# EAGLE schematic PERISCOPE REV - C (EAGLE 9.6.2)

## Sheet 1 of 20: Clock, Horizontal Sync

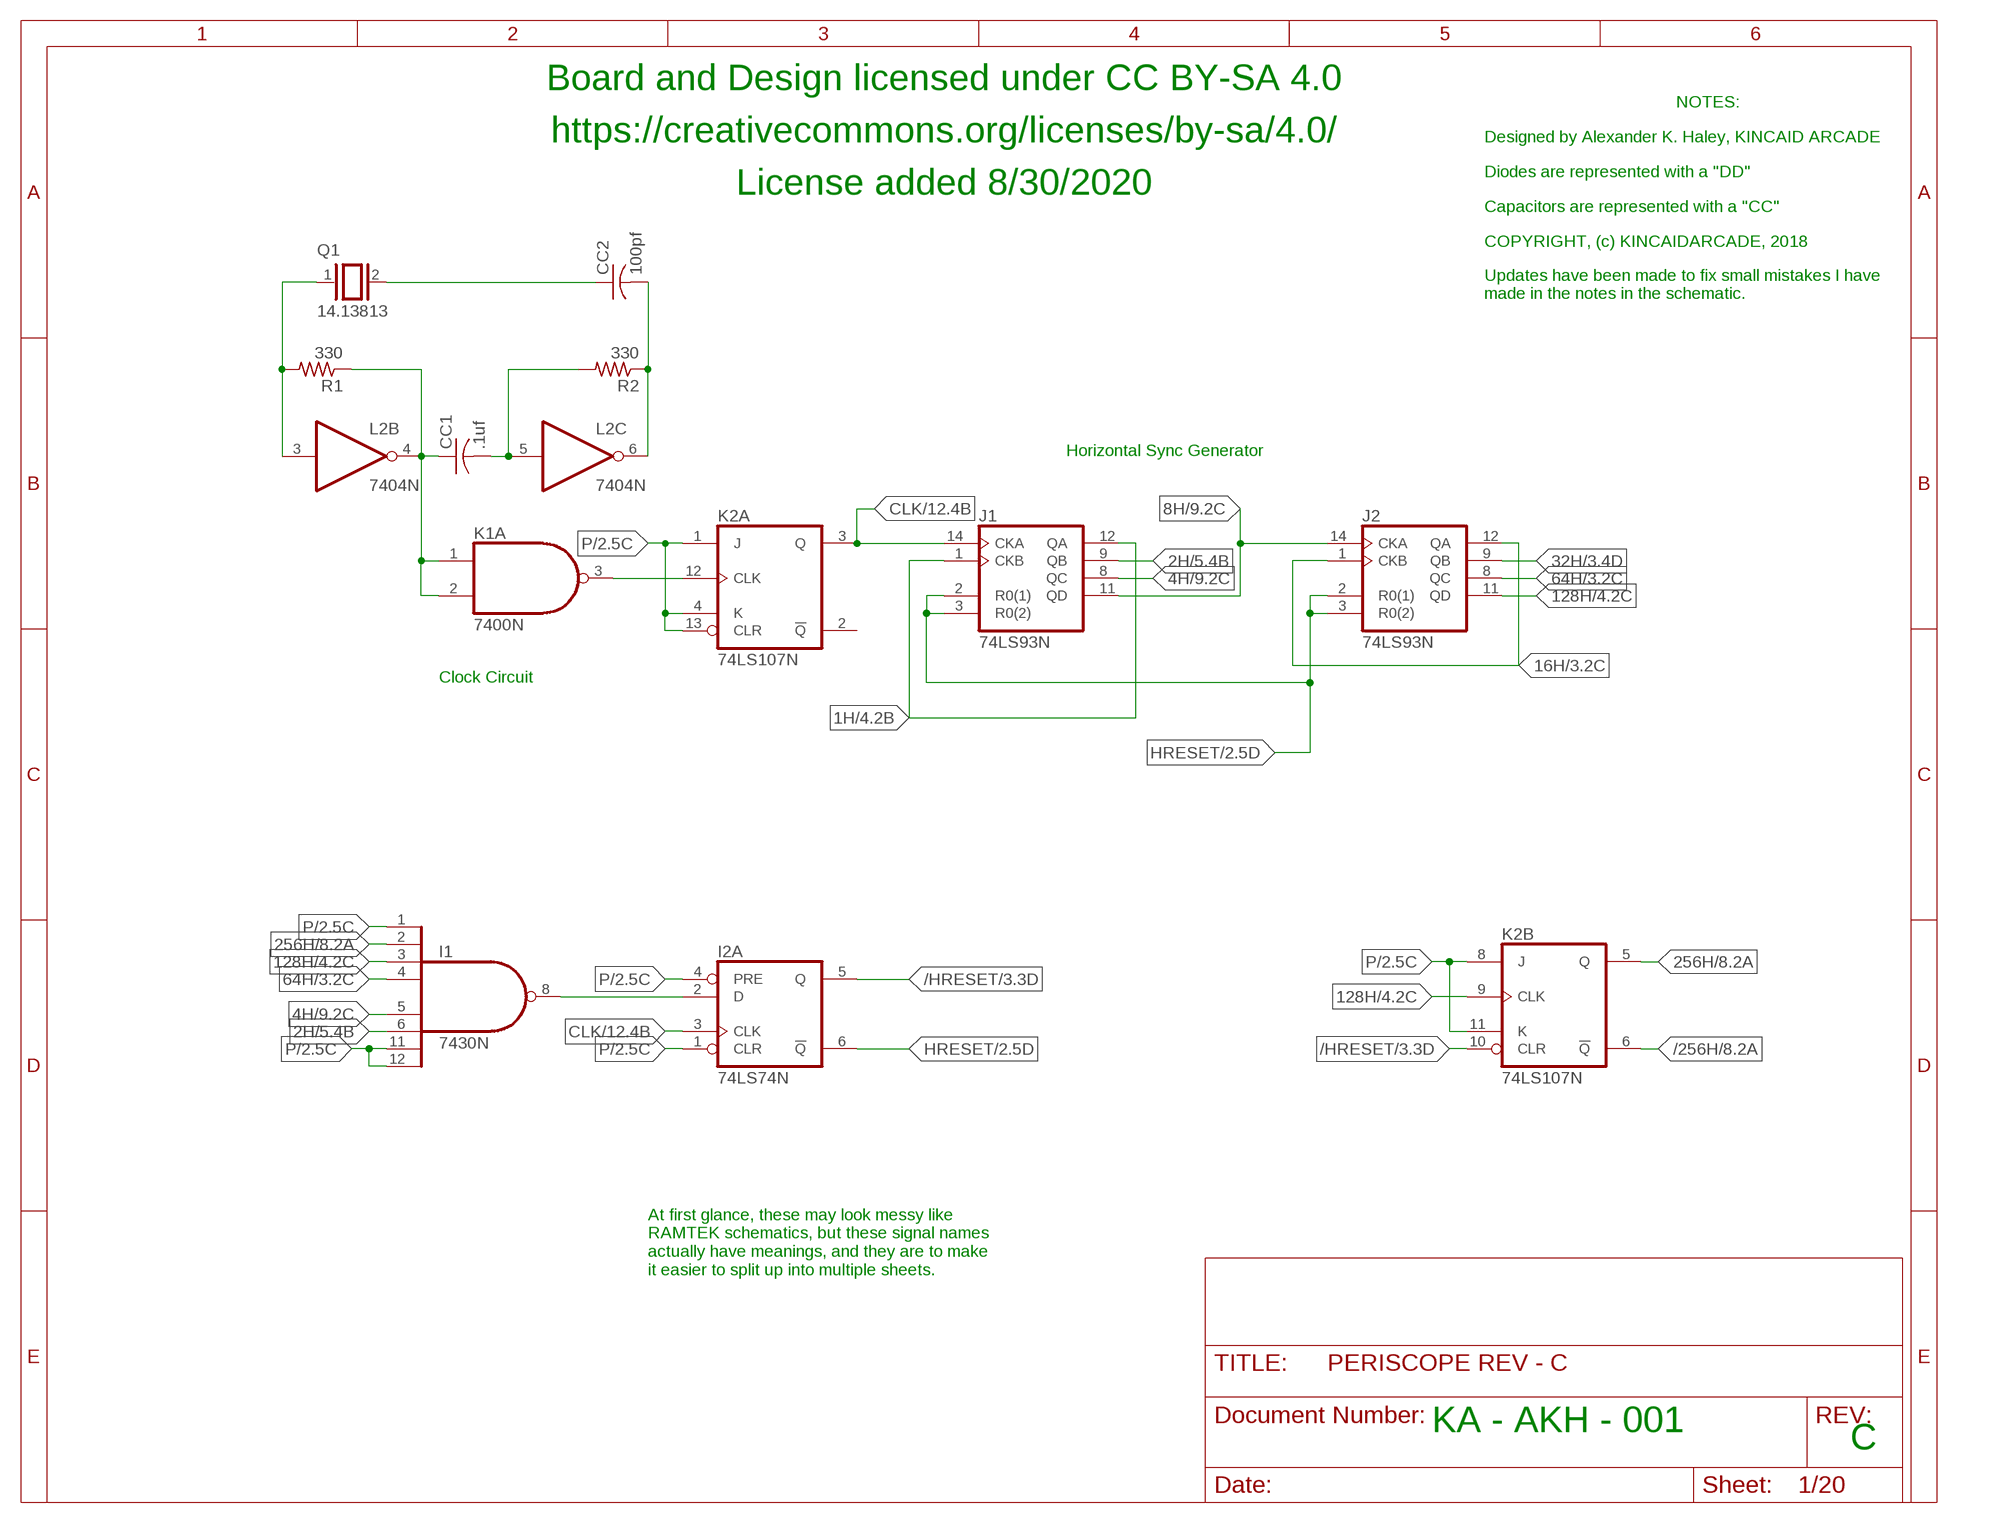
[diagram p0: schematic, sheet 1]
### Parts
CC1  .1uf  C-US050-025X075  [C050-025X075]
CC2  100pf  C-US050-025X075  [C050-025X075]
I1  7430N  [DIL14]
I2  74LS74N  [DIL14]
J1  74LS93N  [DIL14]
J2  74LS93N  [DIL14]
K1  7400N  [DIL14]
K2  74LS107N  [DIL14]
L2  7404N  [DIL14]
Q1  14.13813  XTAL/S  [QS]
R1  330  R-US_0207/10  [0207/10]
R2  330  R-US_0207/10  [0207/10]

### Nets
1H: J1.1(CKB) J1.12(QA) ; also sheet 4,16,17
2H: I1.6(I5) J1.9(QB) ; also sheet 5,16,17
4H: I1.5(I4) J1.8(QC) ; also sheet 9,16,17
8H: J1.11(QD) J2.14(CKA) ; also sheet 9,16,17,19
16H: J2.1(CKB) J2.12(QA) ; also sheet 3,4,8,9,14
32H: J2.9(QB) ; also sheet 3,4,8,14
64H: I1.4(I3) J2.8(QC) ; also sheet 3,4,8,14
128H: I1.3(I2) J2.11(QD) K2.9(B:CLK) ; also sheet 4,8,19
256H: I1.2(I1) K2.5(B:Q) ; also sheet 8,14
/256H: K2.6(B:!Q) ; also sheet 8,19
/HRESET: I2.5(A:Q) K2.10(B:CLR) ; also sheet 3
CLK: I2.3(A:CLK) J1.14(CKA) K2.3(A:Q) ; also sheet 12,18
HRESET: I2.6(A:!Q) J1.2(R0(1)) J1.3(R0(2)) J2.2(R0(1)) J2.3(R0(2)) ; also sheet 2
N$1: CC2.1 Q1.2
N$2: CC2.2 L2.6(C:O) R2.1
N$3: CC1.1 K1.1(A:I0) K1.2(A:I1) L2.4(B:O) R1.1
N$4: CC1.2 L2.5(C:I) R2.2
N$5: L2.3(B:I) Q1.1 R1.2
N$6: K1.3(A:O) K2.12(A:CLK)
N$11: I1.8(O) I2.2(A:D)
P: I1.1(I0) I1.11(I6) I1.12(I7) I2.1(A:CLR) I2.4(A:PRE) K2.1(A:J) K2.4(A:K) K2.8(B:J) K2.11(B:K) K2.13(A:CLR) ; also sheet 2,6,7,8,9,10,11,14,15,18,19,20
Unconnected: K2.2(A:!Q)

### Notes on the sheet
- Board and Design licensed under CC BY-SA 4.0
- NOTES:
- https://creativecommons.org/licenses/by-sa/4.0/ | Designed by Alexander K. Haley, KINCAID ARCADE
- Diodes are represented with a "DD"
- License added 8/30/2020
- Capacitors are represented with a "CC"
- COPYRIGHT, (c) KINCAIDARCADE, 2018
- Updates have been made to fix small mistakes I have 
  made in the notes in the schematic.
- Horizontal Sync Generator
- Clock Circuit
- At first glance, these may look messy like
  RAMTEK schematics, but these signal names
  actually have meanings, and they are to make
  it easier to split up into multiple sheets.
- KA - AKH - 001
- C

## Sheet 2 of 20: Vertical Sync Generator

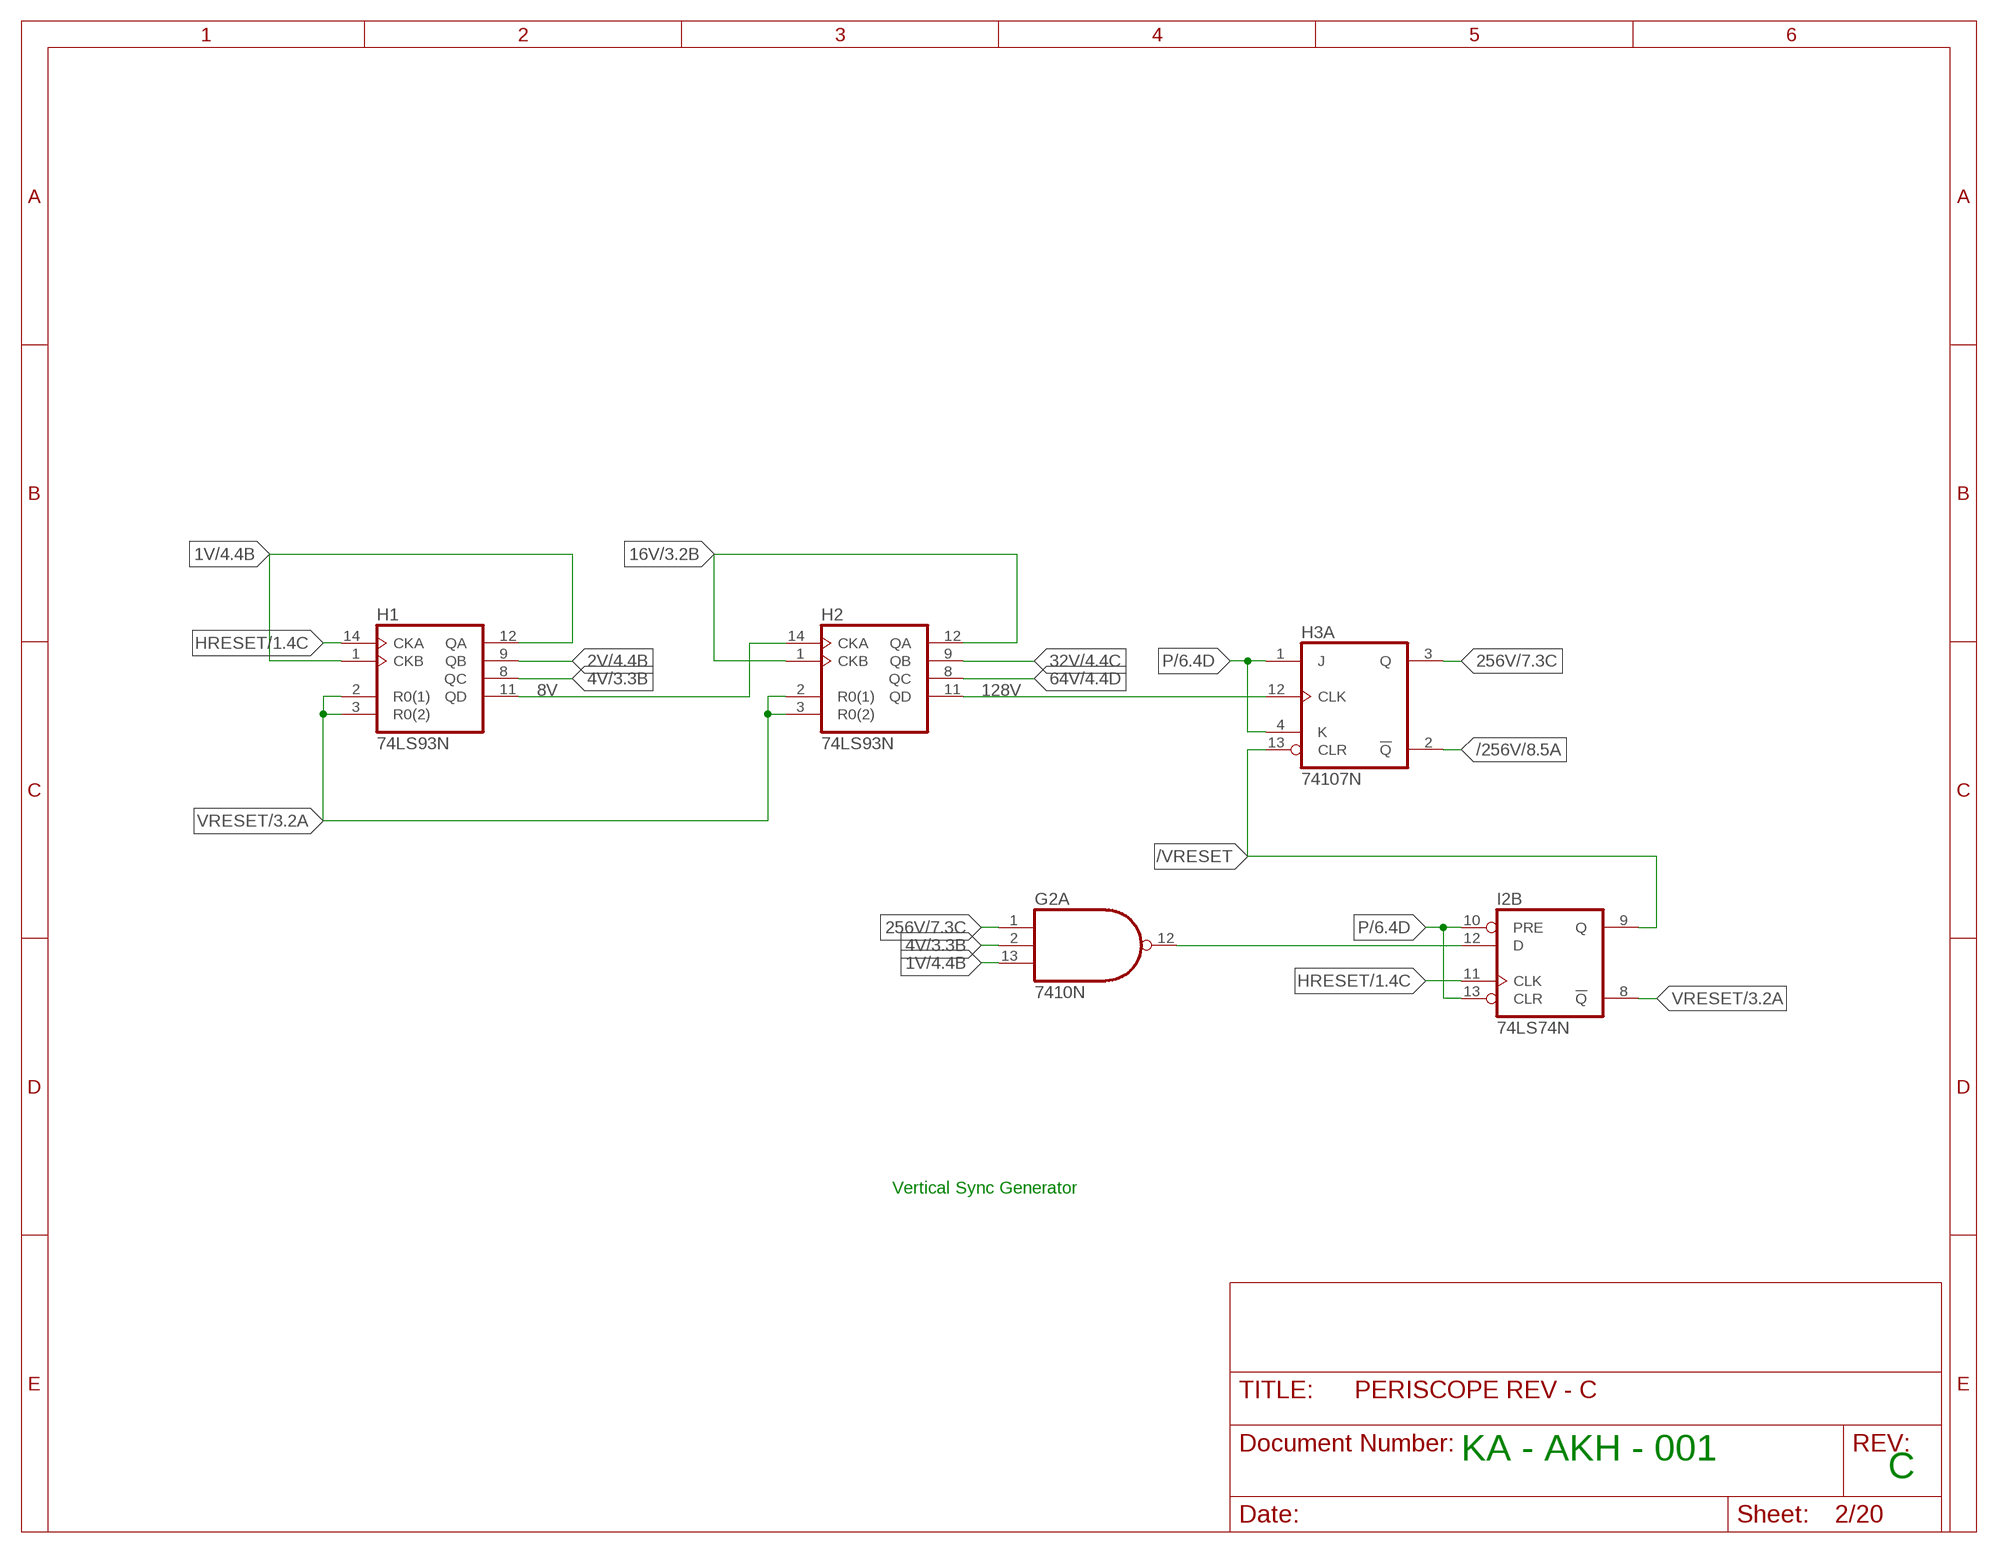
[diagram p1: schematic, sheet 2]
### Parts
G2  7410N  [DIL14]
H1  74LS93N  [DIL14]
H2  74LS93N  [DIL14]
H3  74107N  [DIL14]

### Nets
1V: G2.13(A:I2) H1.1(CKB) H1.12(QA) ; also sheet 4
2V: H1.9(QB) ; also sheet 4
4V: G2.2(A:I1) H1.8(QC) ; also sheet 3,4,9,19
8V: H1.11(QD) H2.14(CKA) ; also sheet 3,4,9,12,13
16V: H2.1(CKB) H2.12(QA) ; also sheet 3,4,9,10,15
32V: H2.9(QB) ; also sheet 4,8,10,15
64V: H2.8(QC) ; also sheet 4,10,15
128V: H2.11(QD) H3.12(A:CLK) ; also sheet 4,5,6,15
256V: G2.1(A:I0) H3.3(A:Q) ; also sheet 7,19
/256V: H3.2(A:!Q) ; also sheet 8
/VRESET: H3.13(A:CLR) I2.9(B:Q)
HRESET: H1.14(CKA) I2.11(B:CLK) ; also sheet 1
N$17: G2.12(A:O) I2.12(B:D)
P: H3.1(A:J) H3.4(A:K) I2.10(B:PRE) I2.13(B:CLR) ; also sheet 1,6,7,8,9,10,11,14,15,18,19,20
VRESET: H1.2(R0(1)) H1.3(R0(2)) H2.2(R0(1)) H2.3(R0(2)) I2.8(B:!Q) ; also sheet 3,11

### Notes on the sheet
- Vertical Sync Generator
- KA - AKH - 001
- C

## Sheet 3 of 20: Sync Generation

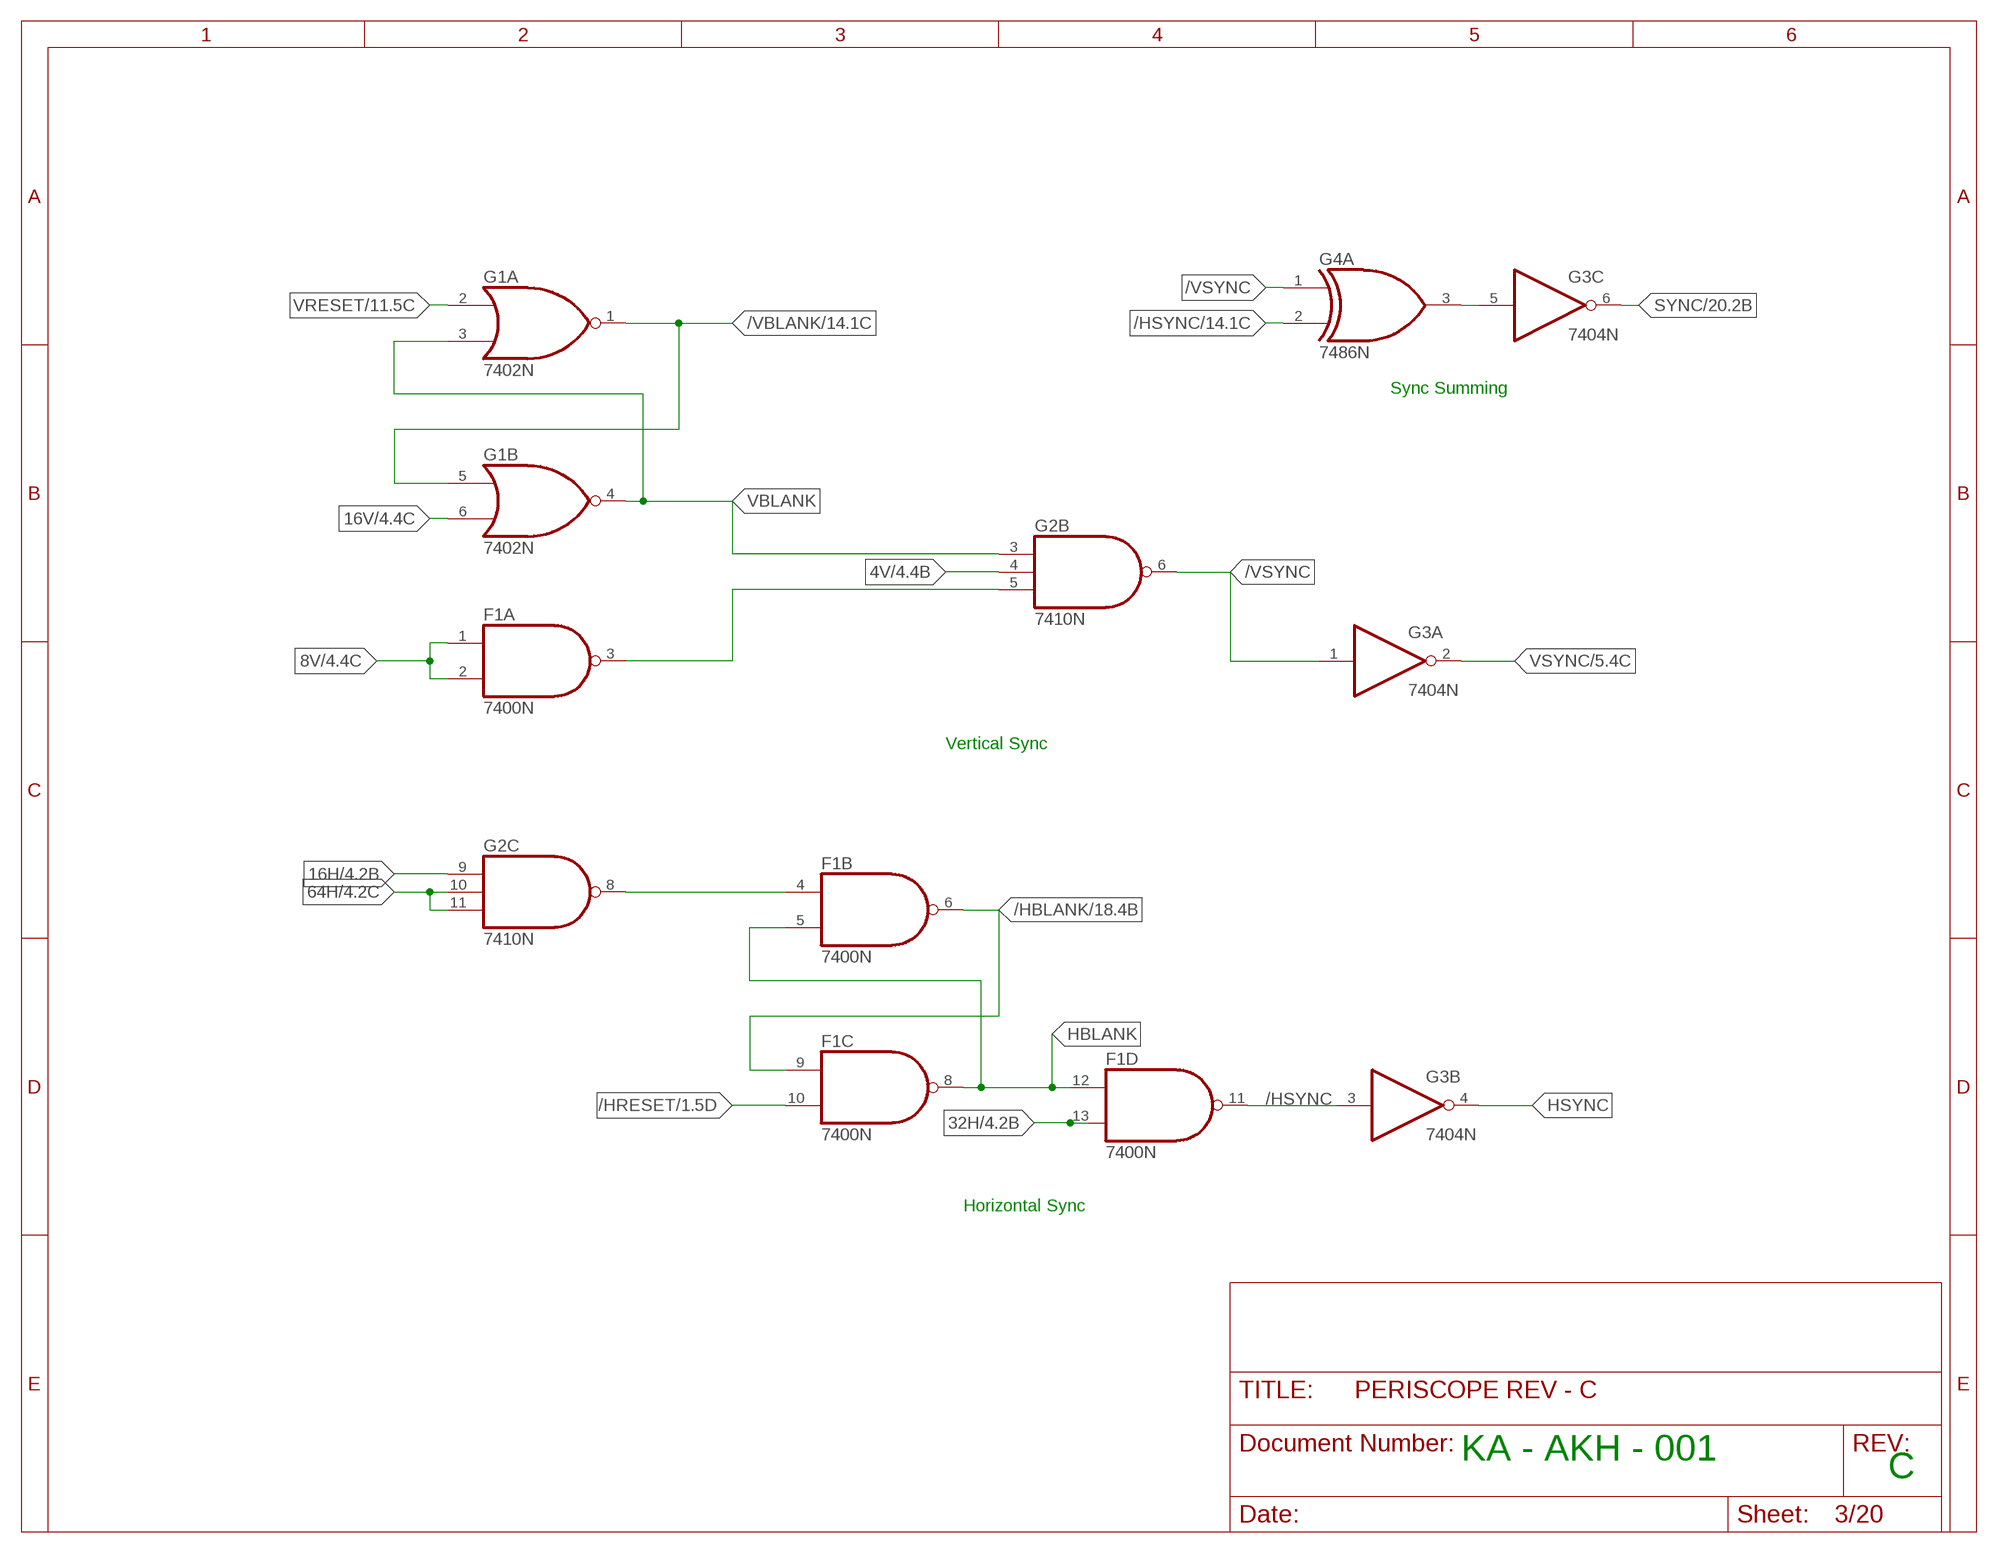
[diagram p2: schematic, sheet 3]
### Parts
F1  7400N  [DIL14]
G1  7402N  [DIL14]
G3  7404N  [DIL14]
G4  7486N  [DIL14]

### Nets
4V: G2.4(B:I1) ; also sheet 2,4,9,19
8V: F1.1(A:I0) F1.2(A:I1) ; also sheet 2,4,9,12,13
16H: G2.9(C:I0) ; also sheet 1,4,8,9,14
16V: G1.6(B:I1) ; also sheet 2,4,9,10,15
32H: F1.13(D:I1) ; also sheet 1,4,8,14
64H: G2.10(C:I1) G2.11(C:I2) ; also sheet 1,4,8,14
/HBLANK: F1.6(B:O) F1.9(C:I0) ; also sheet 18
/HRESET: F1.10(C:I1) ; also sheet 1
/HSYNC: F1.11(D:O) G3.3(B:I) G4.2(A:I1) ; also sheet 14,18
/VBLANK: G1.1(A:O) G1.5(B:I0) ; also sheet 14,18
/VSYNC: G2.6(B:O) G3.1(A:I) G4.1(A:I0)
HBLANK: F1.5(B:I1) F1.8(C:O) F1.12(D:I0)
HSYNC: G3.4(B:O)
N$19: F1.4(B:I0) G2.8(C:O)
N$20: F1.3(A:O) G2.5(B:I2)
N$22: G3.5(C:I) G4.3(A:O)
SYNC: G3.6(C:O) ; also sheet 20
VBLANK: G1.3(A:I1) G1.4(B:O) G2.3(B:I0)
VRESET: G1.2(A:I0) ; also sheet 2,11
VSYNC: G3.2(A:O) ; also sheet 5

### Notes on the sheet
- Sync Summing
- Vertical Sync
- Horizontal Sync
- KA - AKH - 001
- C

## Sheet 4 of 20: SYNC INVERSION

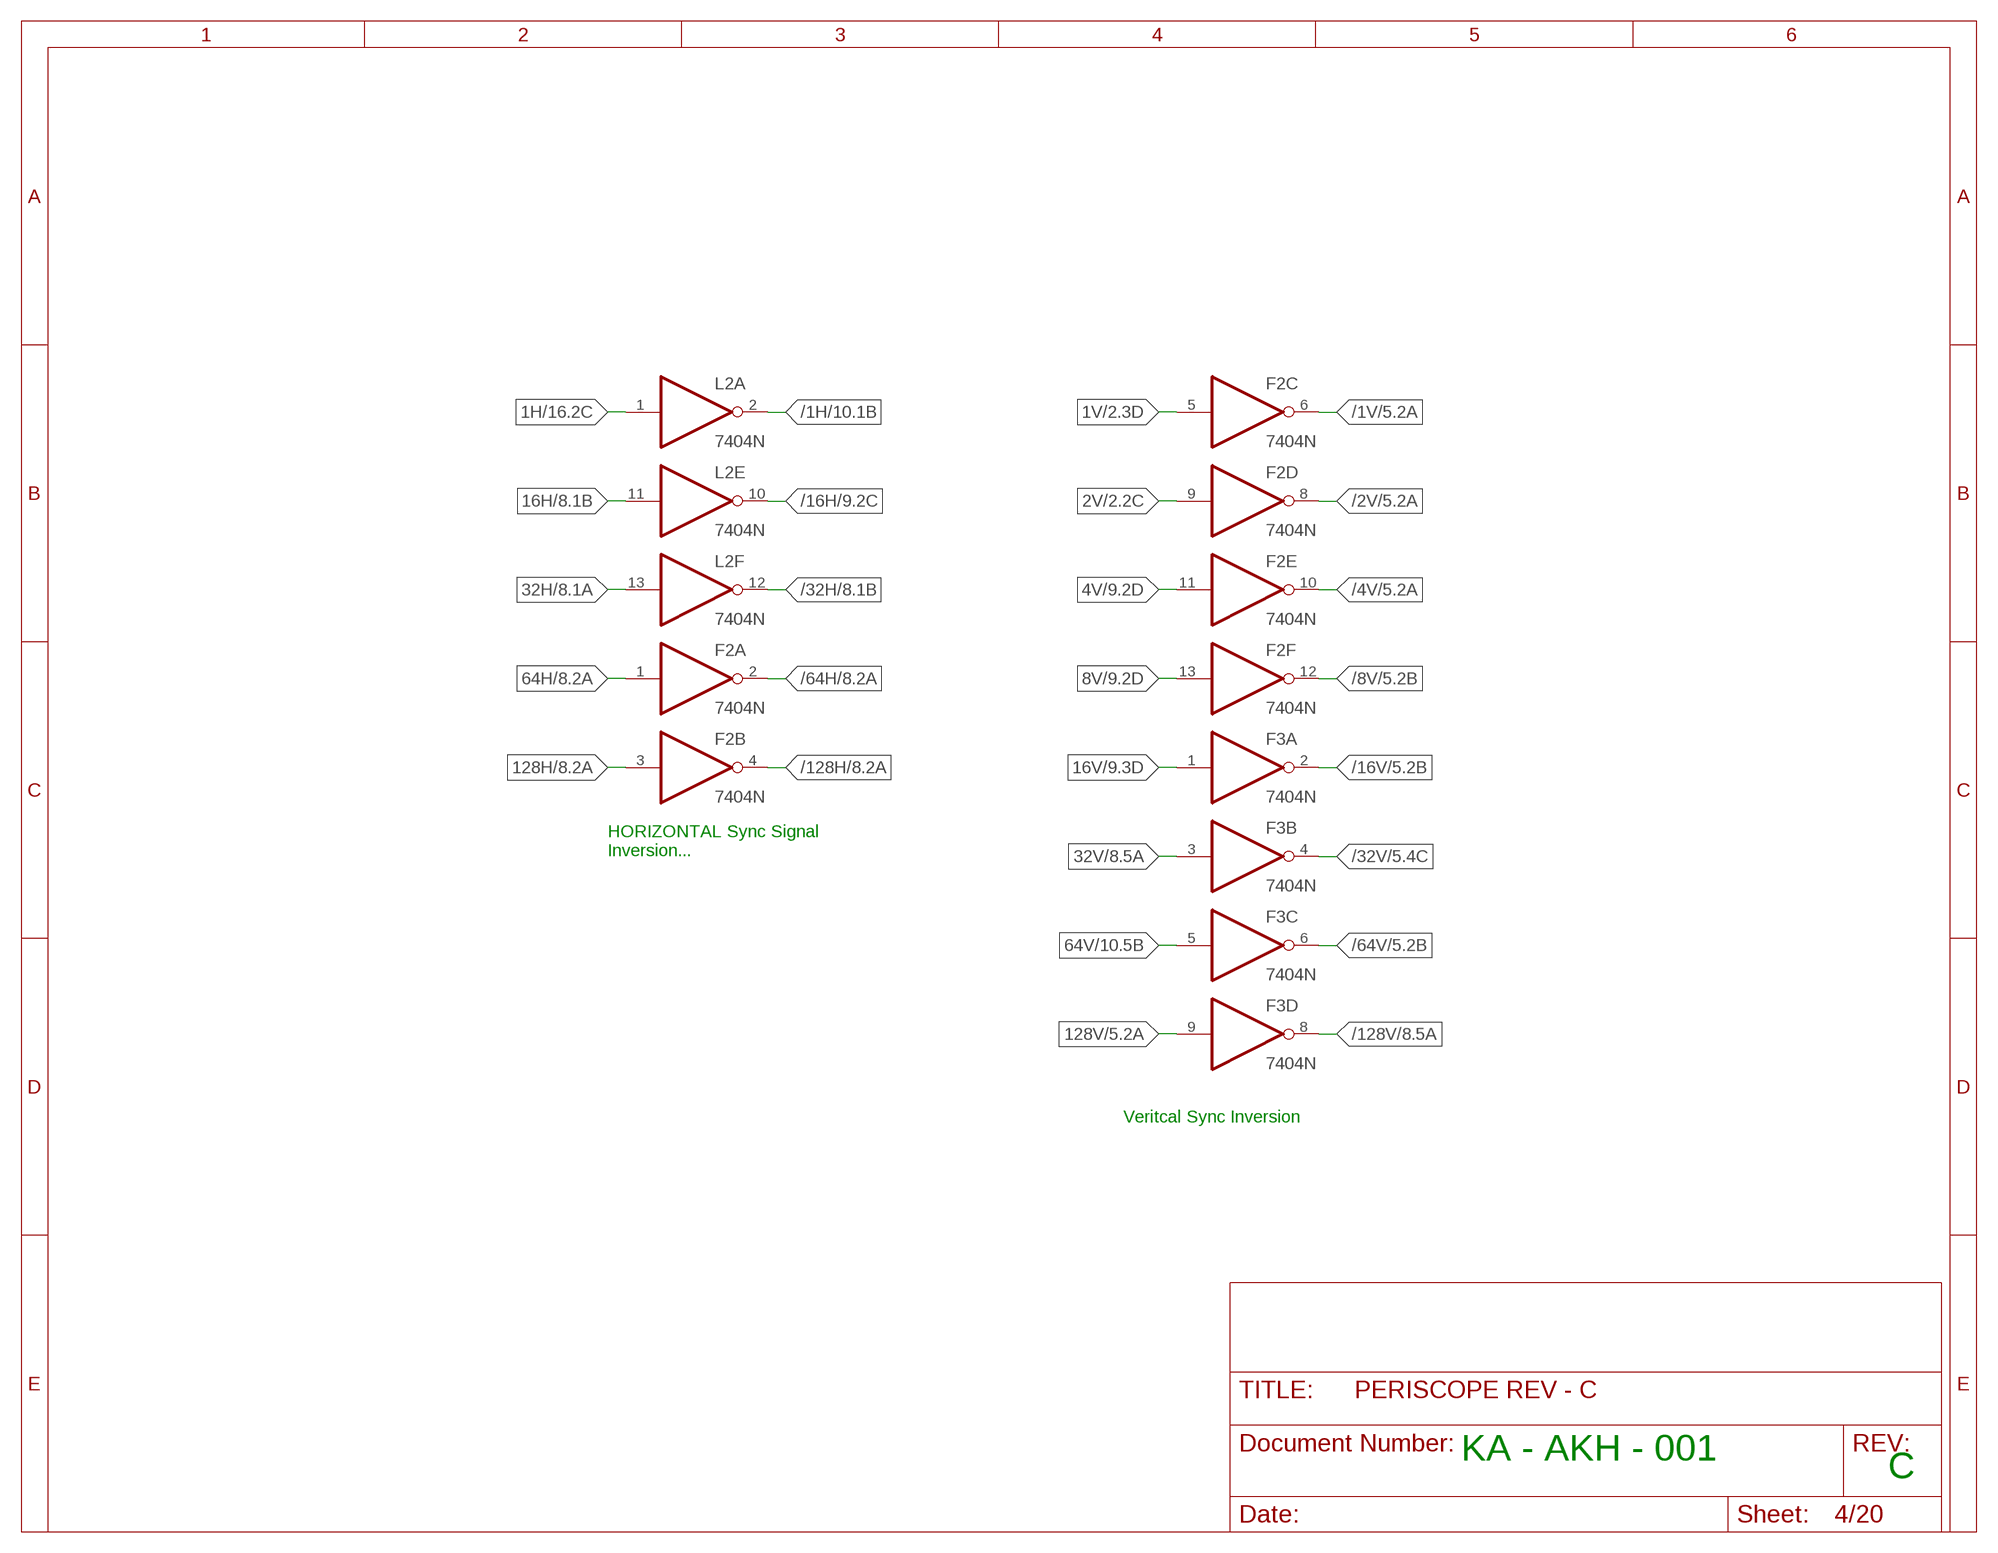
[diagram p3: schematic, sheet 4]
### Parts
F2  7404N  [DIL14]
F3  7404N  [DIL14]

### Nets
1H: L2.1(A:I) ; also sheet 1,16,17
1V: F2.5(C:I) ; also sheet 2
2V: F2.9(D:I) ; also sheet 2
4V: F2.11(E:I) ; also sheet 2,3,9,19
8V: F2.13(F:I) ; also sheet 2,3,9,12,13
16H: L2.11(E:I) ; also sheet 1,3,8,9,14
16V: F3.1(A:I) ; also sheet 2,3,9,10,15
32H: L2.13(F:I) ; also sheet 1,3,8,14
32V: F3.3(B:I) ; also sheet 2,8,10,15
64H: F2.1(A:I) ; also sheet 1,3,8,14
64V: F3.5(C:I) ; also sheet 2,10,15
128H: F2.3(B:I) ; also sheet 1,8,19
128V: F3.9(D:I) ; also sheet 2,5,6,15
/1H: L2.2(A:O) ; also sheet 10
/1V: F2.6(C:O) ; also sheet 5,12,13
/2V: F2.8(D:O) ; also sheet 5,12,13
/4V: F2.10(E:O) ; also sheet 5,12,13
/8V: F2.12(F:O) ; also sheet 5,12,13
/16H: L2.10(E:O) ; also sheet 9
/16V: F3.2(A:O) ; also sheet 5,9
/32H: L2.12(F:O) ; also sheet 8,19
/32V: F3.4(B:O) ; also sheet 5,15
/64H: F2.2(A:O) ; also sheet 8,19
/64V: F3.6(C:O) ; also sheet 5,8,15
/128H: F2.4(B:O) ; also sheet 8,14
/128V: F3.8(D:O) ; also sheet 8,10

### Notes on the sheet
- HORIZONTAL Sync Signal
  Inversion...
- Veritcal Sync Inversion
- KA - AKH - 001
- C

## Sheet 5 of 20: Ocean Generation, Sound, and RGB

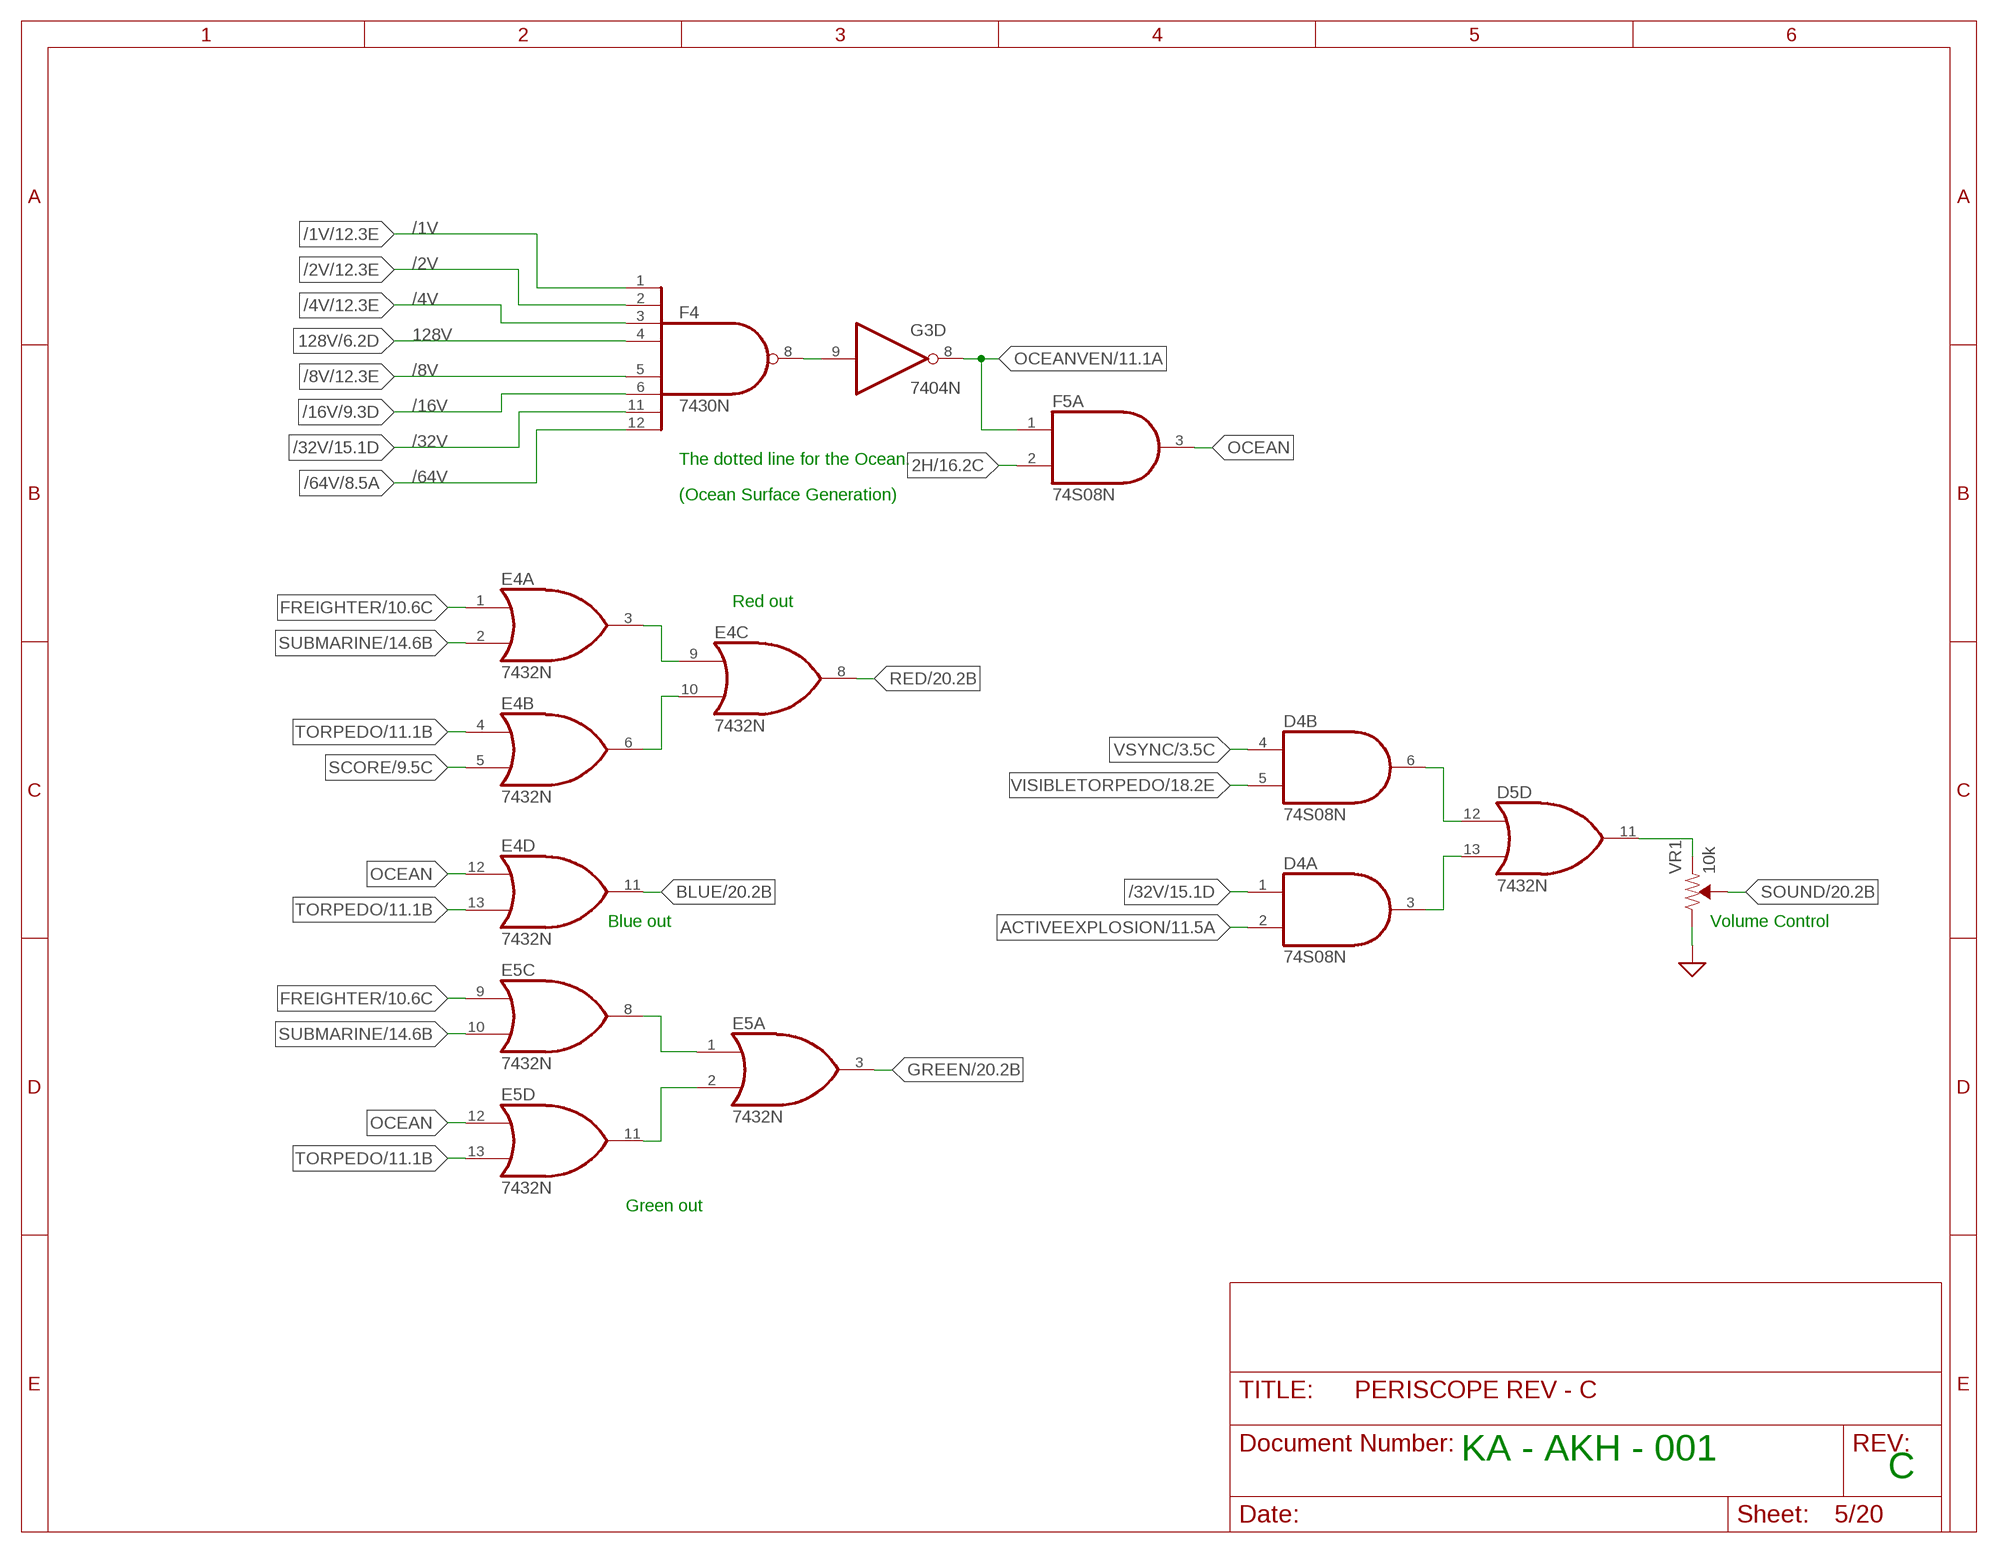
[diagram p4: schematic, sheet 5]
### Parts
D4  74S08N  [DIL14]
D5  7432N  [DIL14]
E4  7432N  [DIL14]
E5  7432N  [DIL14]
F4  7430N  [DIL14]
F5  74S08N  [DIL14]
VR1  10k  TRIMPOT-PTH-10MM-KNOB-1/2W-10%  [TRIMPOT-PTH-3386U]

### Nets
2H: F5.2(A:I1) ; also sheet 1,16,17
128V: F4.4(I3) ; also sheet 2,4,6,15
/1V: F4.1(I0) ; also sheet 4,12,13
/2V: F4.2(I1) ; also sheet 4,12,13
/4V: F4.3(I2) ; also sheet 4,12,13
/8V: F4.5(I4) ; also sheet 4,12,13
/16V: F4.6(I5) ; also sheet 4,9
/32V: D4.1(A:I0) F4.11(I6) ; also sheet 4,15
/64V: F4.12(I7) ; also sheet 4,8,15
ACTIVEEXPLOSION: D4.2(A:I1) ; also sheet 11,13
BLUE: E4.11(D:O) ; also sheet 20
FREIGHTER: E4.1(A:I0) E5.9(C:I0) ; also sheet 10
GND: VR1.3(CW) ; supply symbol labelled SUP ; also sheet 6,7,8,10,12,13,14,16,17,18,20
GREEN: E5.3(A:O) ; also sheet 20
N$7: D5.11(D:O) VR1.1(CCW)
N$28: F4.8(O) G3.9(D:I)
N$115: E4.3(A:O) E4.9(C:I0)
N$117: E4.6(B:O) E4.10(C:I1)
N$119: D4.6(B:O) D5.12(D:I0)
N$121: E5.2(A:I1) E5.11(D:O)
N$122: E5.1(A:I0) E5.8(C:O)
N$135: D4.3(A:O) D5.13(D:I1)
OCEAN: E4.12(D:I0) E5.12(D:I0) F5.3(A:O)
OCEANVEN: F5.1(A:I0) G3.8(D:O) ; also sheet 11,19
RED: E4.8(C:O) ; also sheet 20
SCORE: E4.5(B:I1) ; also sheet 9
SOUND: VR1.2(WIPER) ; also sheet 20
SUBMARINE: E4.2(A:I1) E5.10(C:I1) ; also sheet 14
TORPEDO: E4.4(B:I0) E4.13(D:I1) E5.13(D:I1) ; also sheet 11,18,19
VISIBLETORPEDO: D4.5(B:I1) ; also sheet 18,19
VSYNC: D4.4(B:I0) ; also sheet 3

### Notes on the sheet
- The dotted line for the Ocean.
- (Ocean Surface Generation)
- Red out
- Blue out | Volume Control
- Green out
- KA - AKH - 001
- C

## Sheet 6 of 20: Coin / Fraud Detection

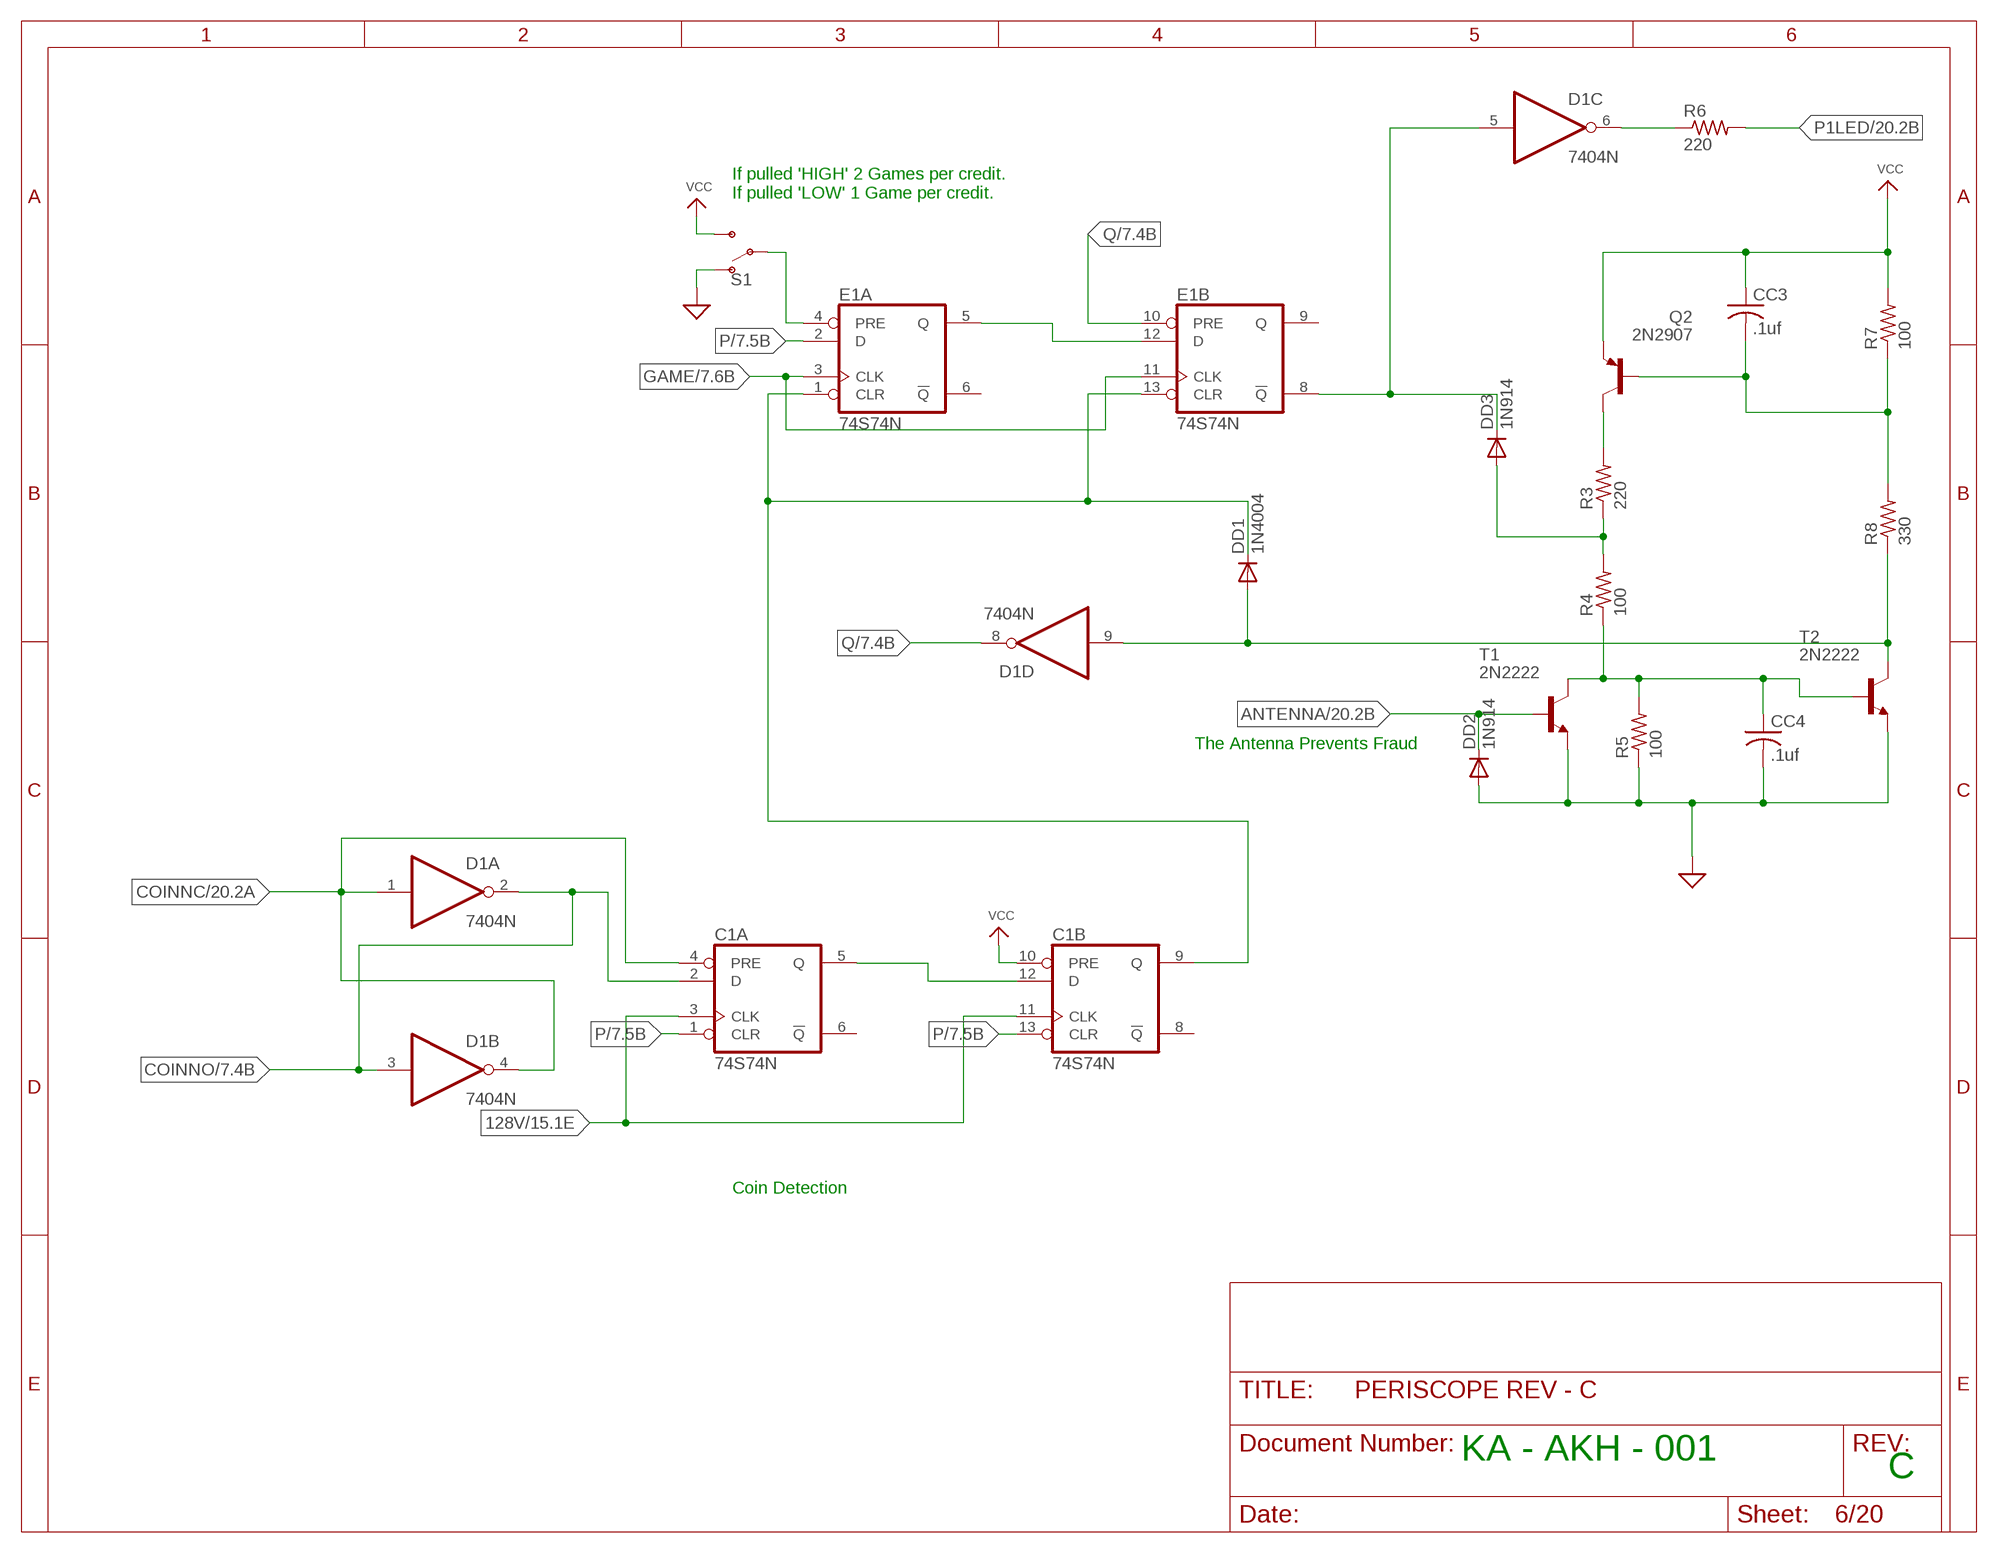
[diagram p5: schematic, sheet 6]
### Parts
C1  74S74N  [DIL14]
CC3  .1uf  C-US025-024X044  [C025-024X044]
CC4  .1uf  C-US025-024X044  [C025-024X044]
D1  7404N  [DIL14]
DD1  1N4004  [DO41-10]
DD2  1N914  1N4004  [DO41-10]
DD3  1N914  1N4004  [DO41-10]
E1  74S74N  [DIL14]
Q2  2N2907  [TO92-EBC-OVAL]
R3  220  R-US_0207/10  [0207/10]
R4  100  R-US_0207/10  [0207/10]
R5  100  R-US_0207/10  [0207/10]
R6  220  R-US_0207/10  [0207/10]
R7  100  R-US_0207/10  [0207/10]
R8  330  R-US_0207/10  [0207/10]
S1  SWITCH-SPDT-PTH-11.6X4.0MM  [SWITCH_SPDT_PTH_11.6X4.0MM]
T1  2N2222  [TO92-EBC-OVAL]
T2  2N2222  [TO92-EBC-OVAL]

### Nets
128V: C1.3(A:CLK) C1.11(B:CLK) ; also sheet 2,4,5,15
ANTENNA: DD2.C T1.B ; also sheet 20
COINNC: C1.4(A:PRE) D1.1(A:I) D1.4(B:O) ; also sheet 20
COINNO: C1.2(A:D) D1.2(A:O) D1.3(B:I) ; also sheet 7,20
GAME: E1.3(A:CLK) E1.11(B:CLK) ; also sheet 7,15
GND: CC4.2 DD2.A R5.1 S1.1(O) T1.E T2.E ; supply symbol labelled SUP ; also sheet 5,7,8,10,12,13,14,16,17,18,20
N$95: Q2.C R3.2
N$96: E1.5(A:Q) E1.12(B:D)
N$97: C1.5(A:Q) C1.12(B:D)
N$99: C1.9(B:Q) DD1.C E1.1(A:CLR) E1.13(B:CLR)
N$100: E1.4(A:PRE) S1.2(P)
N$101: D1.5(C:I) DD3.C E1.8(B:!Q)
N$102: D1.6(C:O) R6.1
N$103: DD3.A R3.1 R4.2
N$105: D1.9(D:I) DD1.A R8.1 T2.C
N$106: CC3.2 Q2.B R7.1 R8.2
N$107: CC4.1 R4.1 R5.2 T1.C T2.B
P: C1.1(A:CLR) C1.13(B:CLR) E1.2(A:D) ; also sheet 1,2,7,8,9,10,11,14,15,18,19,20
P1LED: R6.2 ; also sheet 20
Q: D1.8(D:O) E1.10(B:PRE) ; also sheet 7
VCC: C1.10(B:PRE) CC3.1 Q2.E R7.2 S1.3(S) ; also sheet 7,8,12,13,15,16,17,18,20
Unconnected: C1.6(A:!Q) C1.8(B:!Q) E1.6(A:!Q) E1.9(B:Q)

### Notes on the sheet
- If pulled 'HIGH' 2 Games per credit.
  If pulled 'LOW' 1 Game per credit.
- The Antenna Prevents Fraud
- Coin Detection
- KA - AKH - 001
- C

## Sheet 7 of 20: Game / Start

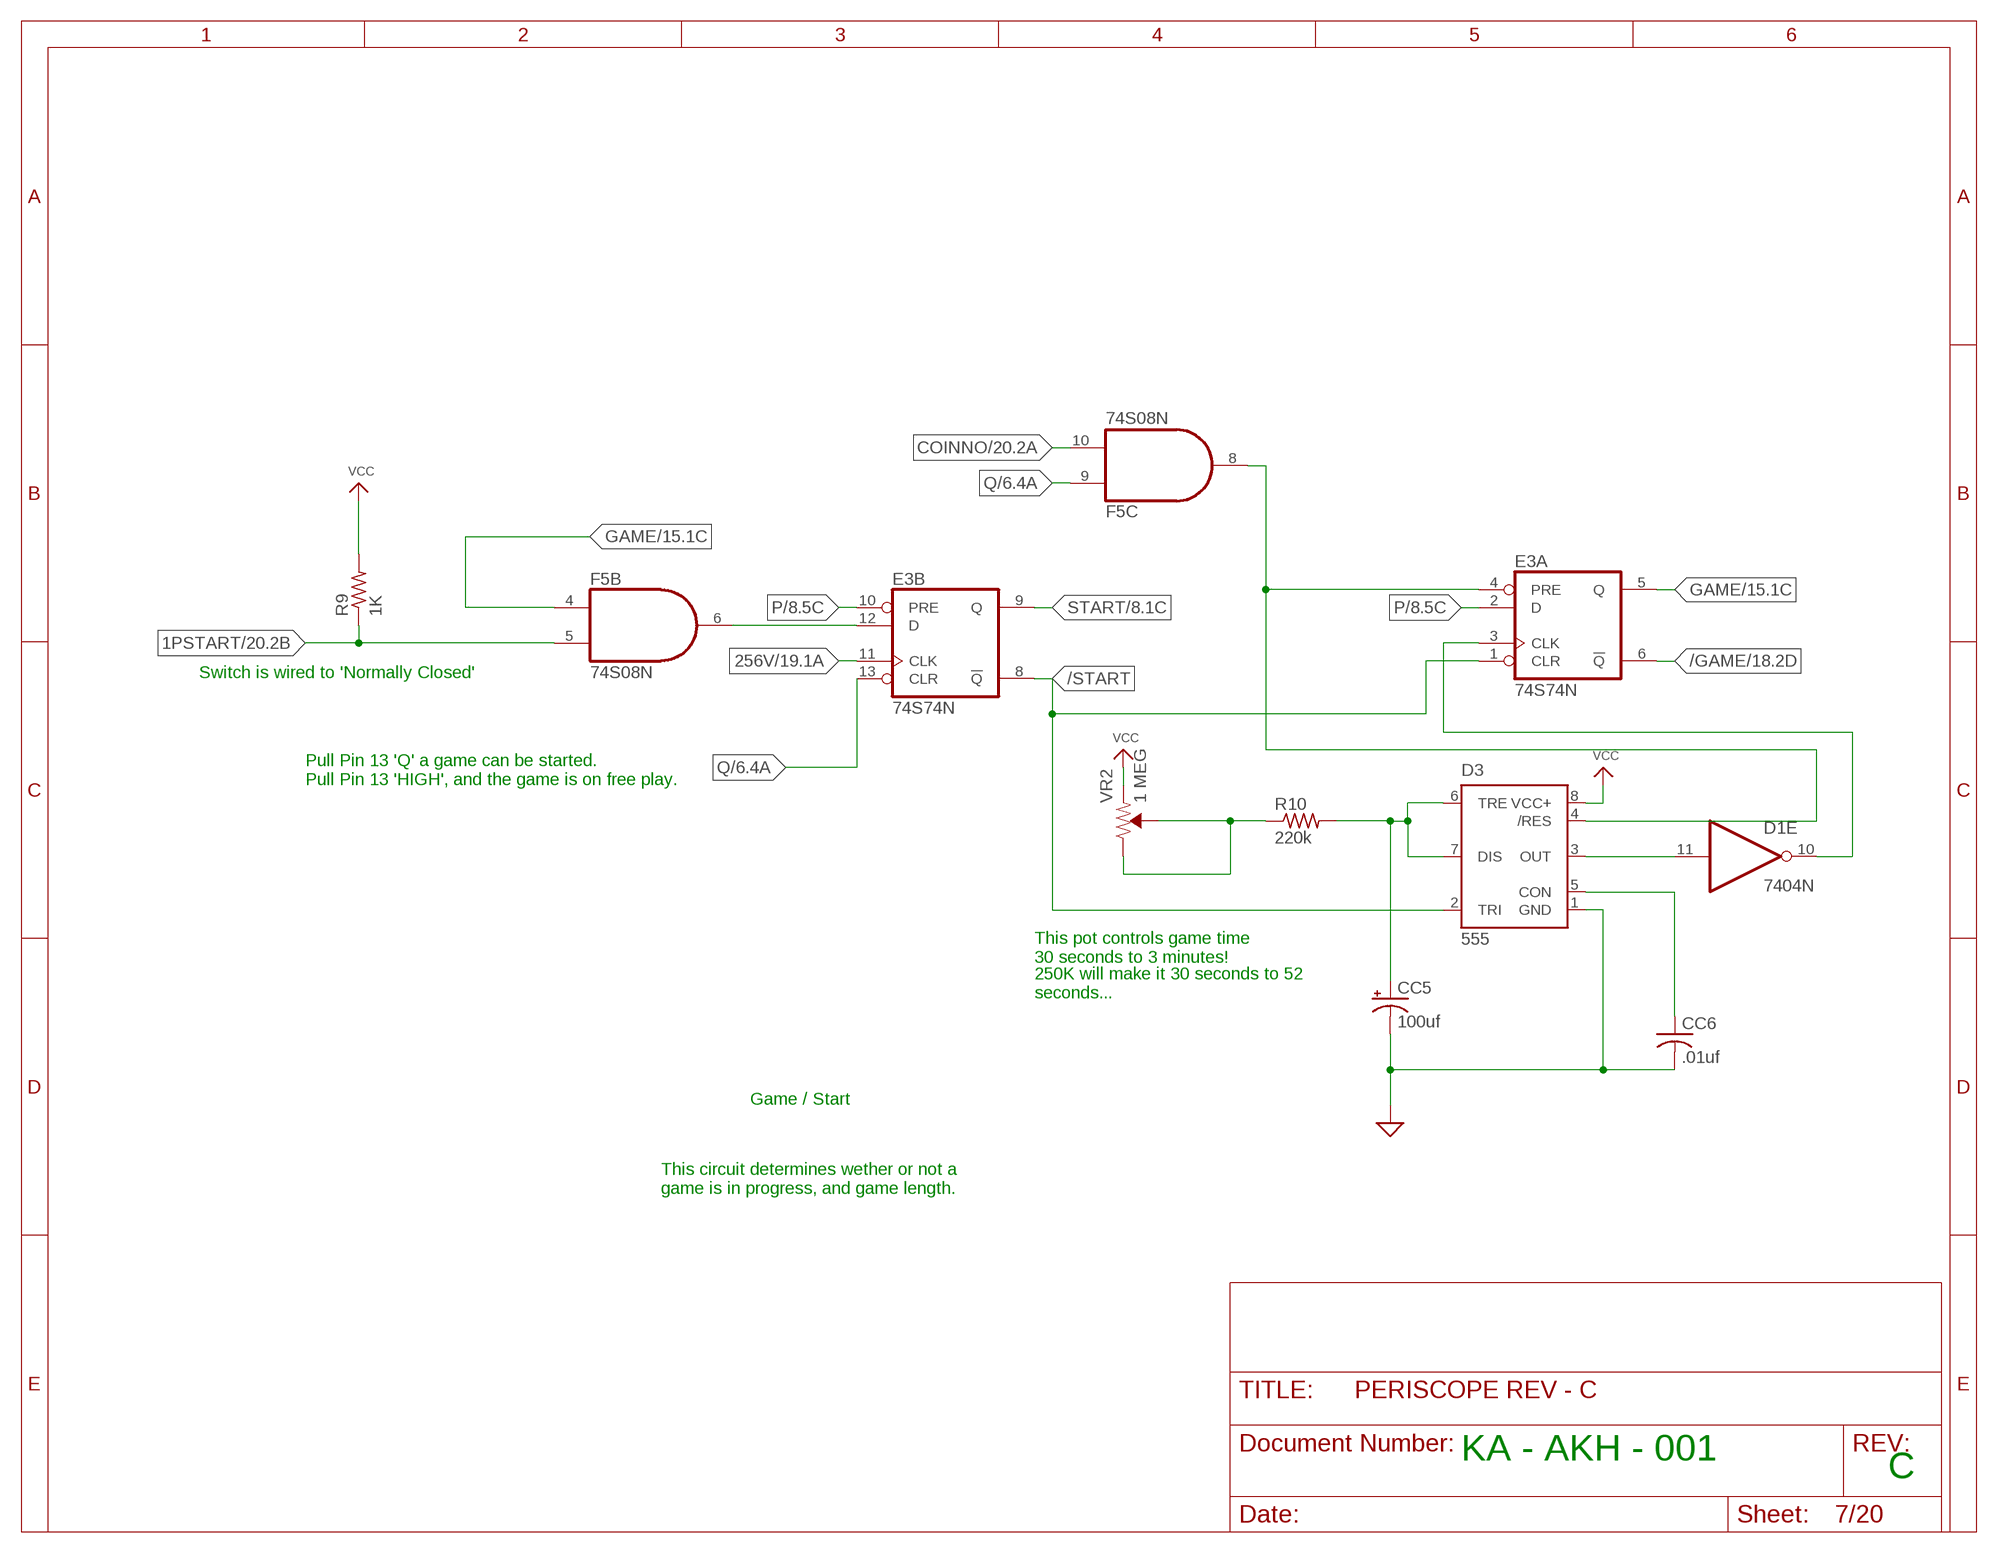
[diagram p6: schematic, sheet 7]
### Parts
CC5  100uf  CPOL-USE2.5-6  [E2,5-6]
CC6  .01uf  C-US025-024X044  [C025-024X044]
D3  555  555P  [DIP08]
E3  74S74N  [DIL14]
R9  1K  R-US_0207/10  [0207/10]
R10  220k  R-US_0207/10  [0207/10]
VR2  1 MEG  TRIMPOT-PTH-10MM-KNOB-1/2W-10%  [TRIMPOT-PTH-3386U]

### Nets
1PSTART: F5.5(B:I1) R9.1 ; also sheet 20
256V: E3.11(B:CLK) ; also sheet 2,19
/GAME: E3.6(A:!Q) ; also sheet 18
/START: D3.2(TRI) E3.1(A:CLR) E3.8(B:!Q)
COINNO: F5.10(C:I1) ; also sheet 6,20
GAME: E3.5(A:Q) F5.4(B:I0) ; also sheet 6,15
GND: CC5.- CC6.2 D3.1(GND) ; supply symbol labelled SUP ; also sheet 5,6,8,10,12,13,14,16,17,18,20
N$104: D3.4(/RES) E3.4(A:PRE) F5.8(C:O)
N$108: E3.12(B:D) F5.6(B:O)
N$109: CC6.1 D3.5(CON)
N$112: D1.10(E:O) E3.3(A:CLK)
N$114: D1.11(E:I) D3.3(OUT)
N$116: CC5.+ D3.6(TRE) D3.7(DIS) R10.2
N$118: R10.1 VR2.2(WIPER) VR2.3(CW)
P: E3.2(A:D) E3.10(B:PRE) ; also sheet 1,2,6,8,9,10,11,14,15,18,19,20
Q: E3.13(B:CLR) F5.9(C:I0) ; also sheet 6
START: E3.9(B:Q) ; also sheet 8
VCC: D3.8(VCC+) R9.2 VR2.1(CCW) ; also sheet 6,8,12,13,15,16,17,18,20

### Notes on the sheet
- Switch is wired to 'Normally Closed'
- Pull Pin 13 'Q' a game can be started.
  Pull Pin 13 'HIGH', and the game is on free play.
- This pot controls game time
  30 seconds to 3 minutes!
- 250K will make it 30 seconds to 52
  seconds...
- Game / Start
- This circuit determines wether or not a
  game is in progress, and game length.
- KA - AKH - 001
- C

## Sheet 8 of 20: Score Counting

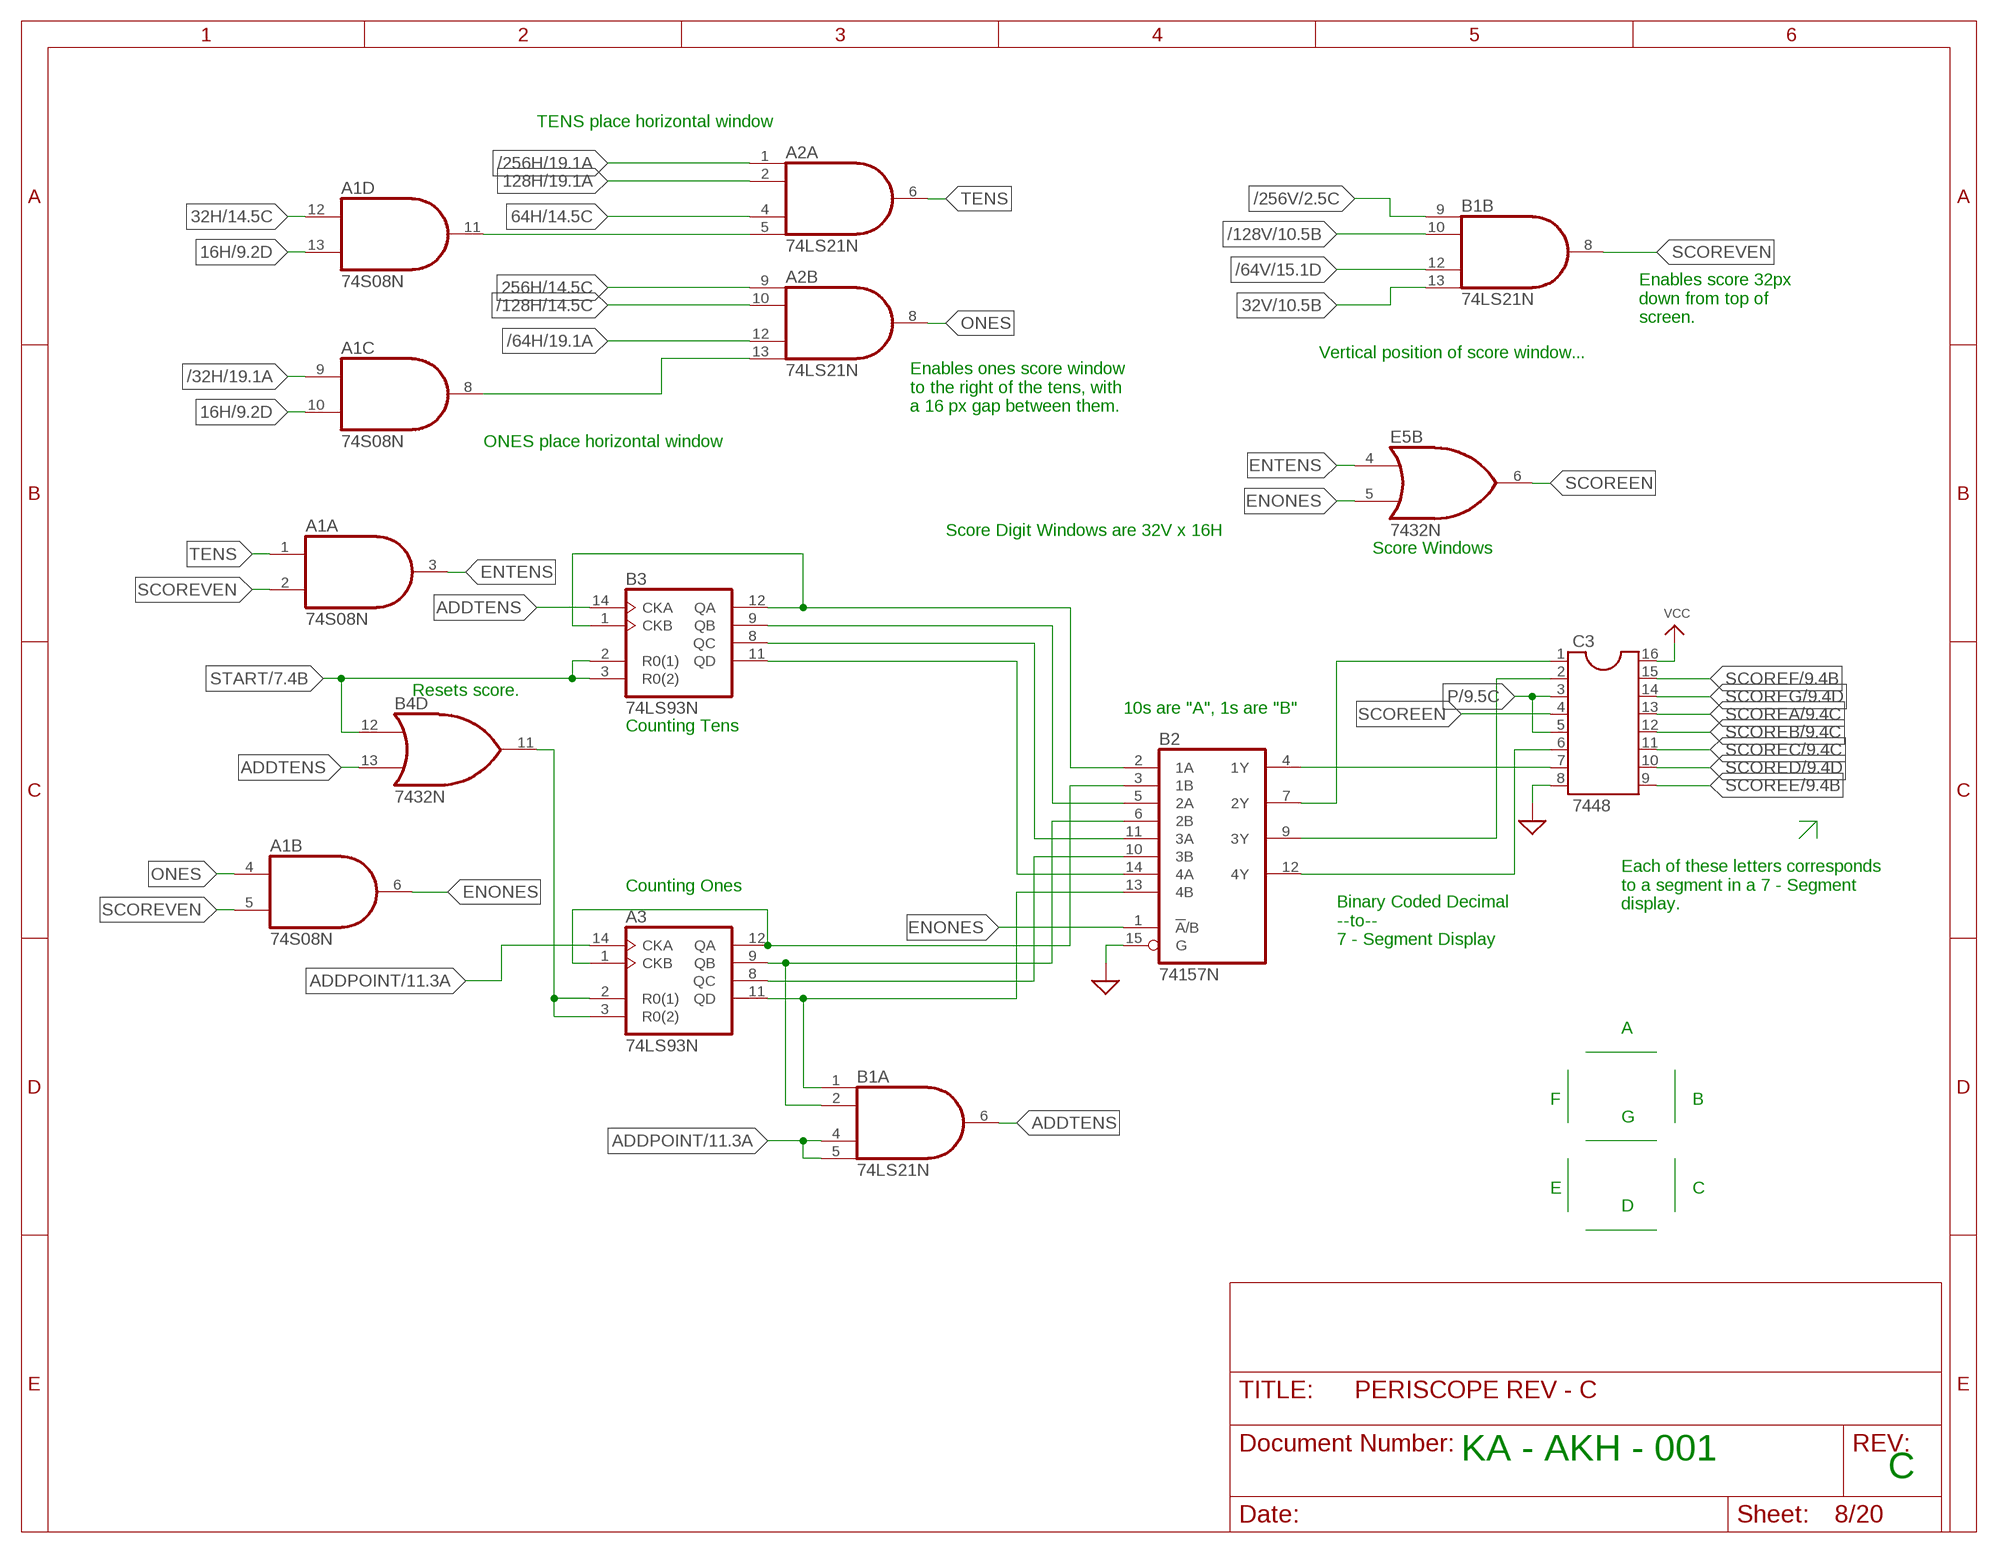
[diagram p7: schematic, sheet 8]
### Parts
A1  74S08N  [DIL14]
A2  74LS21N  [DIL14]
A3  74LS93N  [DIL14]
B1  74LS21N  [DIL14]
B2  74157N  [DIL16]
B3  74LS93N  [DIL14]
B4  7432N  [DIL14]
C3  7448  DIL16S  [SOCKET-16]

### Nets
16H: A1.10(C:I1) A1.13(D:I1) ; also sheet 1,3,4,9,14
32H: A1.12(D:I0) ; also sheet 1,3,4,14
32V: B1.13(B:I3) ; also sheet 2,4,10,15
64H: A2.4(A:I2) ; also sheet 1,3,4,14
128H: A2.2(A:I1) ; also sheet 1,4,19
256H: A2.9(B:I0) ; also sheet 1,14
/32H: A1.9(C:I0) ; also sheet 4,19
/64H: A2.12(B:I2) ; also sheet 4,19
/64V: B1.12(B:I2) ; also sheet 4,5,15
/128H: A2.10(B:I1) ; also sheet 4,14
/128V: B1.10(B:I1) ; also sheet 4,10
/256H: A2.1(A:I0) ; also sheet 1,19
/256V: B1.9(B:I0) ; also sheet 2
ADDPOINT: A3.14(CKA) B1.4(A:I2) B1.5(A:I3) ; also sheet 11
ADDTENS: B1.6(A:O) B3.14(CKA) B4.13(D:I1)
ENONES: A1.6(B:O) B2.1(!A!/B) E5.5(B:I1)
ENTENS: A1.3(A:O) E5.4(B:I0)
GND: B2.15(G) C3.8 ; supply symbol labelled SUP ; also sheet 5,6,7,10,12,13,14,16,17,18,20
N$33: B2.4(1Y) C3.7
N$35: A3.1(CKB) A3.12(QA) B2.3(1B)
N$125: B2.2(1A) B3.1(CKB) B3.12(QA)
N$126: A1.8(C:O) A2.13(B:I3)
N$128: B2.5(2A) B3.9(QB)
N$129: B2.11(3A) B3.8(QC)
N$130: B2.14(4A) B3.11(QD)
N$131: A3.9(QB) B1.2(A:I1) B2.6(2B)
N$133: A3.8(QC) B2.10(3B)
N$134: A3.11(QD) B1.1(A:I0) B2.13(4B)
N$143: A3.2(R0(1)) A3.3(R0(2)) B4.11(D:O)
N$144: B2.7(2Y) C3.1
N$145: B2.9(3Y) C3.2
N$146: B2.12(4Y) C3.6
N$211: A1.11(D:O) A2.5(A:I3)
ONES: A1.4(B:I0) A2.8(B:O)
P: C3.3 C3.5 ; also sheet 1,2,6,7,9,10,11,14,15,18,19,20
SCOREA: C3.13 ; also sheet 9
SCOREB: C3.12 ; also sheet 9
SCOREC: C3.11 ; also sheet 9
SCORED: C3.10 ; also sheet 9
SCOREE: C3.9 ; also sheet 9
SCOREEN: C3.4 E5.6(B:O)
SCOREF: C3.15 ; also sheet 9
SCOREG: C3.14 ; also sheet 9
SCOREVEN: A1.2(A:I1) A1.5(B:I1) B1.8(B:O)
START: B3.2(R0(1)) B3.3(R0(2)) B4.12(D:I0) ; also sheet 7
TENS: A1.1(A:I0) A2.6(A:O)
VCC: C3.16 ; also sheet 6,7,12,13,15,16,17,18,20

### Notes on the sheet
- TENS place horizontal window
- Enables score 32px
  down from top of
  screen.
- Vertical position of score window...
- Enables ones score window
  to the right of the tens, with
  a 16 px gap between them.
- ONES place horizontal window
- Score Digit Windows are 32V x 16H
- Score Windows
- Resets score.
- 10s are "A", 1s are "B"
- Counting Tens
- Counting Ones
- Each of these letters corresponds
  to a segment in a 7 - Segment 
  display.
- Binary Coded Decimal 
  --to--
  7 - Segment Display
- A
- F | B
- G
- E | C
- D
- KA - AKH - 001
- C

## Sheet 9 of 20: Score display

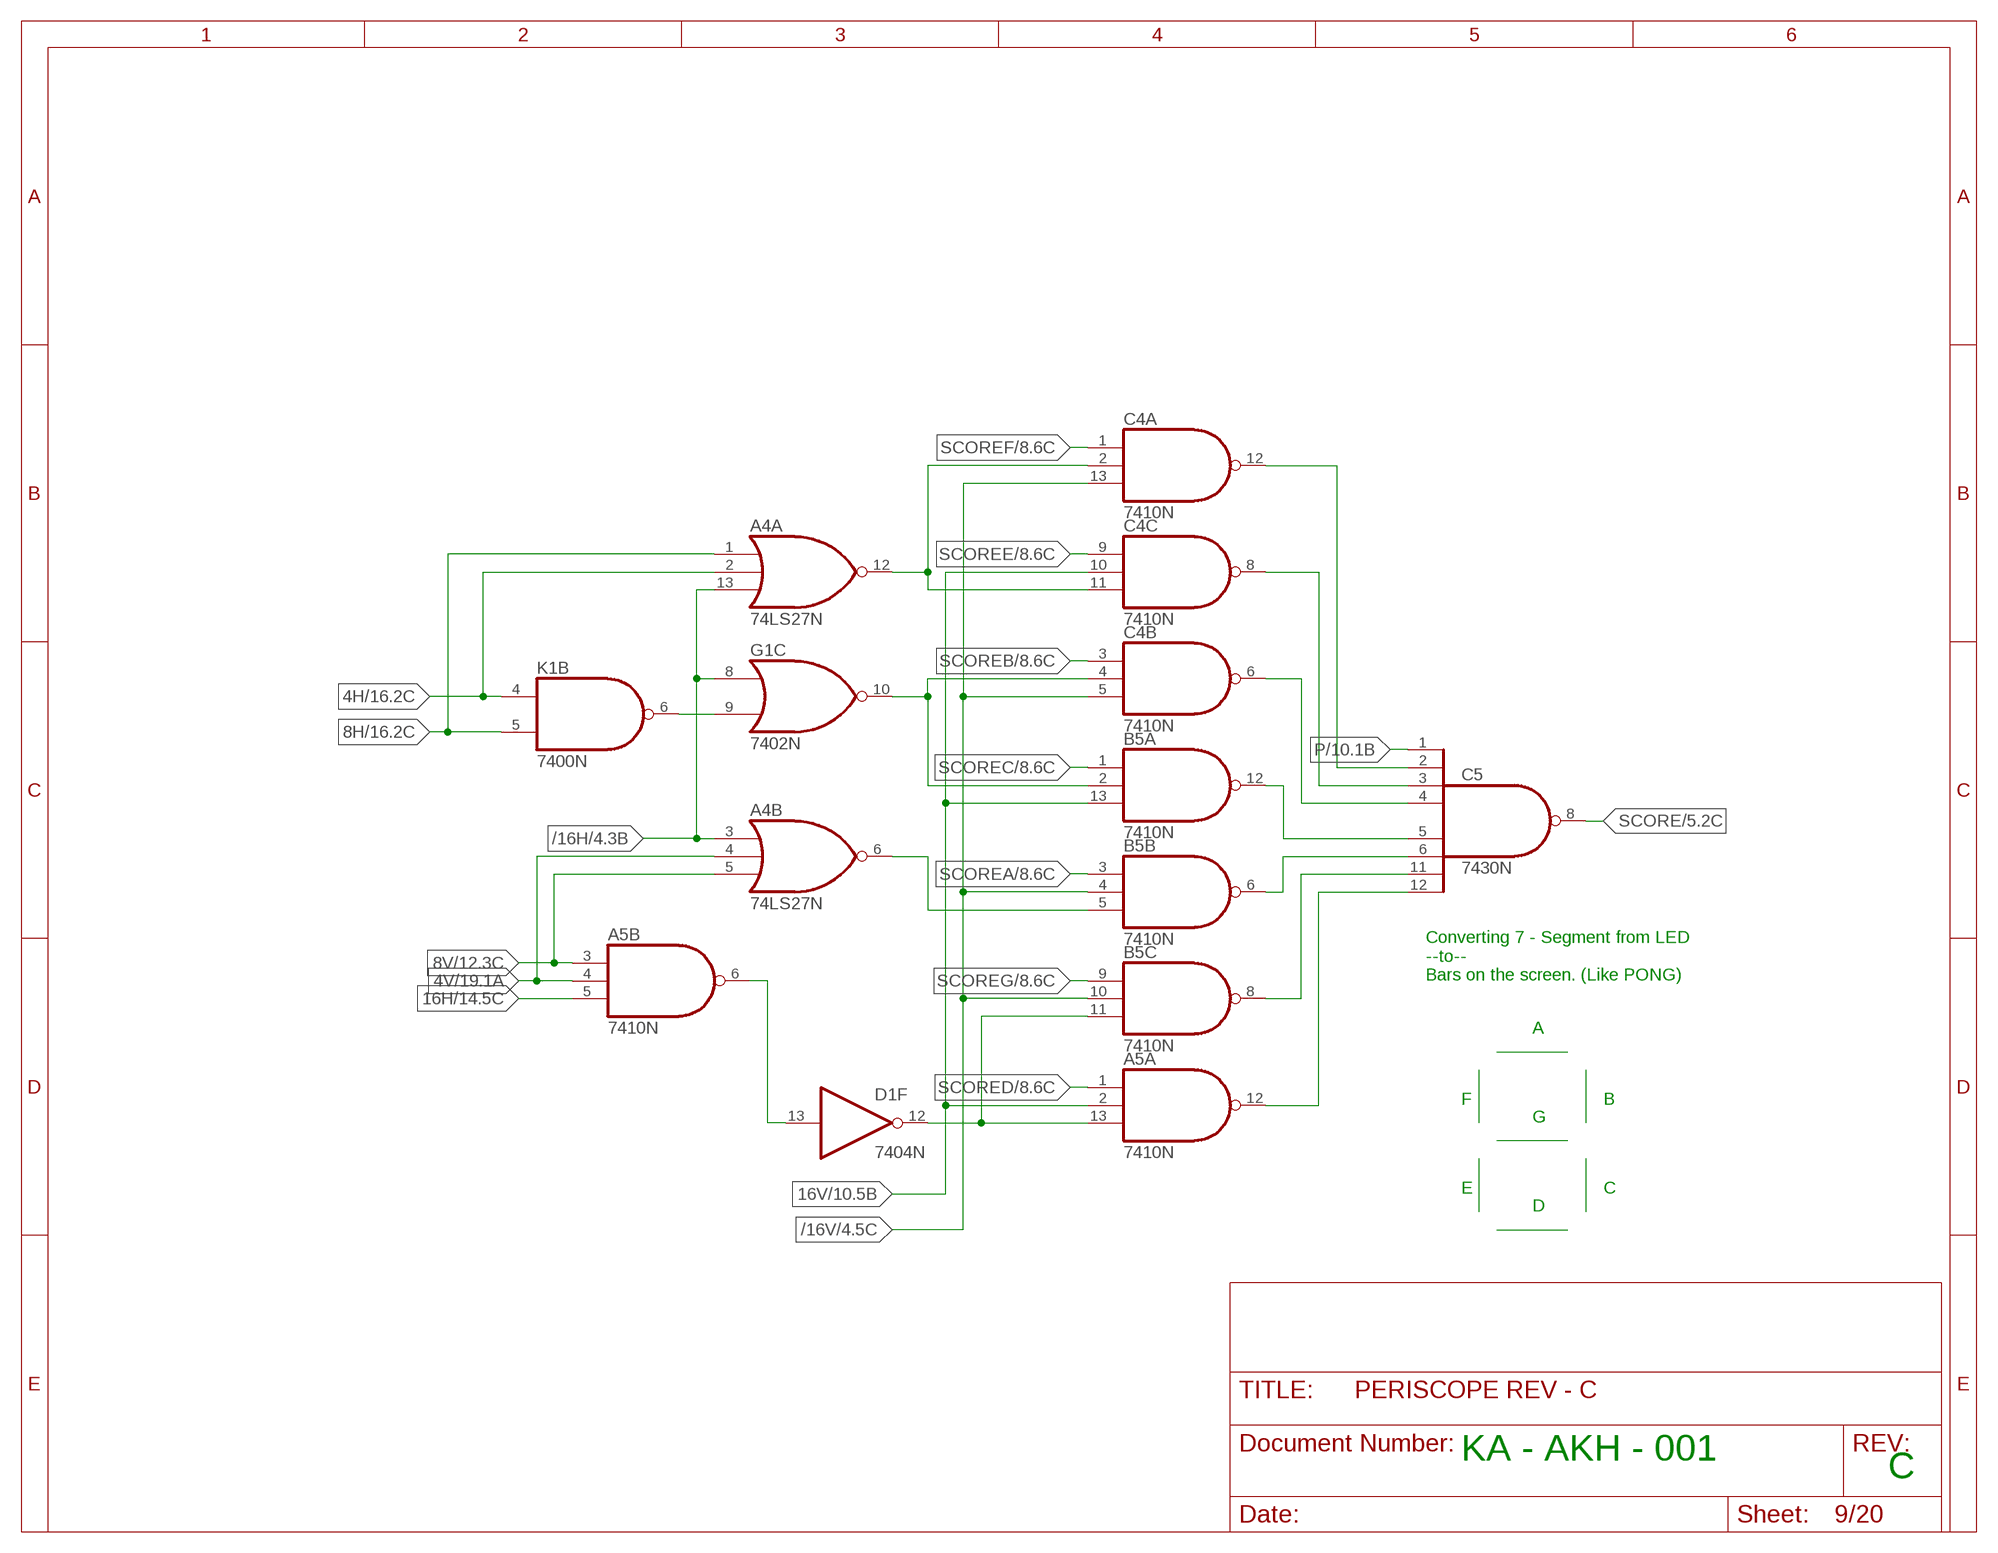
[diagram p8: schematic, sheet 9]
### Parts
A4  74LS27N  [DIL14]
A5  7410N  [DIL14]
B5  7410N  [DIL14]
C4  7410N  [DIL14]
C5  7430N  [DIL14]

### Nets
4H: A4.2(A:I1) K1.4(B:I0) ; also sheet 1,16,17
4V: A4.4(B:I1) A5.4(B:I1) ; also sheet 2,3,4,19
8H: A4.1(A:I0) K1.5(B:I1) ; also sheet 1,16,17,19
8V: A4.5(B:I2) A5.3(B:I0) ; also sheet 2,3,4,12,13
16H: A5.5(B:I2) ; also sheet 1,3,4,8,14
16V: A5.2(A:I1) B5.13(A:I2) C4.10(C:I1) ; also sheet 2,3,4,10,15
/16H: A4.3(B:I0) A4.13(A:I2) G1.8(C:I0) ; also sheet 4
/16V: B5.4(B:I1) B5.10(C:I1) C4.5(B:I2) C4.13(A:I2) ; also sheet 4,5
N$10: A4.12(A:O) C4.2(A:I1) C4.11(C:I2)
N$127: A5.6(B:O) D1.13(F:I)
N$147: C4.12(A:O) C5.2(I1)
N$148: C4.8(C:O) C5.3(I2)
N$149: C4.6(B:O) C5.4(I3)
N$150: B5.12(A:O) C5.5(I4)
N$151: B5.6(B:O) C5.6(I5)
N$152: B5.8(C:O) C5.11(I6)
N$153: A5.12(A:O) C5.12(I7)
N$163: G1.9(C:I1) K1.6(B:O)
N$170: B5.2(A:I1) C4.4(B:I1) G1.10(C:O)
N$174: A4.6(B:O) B5.5(B:I2)
N$177: A5.13(A:I2) B5.11(C:I2) D1.12(F:O)
P: C5.1(I0) ; also sheet 1,2,6,7,8,10,11,14,15,18,19,20
SCORE: C5.8(O) ; also sheet 5
SCOREA: B5.3(B:I0) ; also sheet 8
SCOREB: C4.3(B:I0) ; also sheet 8
SCOREC: B5.1(A:I0) ; also sheet 8
SCORED: A5.1(A:I0) ; also sheet 8
SCOREE: C4.9(C:I0) ; also sheet 8
SCOREF: C4.1(A:I0) ; also sheet 8
SCOREG: B5.9(C:I0) ; also sheet 8

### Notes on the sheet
- Converting 7 - Segment from LED
  --to--
  Bars on the screen. (Like PONG)
- A
- F | B
- G
- E | C
- D
- KA - AKH - 001
- C

## Sheet 10 of 20: FREIGHTER MOTION

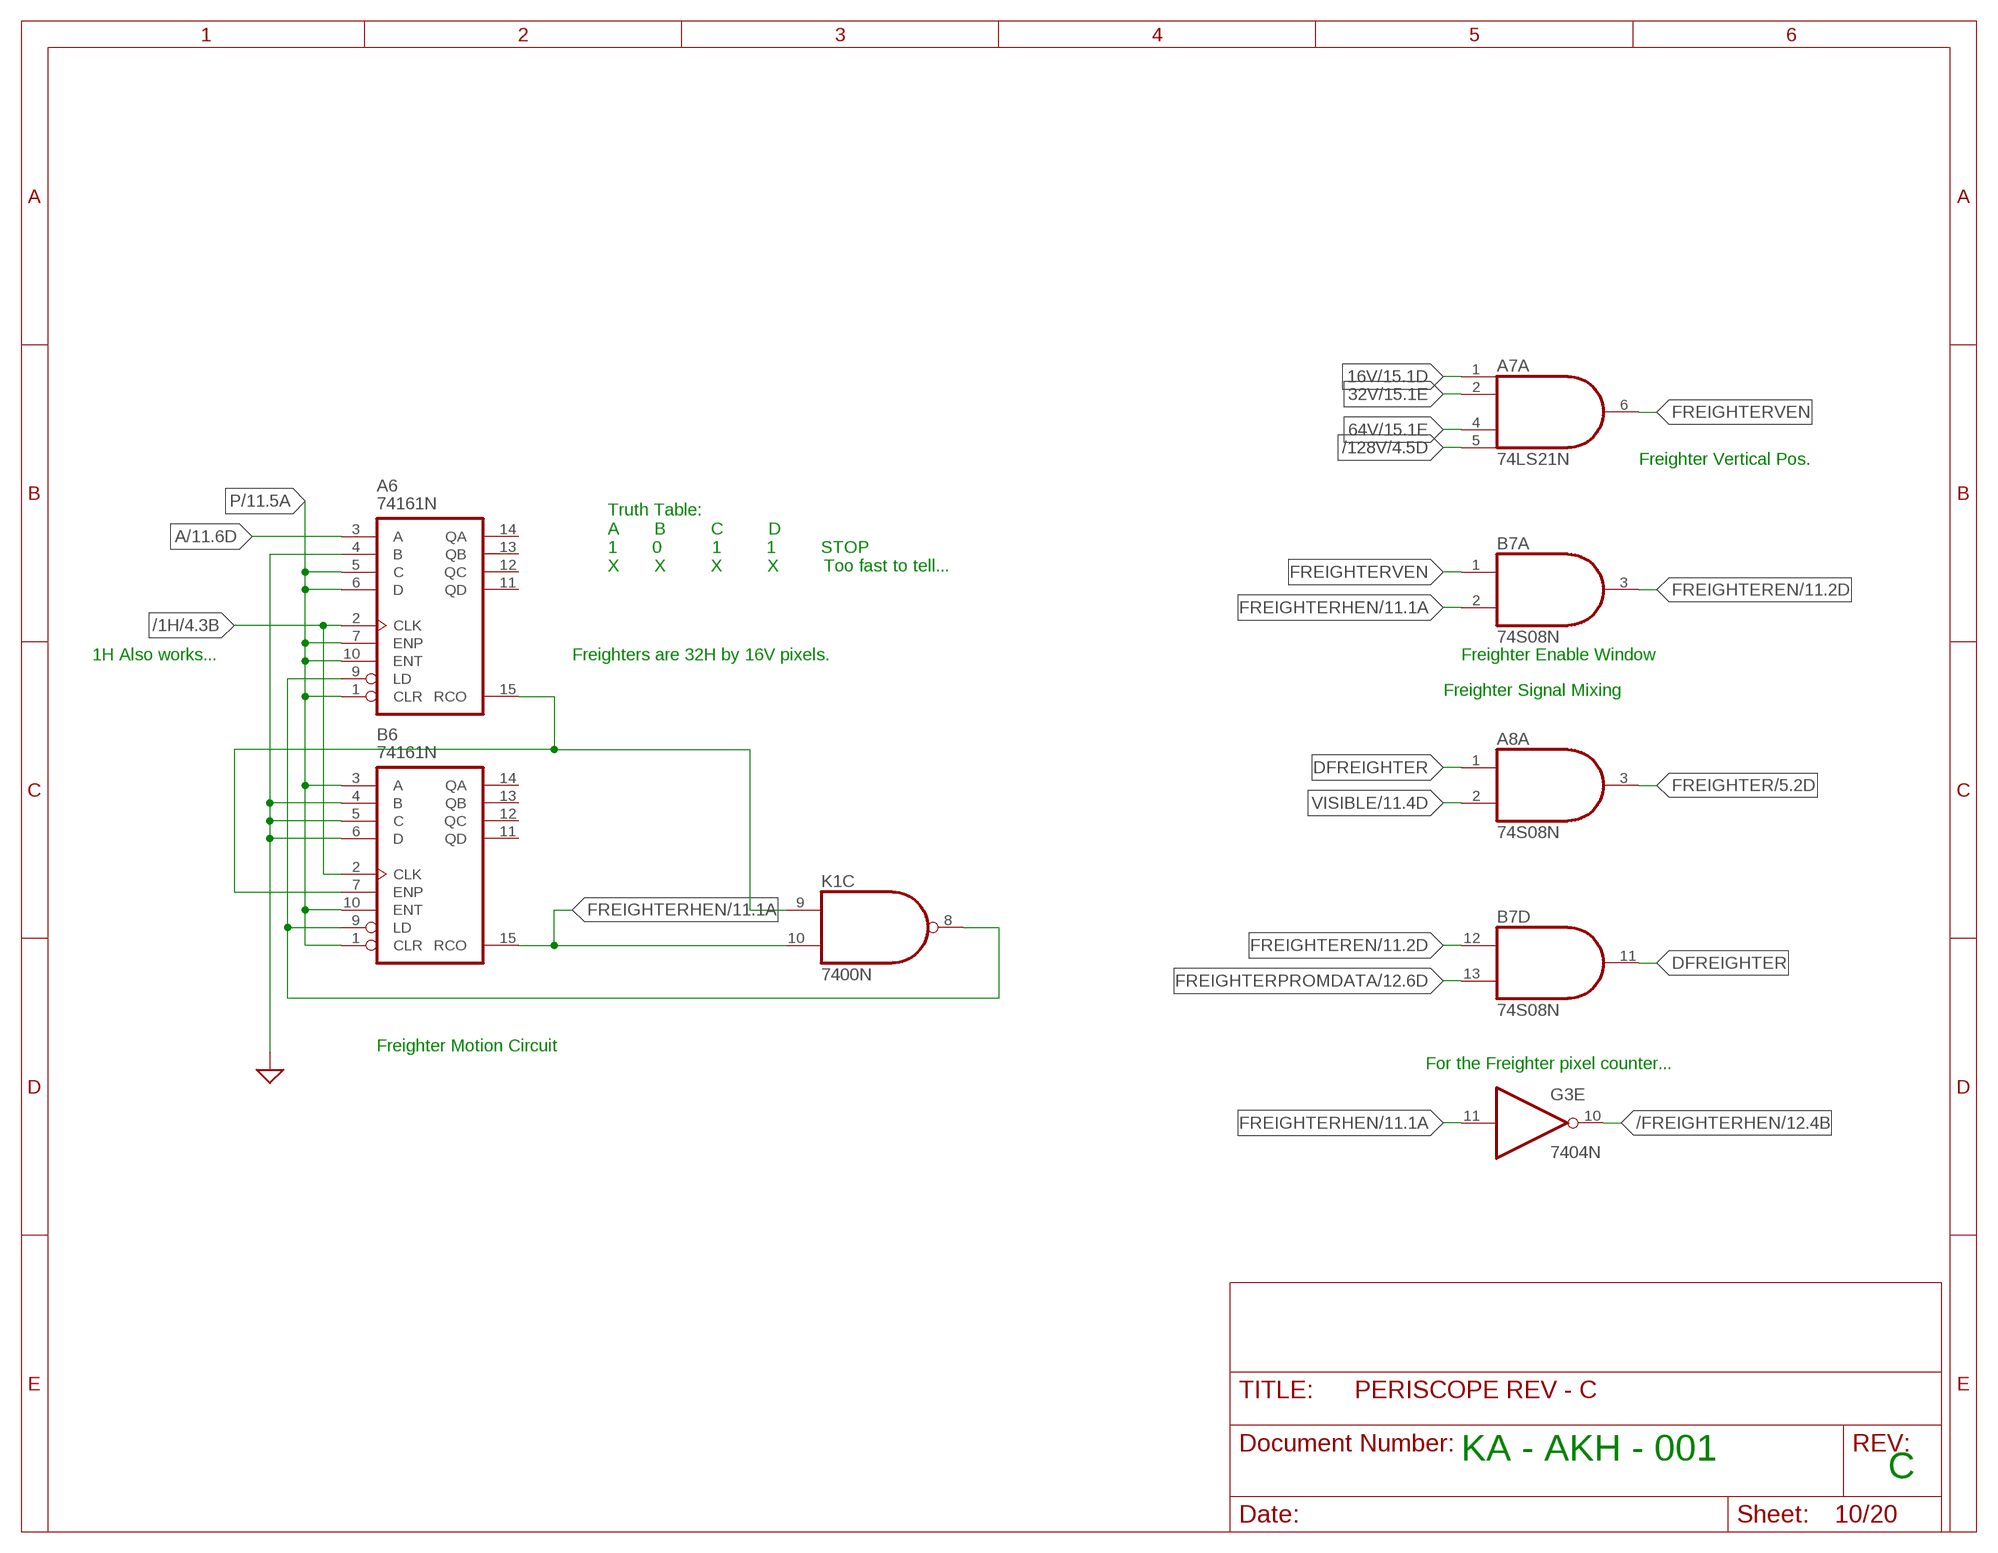
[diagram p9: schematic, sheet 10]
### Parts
A6  74161N  [DIL16]
A7  74LS21N  [DIL14]
A8  74S08N  [DIL14]
B6  74161N  [DIL16]
B7  74S08N  [DIL14]

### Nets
16V: A7.1(A:I0) ; also sheet 2,3,4,9,15
32V: A7.2(A:I1) ; also sheet 2,4,8,15
64V: A7.4(A:I2) ; also sheet 2,4,15
/1H: A6.2(CLK) B6.2(CLK) ; also sheet 4
/128V: A7.5(A:I3) ; also sheet 4,8
/FREIGHTERHEN: G3.10(E:O) ; also sheet 12
A: A6.3(A) ; also sheet 11
DFREIGHTER: A8.1(A:I0) B7.11(D:O)
FREIGHTER: A8.3(A:O) ; also sheet 5
FREIGHTEREN: B7.3(A:O) B7.12(D:I0) ; also sheet 11
FREIGHTERHEN: B6.15(RCO) B7.2(A:I1) G3.11(E:I) K1.10(C:I1) ; also sheet 11
FREIGHTERPROMDATA: B7.13(D:I1) ; also sheet 12
FREIGHTERVEN: A7.6(A:O) B7.1(A:I0)
GND: A6.4(B) B6.4(B) B6.5(C) B6.6(D) ; supply symbol labelled SUP ; also sheet 5,6,7,8,12,13,14,16,17,18,20
N$60: A6.9(LD) B6.9(LD) K1.8(C:O)
N$63: A6.15(RCO) B6.7(ENP) K1.9(C:I0)
P: A6.1(CLR) A6.5(C) A6.6(D) A6.7(ENP) A6.10(ENT) B6.1(CLR) B6.3(A) B6.10(ENT) ; also sheet 1,2,6,7,8,9,11,14,15,18,19,20
VISIBLE: A8.2(A:I1) ; also sheet 11
Unconnected: A6.11(QD) A6.12(QC) A6.13(QB) A6.14(QA) B6.11(QD) B6.12(QC) B6.13(QB) B6.14(QA)

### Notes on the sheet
- Freighter Vertical Pos.
- Truth Table:
  A       B         C         D
  1       0          1         1         STOP
  X       X         X         X         Too fast to tell...
- 1H Also works... | Freighters are 32H by 16V pixels. | Freighter Enable Window
- Freighter Signal Mixing
- Freighter Motion Circuit
- For the Freighter pixel counter...
- KA - AKH - 001
- C

## Sheet 11 of 20: Freighter Control

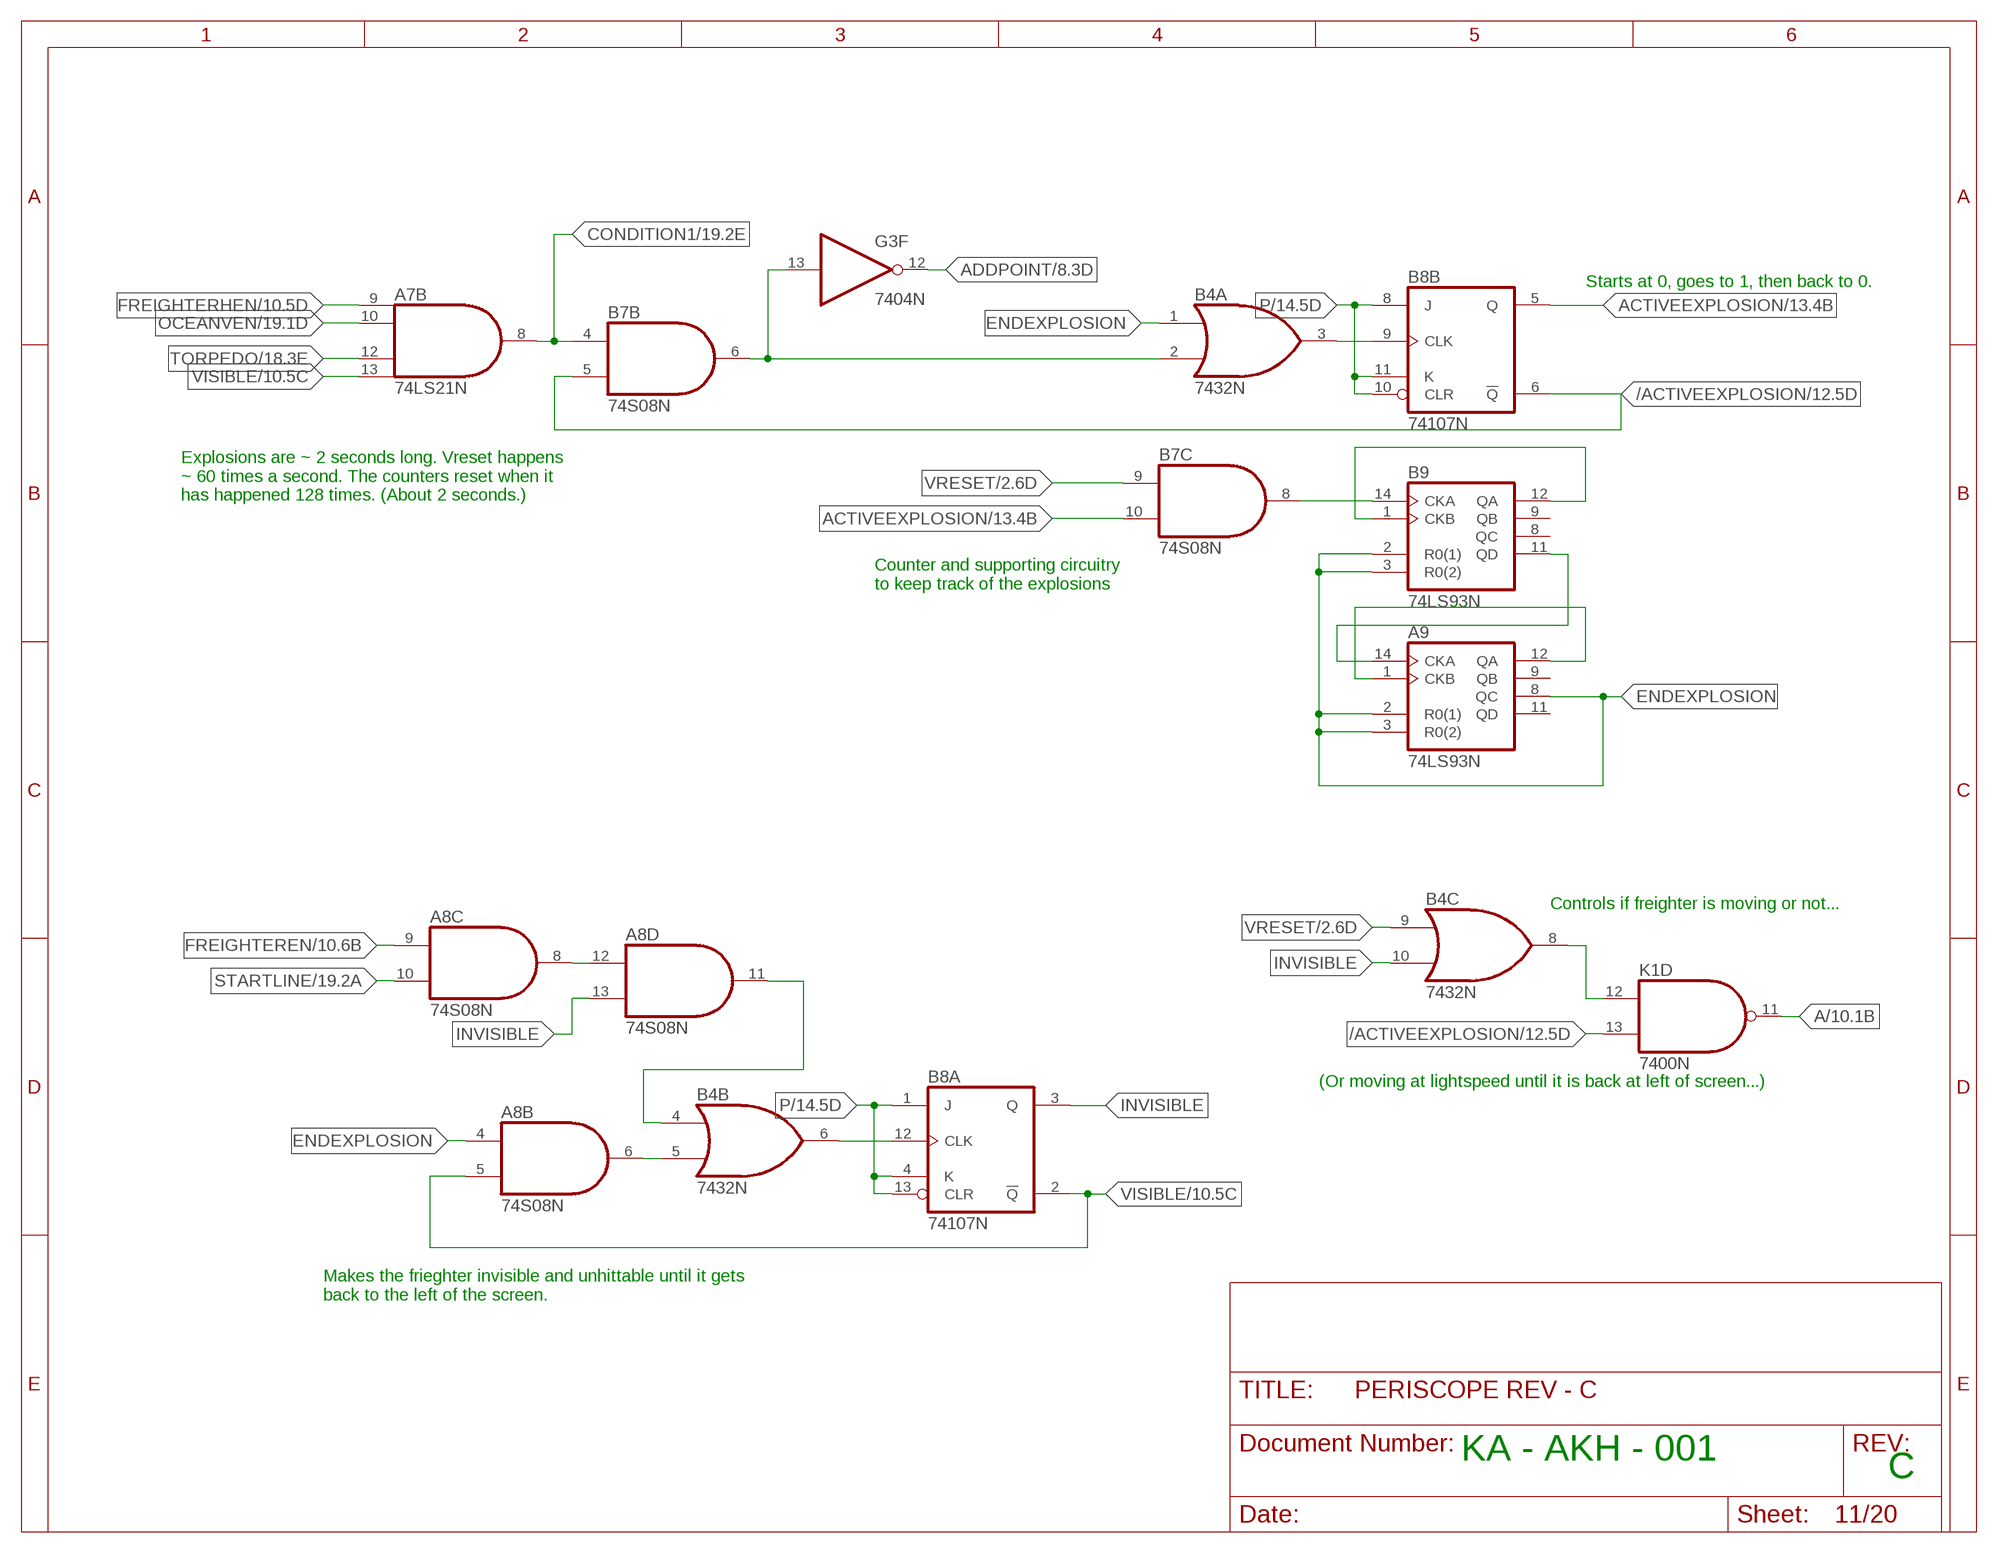
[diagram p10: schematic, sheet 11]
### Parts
A9  74LS93N  [DIL14]
B8  74107N  [DIL14]
B9  74LS93N  [DIL14]

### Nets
/ACTIVEEXPLOSION: B7.5(B:I1) B8.6(B:!Q) K1.13(D:I1) ; also sheet 12
A: K1.11(D:O) ; also sheet 10
ACTIVEEXPLOSION: B7.10(C:I1) B8.5(B:Q) ; also sheet 5,13
ADDPOINT: G3.12(F:O) ; also sheet 8
CONDITION1: A7.8(B:O) B7.4(B:I0) ; also sheet 19
ENDEXPLOSION: A8.4(B:I0) A9.2(R0(1)) A9.3(R0(2)) A9.8(QC) B4.1(A:I0) B9.2(R0(1)) B9.3(R0(2))
FREIGHTEREN: A8.9(C:I0) ; also sheet 10
FREIGHTERHEN: A7.9(B:I0) ; also sheet 10
INVISIBLE: A8.13(D:I1) B4.10(C:I1) B8.3(A:Q)
N$14: B4.6(B:O) B8.12(A:CLK)
N$24: A8.6(B:O) B4.5(B:I1)
N$26: A8.8(C:O) A8.12(D:I0)
N$59: B9.1(CKB) B9.12(QA)
N$62: A9.1(CKB) A9.12(QA)
N$64: B7.8(C:O) B9.14(CKA)
N$67: A9.14(CKA) B9.11(QD)
N$68: B4.3(A:O) B8.9(B:CLK)
N$71: B4.2(A:I1) B7.6(B:O) G3.13(F:I)
N$165: A8.11(D:O) B4.4(B:I0)
N$166: B4.8(C:O) K1.12(D:I0)
OCEANVEN: A7.10(B:I1) ; also sheet 5,19
P: B8.1(A:J) B8.4(A:K) B8.8(B:J) B8.10(B:CLR) B8.11(B:K) B8.13(A:CLR) ; also sheet 1,2,6,7,8,9,10,14,15,18,19,20
STARTLINE: A8.10(C:I1) ; also sheet 19
TORPEDO: A7.12(B:I2) ; also sheet 5,18,19
VISIBLE: A7.13(B:I3) A8.5(B:I1) B8.2(A:!Q) ; also sheet 10
VRESET: B4.9(C:I0) B7.9(C:I0) ; also sheet 2,3
Unconnected: A9.9(QB) A9.11(QD) B9.8(QC) B9.9(QB)

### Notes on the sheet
- Starts at 0, goes to 1, then back to 0.
- Explosions are ~ 2 seconds long. Vreset happens
  ~ 60 times a second. The counters reset when it
  has happened 128 times. (About 2 seconds.)
- Counter and supporting circuitry
  to keep track of the explosions
- Controls if freighter is moving or not...
- (Or moving at lightspeed until it is back at left of screen...)
- Makes the frieghter invisible and unhittable until it gets
  back to the left of the screen.
- KA - AKH - 001
- C

## Sheet 12 of 20: Freighter Regular Graphic

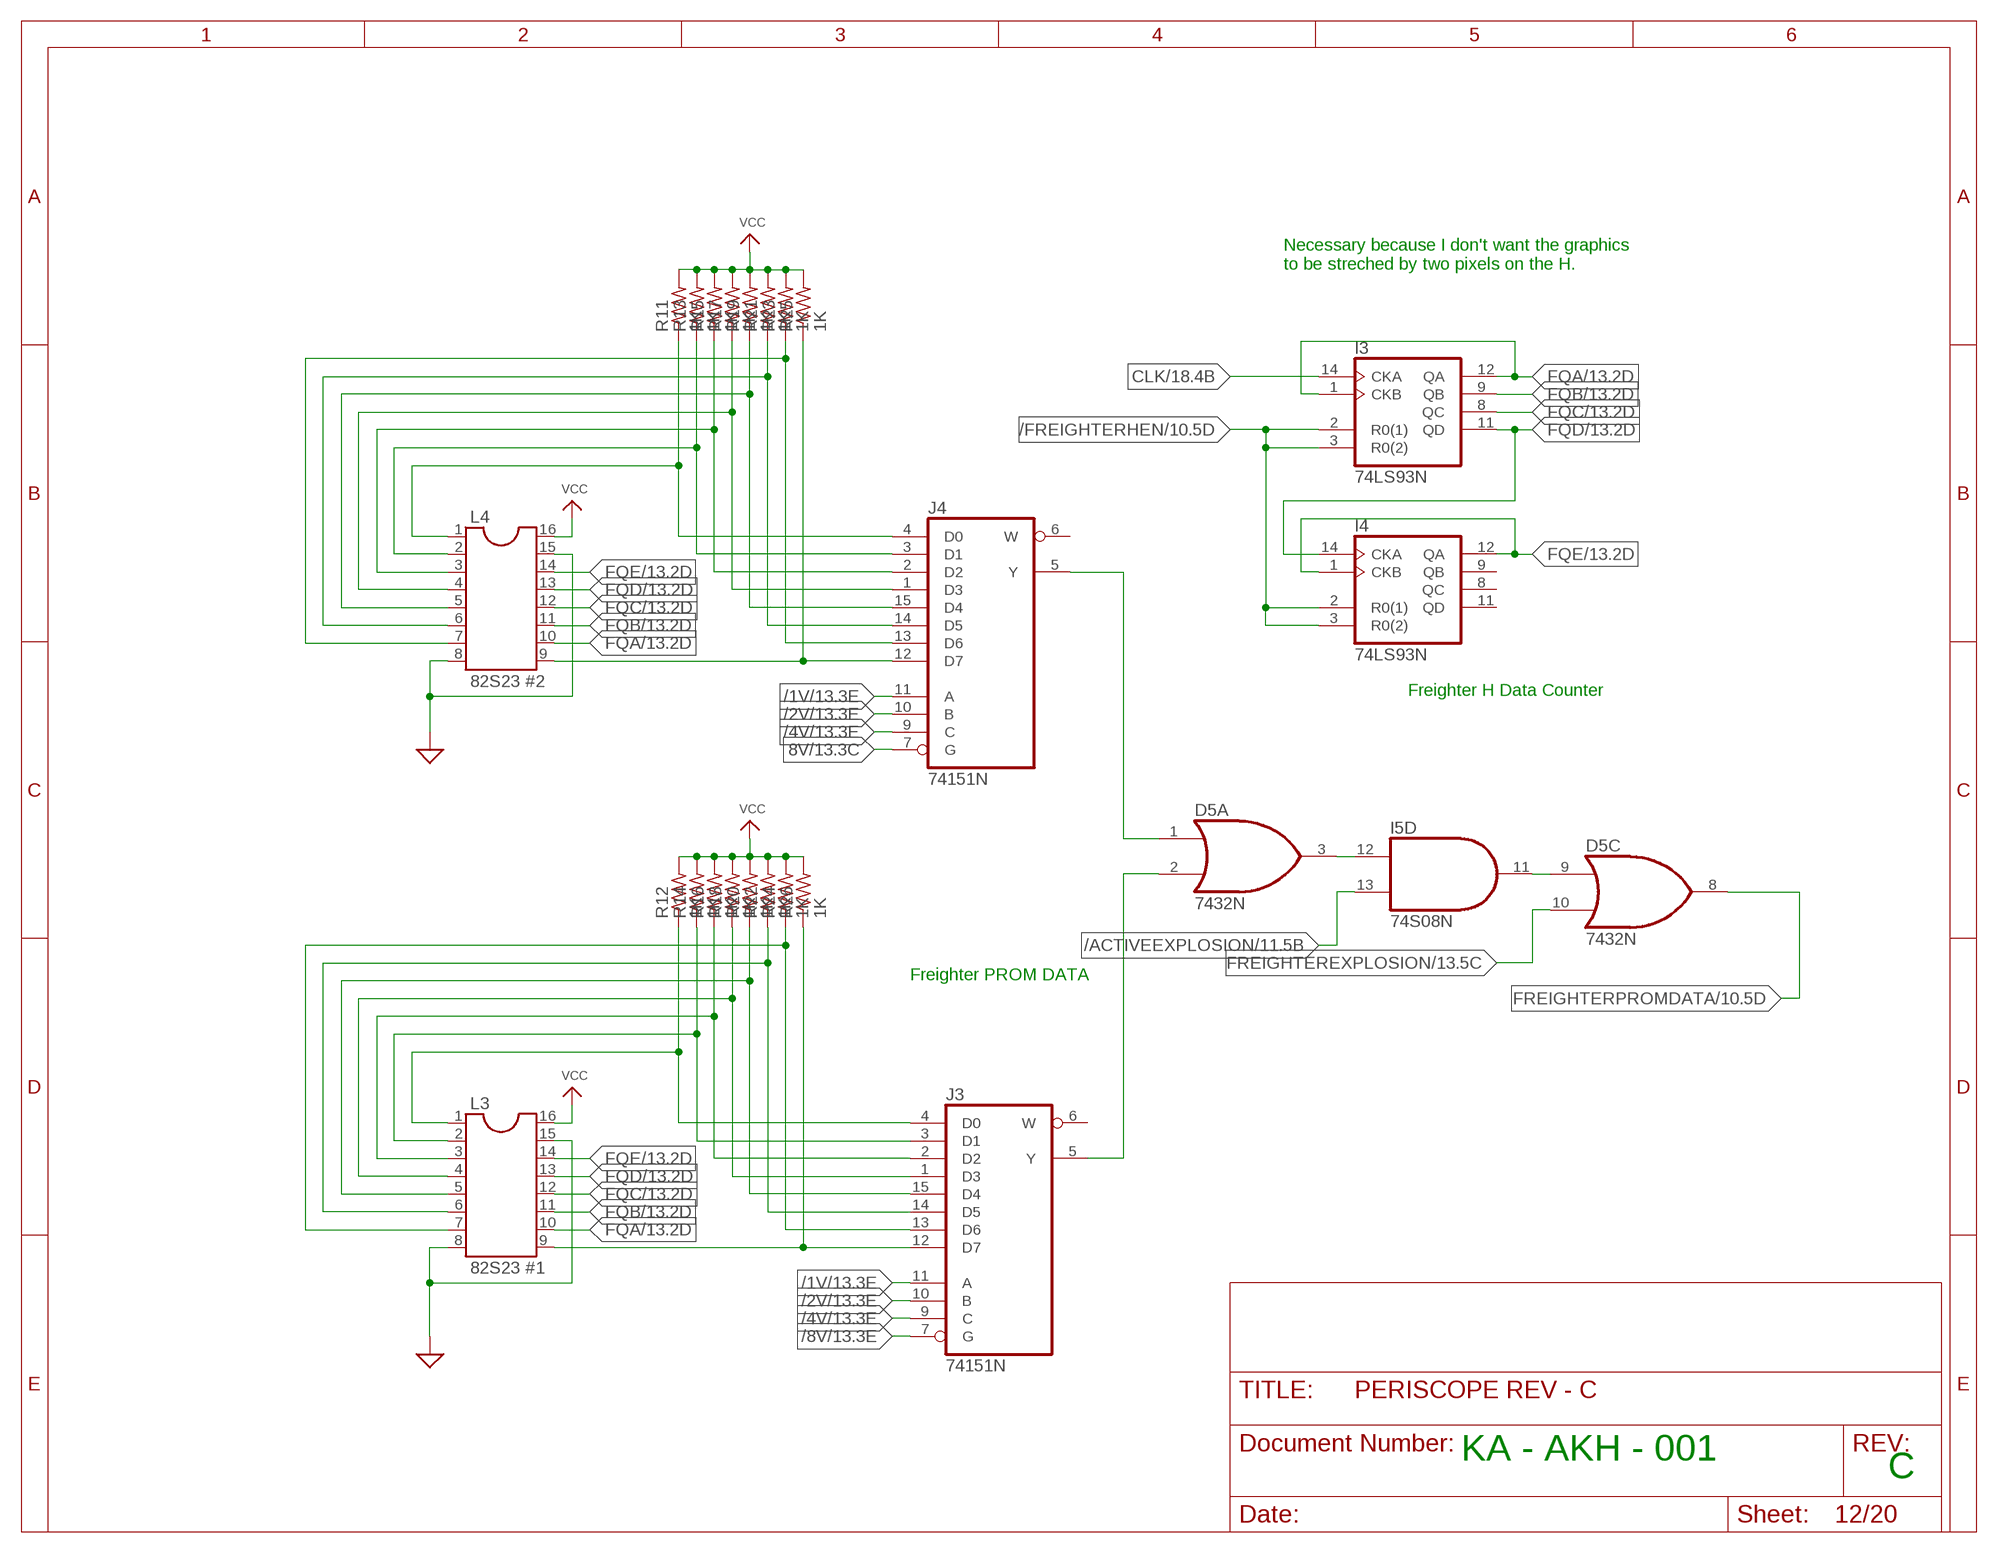
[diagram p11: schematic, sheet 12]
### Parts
I3  74LS93N  [DIL14]
I4  74LS93N  [DIL14]
I5  74S08N  [DIL14]
J3  74151N  [DIL16]
J4  74151N  [DIL16]
L3  82S23 #1  DIL16S  [SOCKET-16]
L4  82S23 #2  DIL16S  [SOCKET-16]
R11  1K  R-US_0207/10  [0207/10]
R12  1K  R-US_0207/10  [0207/10]
R13  1K  R-US_0207/10  [0207/10]
R14  1K  R-US_0207/10  [0207/10]
R15  1K  R-US_0207/10  [0207/10]
R16  1K  R-US_0207/10  [0207/10]
R17  1K  R-US_0207/10  [0207/10]
R18  1K  R-US_0207/10  [0207/10]
R19  1K  R-US_0207/10  [0207/10]
R20  1K  R-US_0207/10  [0207/10]
R21  1K  R-US_0207/10  [0207/10]
R22  1K  R-US_0207/10  [0207/10]
R23  1K  R-US_0207/10  [0207/10]
R24  1K  R-US_0207/10  [0207/10]
R25  1K  R-US_0207/10  [0207/10]
R26  1K  R-US_0207/10  [0207/10]

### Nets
8V: J4.7(G) ; also sheet 2,3,4,9,13
/1V: J3.11(A) J4.11(A) ; also sheet 4,5,13
/2V: J3.10(B) J4.10(B) ; also sheet 4,5,13
/4V: J3.9(C) J4.9(C) ; also sheet 4,5,13
/8V: J3.7(G) ; also sheet 4,5,13
/ACTIVEEXPLOSION: I5.13(D:I1) ; also sheet 11
/FREIGHTERHEN: I3.2(R0(1)) I3.3(R0(2)) I4.2(R0(1)) I4.3(R0(2)) ; also sheet 10
CLK: I3.14(CKA) ; also sheet 1,18
FQA: I3.1(CKB) I3.12(QA) L3.10 L4.10 ; also sheet 13
FQB: I3.9(QB) L3.11 L4.11 ; also sheet 13
FQC: I3.8(QC) L3.12 L4.12 ; also sheet 13
FQD: I3.11(QD) I4.14(CKA) L3.13 L4.13 ; also sheet 13
FQE: I4.1(CKB) I4.12(QA) L3.14 L4.14 ; also sheet 13
FREIGHTEREXPLOSION: D5.10(C:I1) ; also sheet 13
FREIGHTERPROMDATA: D5.8(C:O) ; also sheet 10
GND: L3.8 L3.15 L4.8 L4.15 ; supply symbol labelled SUP ; also sheet 5,6,7,8,10,13,14,16,17,18,20
N$27: J3.4(D0) L3.1 R12.1
N$31: J3.3(D1) L3.2 R14.1
N$36: J3.2(D2) L3.3 R16.1
N$37: J3.1(D3) L3.4 R18.1
N$40: J3.15(D4) L3.5 R20.1
N$41: J3.14(D5) L3.6 R22.1
N$42: J4.12(D7) L4.9 R25.1
N$43: J4.13(D6) L4.7 R23.1
N$44: J4.14(D5) L4.6 R21.1
N$45: J4.15(D4) L4.5 R19.1
N$46: J4.2(D2) L4.3 R15.1
N$47: J4.3(D1) L4.2 R13.1
N$48: J4.4(D0) L4.1 R11.1
N$49: D5.1(A:I0) J4.5(Y)
N$50: D5.2(A:I1) J3.5(Y)
N$54: D5.9(C:I0) I5.11(D:O)
N$58: D5.3(A:O) I5.12(D:I0)
N$110: J3.13(D6) L3.7 R24.1
N$111: J3.12(D7) L3.9 R26.1
N$124: J4.1(D3) L4.4 R17.1
VCC: L3.16 L4.16 R11.2 R12.2 R13.2 R14.2 R15.2 R16.2 R17.2 R18.2 R19.2 R20.2 R21.2 R22.2 R23.2 R24.2 R25.2 R26.2 ; also sheet 6,7,8,13,15,16,17,18,20
Unconnected: I4.8(QC) I4.9(QB) I4.11(QD) J3.6(W) J4.6(W)

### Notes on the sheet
- Necessary because I don't want the graphics
  to be streched by two pixels on the H.
- Freighter H Data Counter
- Freighter PROM DATA
- KA - AKH - 001
- C

## Sheet 13 of 20: Freighter BOOM Graphic

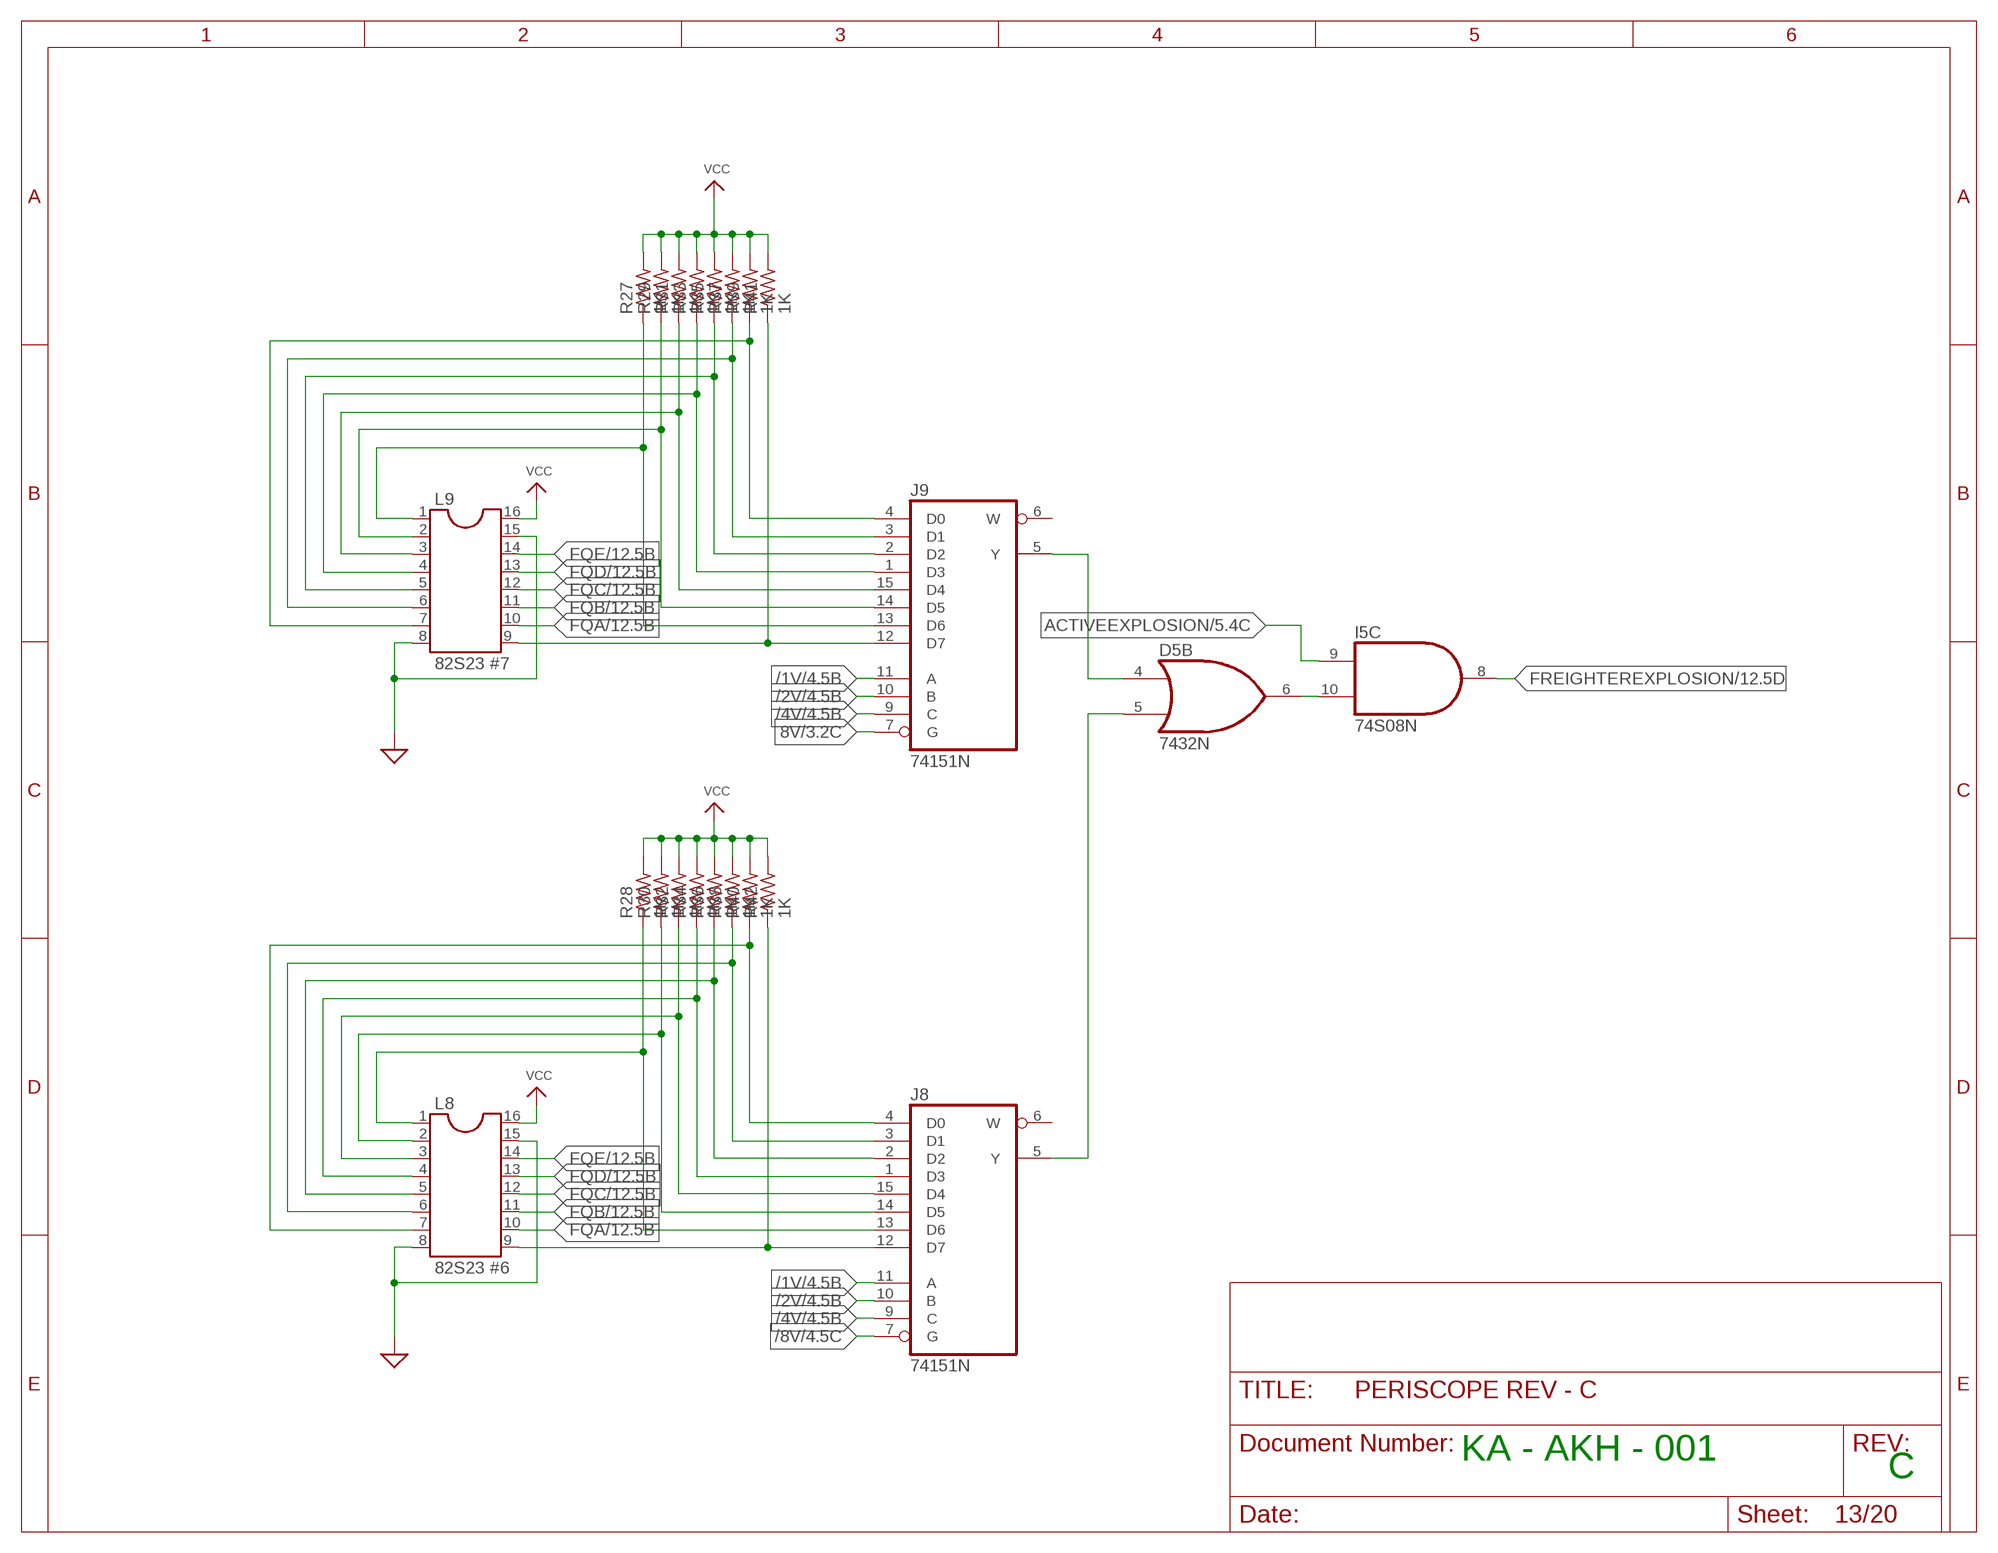
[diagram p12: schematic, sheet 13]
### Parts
J8  74151N  [DIL16]
J9  74151N  [DIL16]
L8  82S23 #6  DIL16S  [SOCKET-16]
L9  82S23 #7  DIL16S  [SOCKET-16]
R27  1K  R-US_0207/10  [0207/10]
R28  1K  R-US_0207/10  [0207/10]
R29  1K  R-US_0207/10  [0207/10]
R30  1K  R-US_0207/10  [0207/10]
R31  1K  R-US_0207/10  [0207/10]
R32  1K  R-US_0207/10  [0207/10]
R33  1K  R-US_0207/10  [0207/10]
R34  1K  R-US_0207/10  [0207/10]
R35  1K  R-US_0207/10  [0207/10]
R36  1K  R-US_0207/10  [0207/10]
R37  1K  R-US_0207/10  [0207/10]
R38  1K  R-US_0207/10  [0207/10]
R39  1K  R-US_0207/10  [0207/10]
R40  1K  R-US_0207/10  [0207/10]
R41  1K  R-US_0207/10  [0207/10]
R42  1K  R-US_0207/10  [0207/10]

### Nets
8V: J9.7(G) ; also sheet 2,3,4,9,12
/1V: J8.11(A) J9.11(A) ; also sheet 4,5,12
/2V: J8.10(B) J9.10(B) ; also sheet 4,5,12
/4V: J8.9(C) J9.9(C) ; also sheet 4,5,12
/8V: J8.7(G) ; also sheet 4,5,12
ACTIVEEXPLOSION: I5.9(C:I0) ; also sheet 5,11
FQA: L8.10 L9.10 ; also sheet 12
FQB: L8.11 L9.11 ; also sheet 12
FQC: L8.12 L9.12 ; also sheet 12
FQD: L8.13 L9.13 ; also sheet 12
FQE: L8.14 L9.14 ; also sheet 12
FREIGHTEREXPLOSION: I5.8(C:O) ; also sheet 12
GND: L8.8 L8.15 L9.8 L9.15 ; supply symbol labelled SUP ; also sheet 5,6,7,8,10,12,14,16,17,18,20
N$52: D5.4(B:I0) J9.5(Y)
N$53: D5.5(B:I1) J8.5(Y)
N$56: D5.6(B:O) I5.10(C:I1)
N$61: J8.12(D7) L8.9 R42.1
N$65: J9.12(D7) L9.9 R41.1
N$66: J9.13(D6) L9.1 R27.1
N$72: J9.14(D5) L9.2 R29.1
N$73: J9.15(D4) L9.3 R31.1
N$74: J9.1(D3) L9.4 R33.1
N$75: J9.2(D2) L9.5 R35.1
N$76: J9.3(D1) L9.6 R37.1
N$77: J8.3(D1) L8.6 R38.1
N$157: J9.4(D0) L9.7 R39.1
N$158: J8.13(D6) L8.1 R28.1
N$159: J8.14(D5) L8.2 R30.1
N$160: J8.15(D4) L8.3 R32.1
N$161: J8.1(D3) L8.4 R34.1
N$162: J8.2(D2) L8.5 R36.1
N$164: J8.4(D0) L8.7 R40.1
VCC: L8.16 L9.16 R27.2 R28.2 R29.2 R30.2 R31.2 R32.2 R33.2 R34.2 R35.2 R36.2 R37.2 R38.2 R39.2 R40.2 R41.2 R42.2 ; also sheet 6,7,8,12,15,16,17,18,20
Unconnected: J8.6(W) J9.6(W)

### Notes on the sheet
- KA - AKH - 001
- C

## Sheet 14 of 20: SUBMARINE MOTION

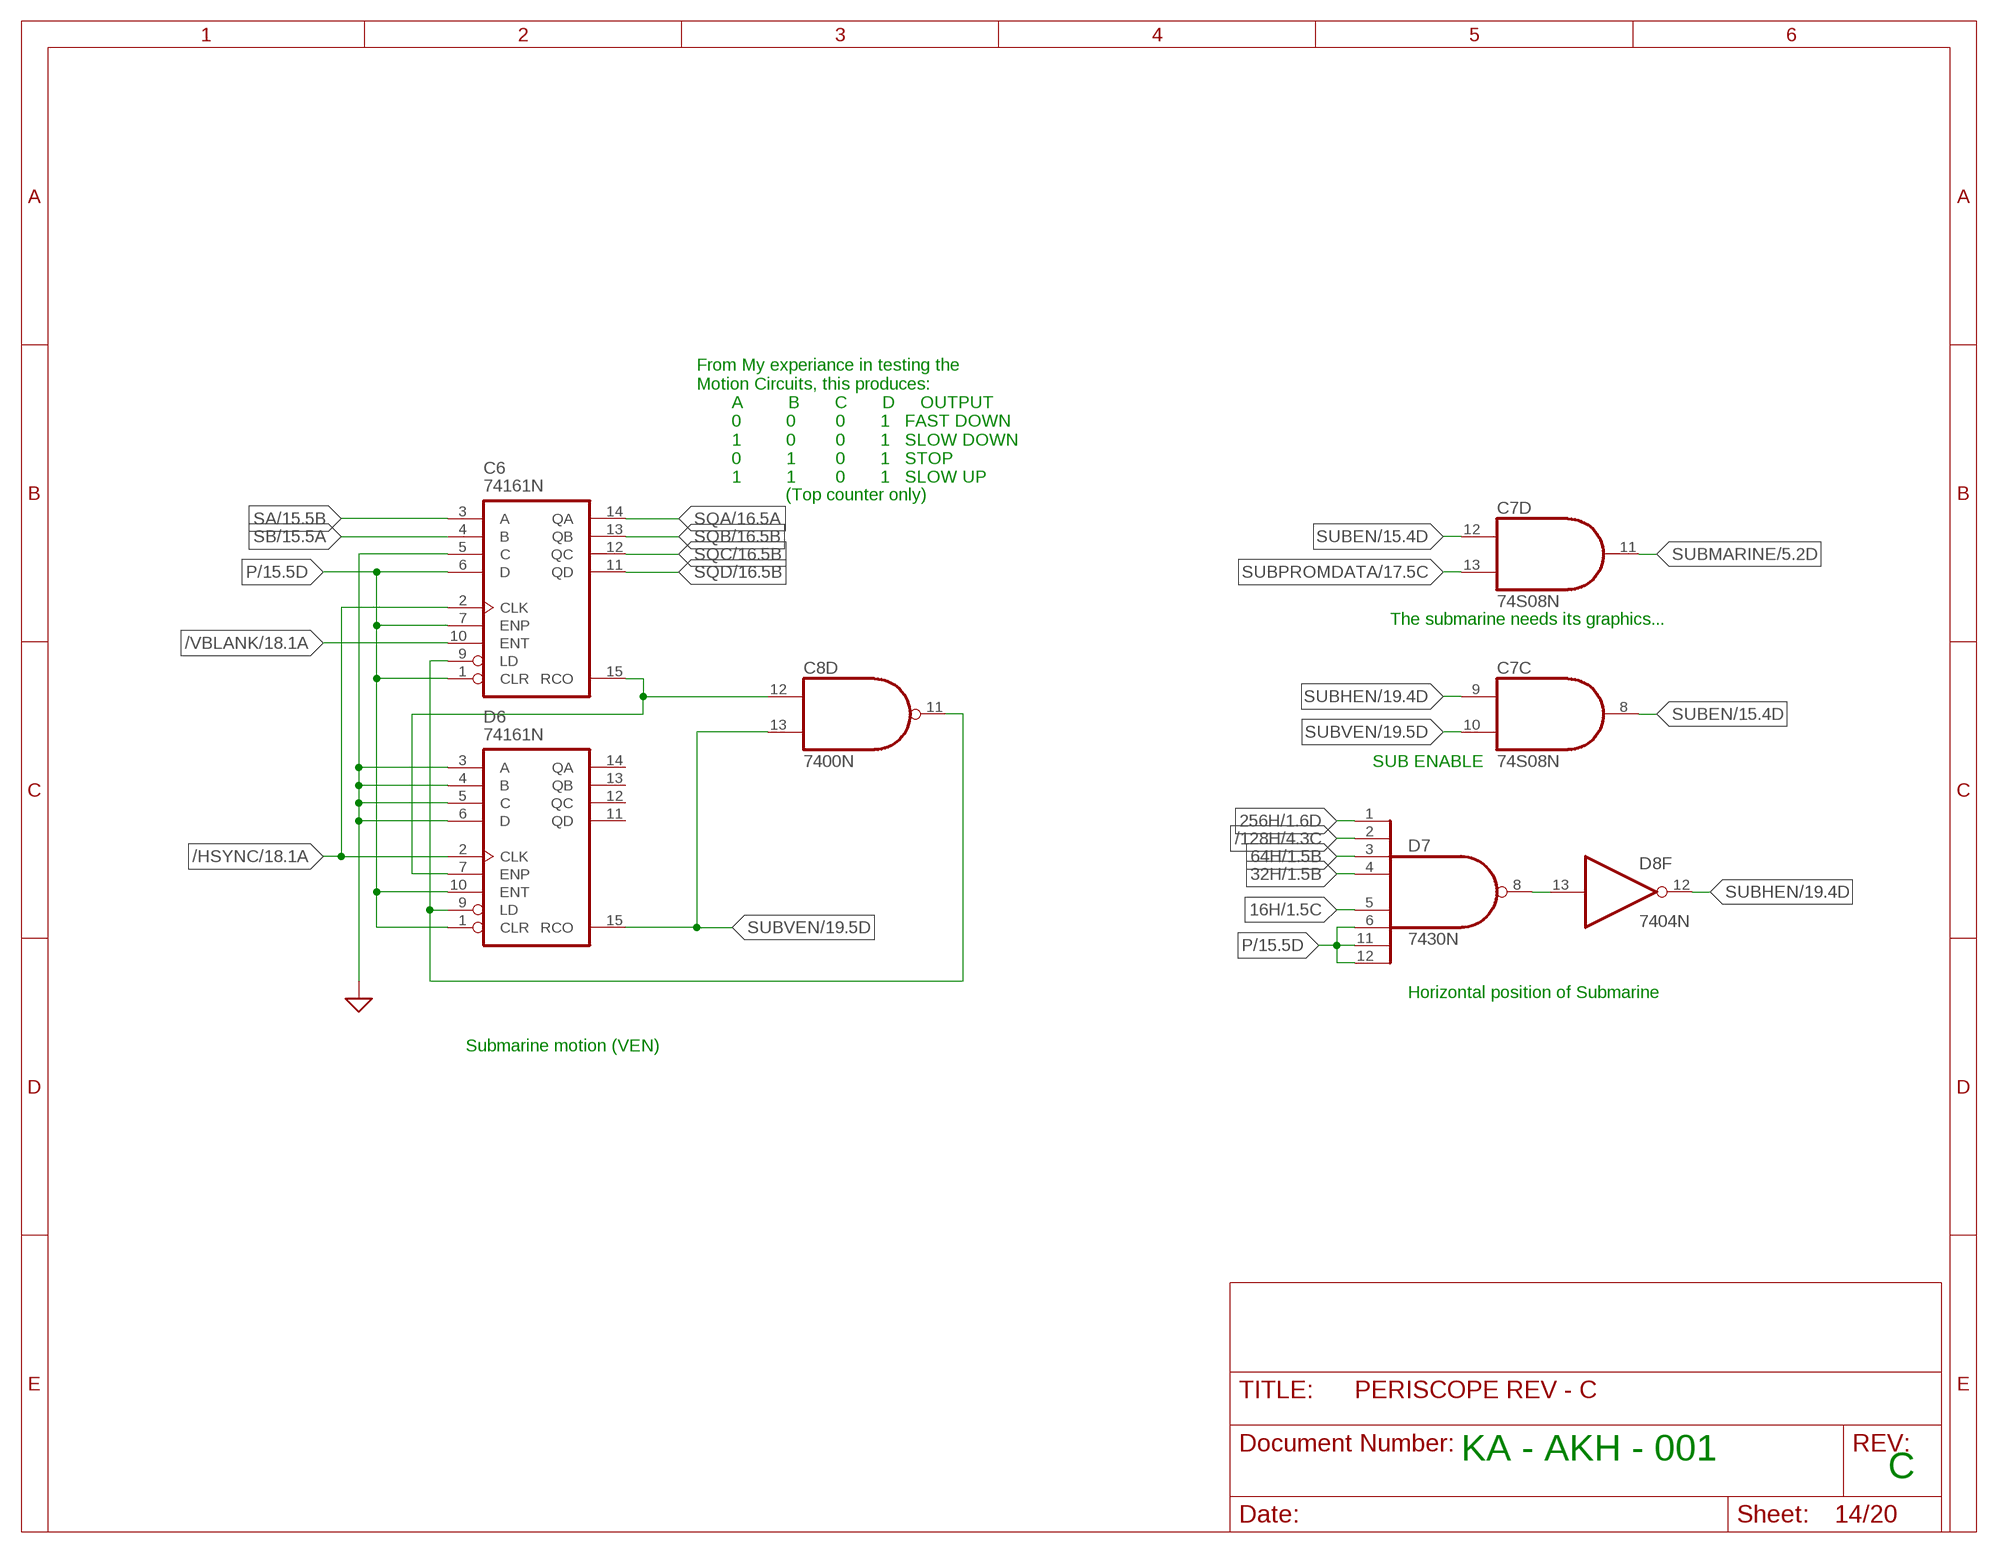
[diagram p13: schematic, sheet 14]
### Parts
C6  74161N  [DIL16]
C7  74S08N  [DIL14]
C8  7400N  [DIL14]
D6  74161N  [DIL16]
D7  7430N  [DIL14]
D8  7404N  [DIL14]

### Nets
16H: D7.5(I4) ; also sheet 1,3,4,8,9
32H: D7.4(I3) ; also sheet 1,3,4,8
64H: D7.3(I2) ; also sheet 1,3,4,8
256H: D7.1(I0) ; also sheet 1,8
/128H: D7.2(I1) ; also sheet 4,8
/HSYNC: C6.2(CLK) D6.2(CLK) ; also sheet 3,18
/VBLANK: C6.10(ENT) ; also sheet 3,18
GND: C6.5(C) D6.3(A) D6.4(B) D6.5(C) D6.6(D) ; supply symbol labelled SUP ; also sheet 5,6,7,8,10,12,13,16,17,18,20
N$80: C6.9(LD) C8.11(D:O) D6.9(LD)
N$81: D7.8(O) D8.13(F:I)
N$173: C6.15(RCO) C8.12(D:I0) D6.7(ENP)
P: C6.1(CLR) C6.6(D) C6.7(ENP) D6.1(CLR) D6.10(ENT) D7.6(I5) D7.11(I6) D7.12(I7) ; also sheet 1,2,6,7,8,9,10,11,15,18,19,20
SA: C6.3(A) ; also sheet 15,16,19
SB: C6.4(B) ; also sheet 15,16,19
SQA: C6.14(QA) ; also sheet 16
SQB: C6.13(QB) ; also sheet 16,19
SQC: C6.12(QC) ; also sheet 16
SQD: C6.11(QD) ; also sheet 16,19
SUBEN: C7.8(C:O) C7.12(D:I0) ; also sheet 15
SUBHEN: C7.9(C:I0) D8.12(F:O) ; also sheet 19
SUBMARINE: C7.11(D:O) ; also sheet 5
SUBPROMDATA: C7.13(D:I1) ; also sheet 17
SUBVEN: C7.10(C:I1) C8.13(D:I1) D6.15(RCO) ; also sheet 19
Unconnected: D6.11(QD) D6.12(QC) D6.13(QB) D6.14(QA)

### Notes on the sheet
- From My experiance in testing the 
  Motion Circuits, this produces:
         A         B       C       D     OUTPUT
         0         0        0       1   FAST DOWN
         1         0        0       1   SLOW DOWN
         0         1        0       1   STOP
         1         1        0       1   SLOW UP
- (Top counter only)
- The submarine needs its graphics...
- SUB ENABLE
- Horizontal position of Submarine
- Submarine motion (VEN)
- KA - AKH - 001
- C

## Sheet 15 of 20: Submarine Control

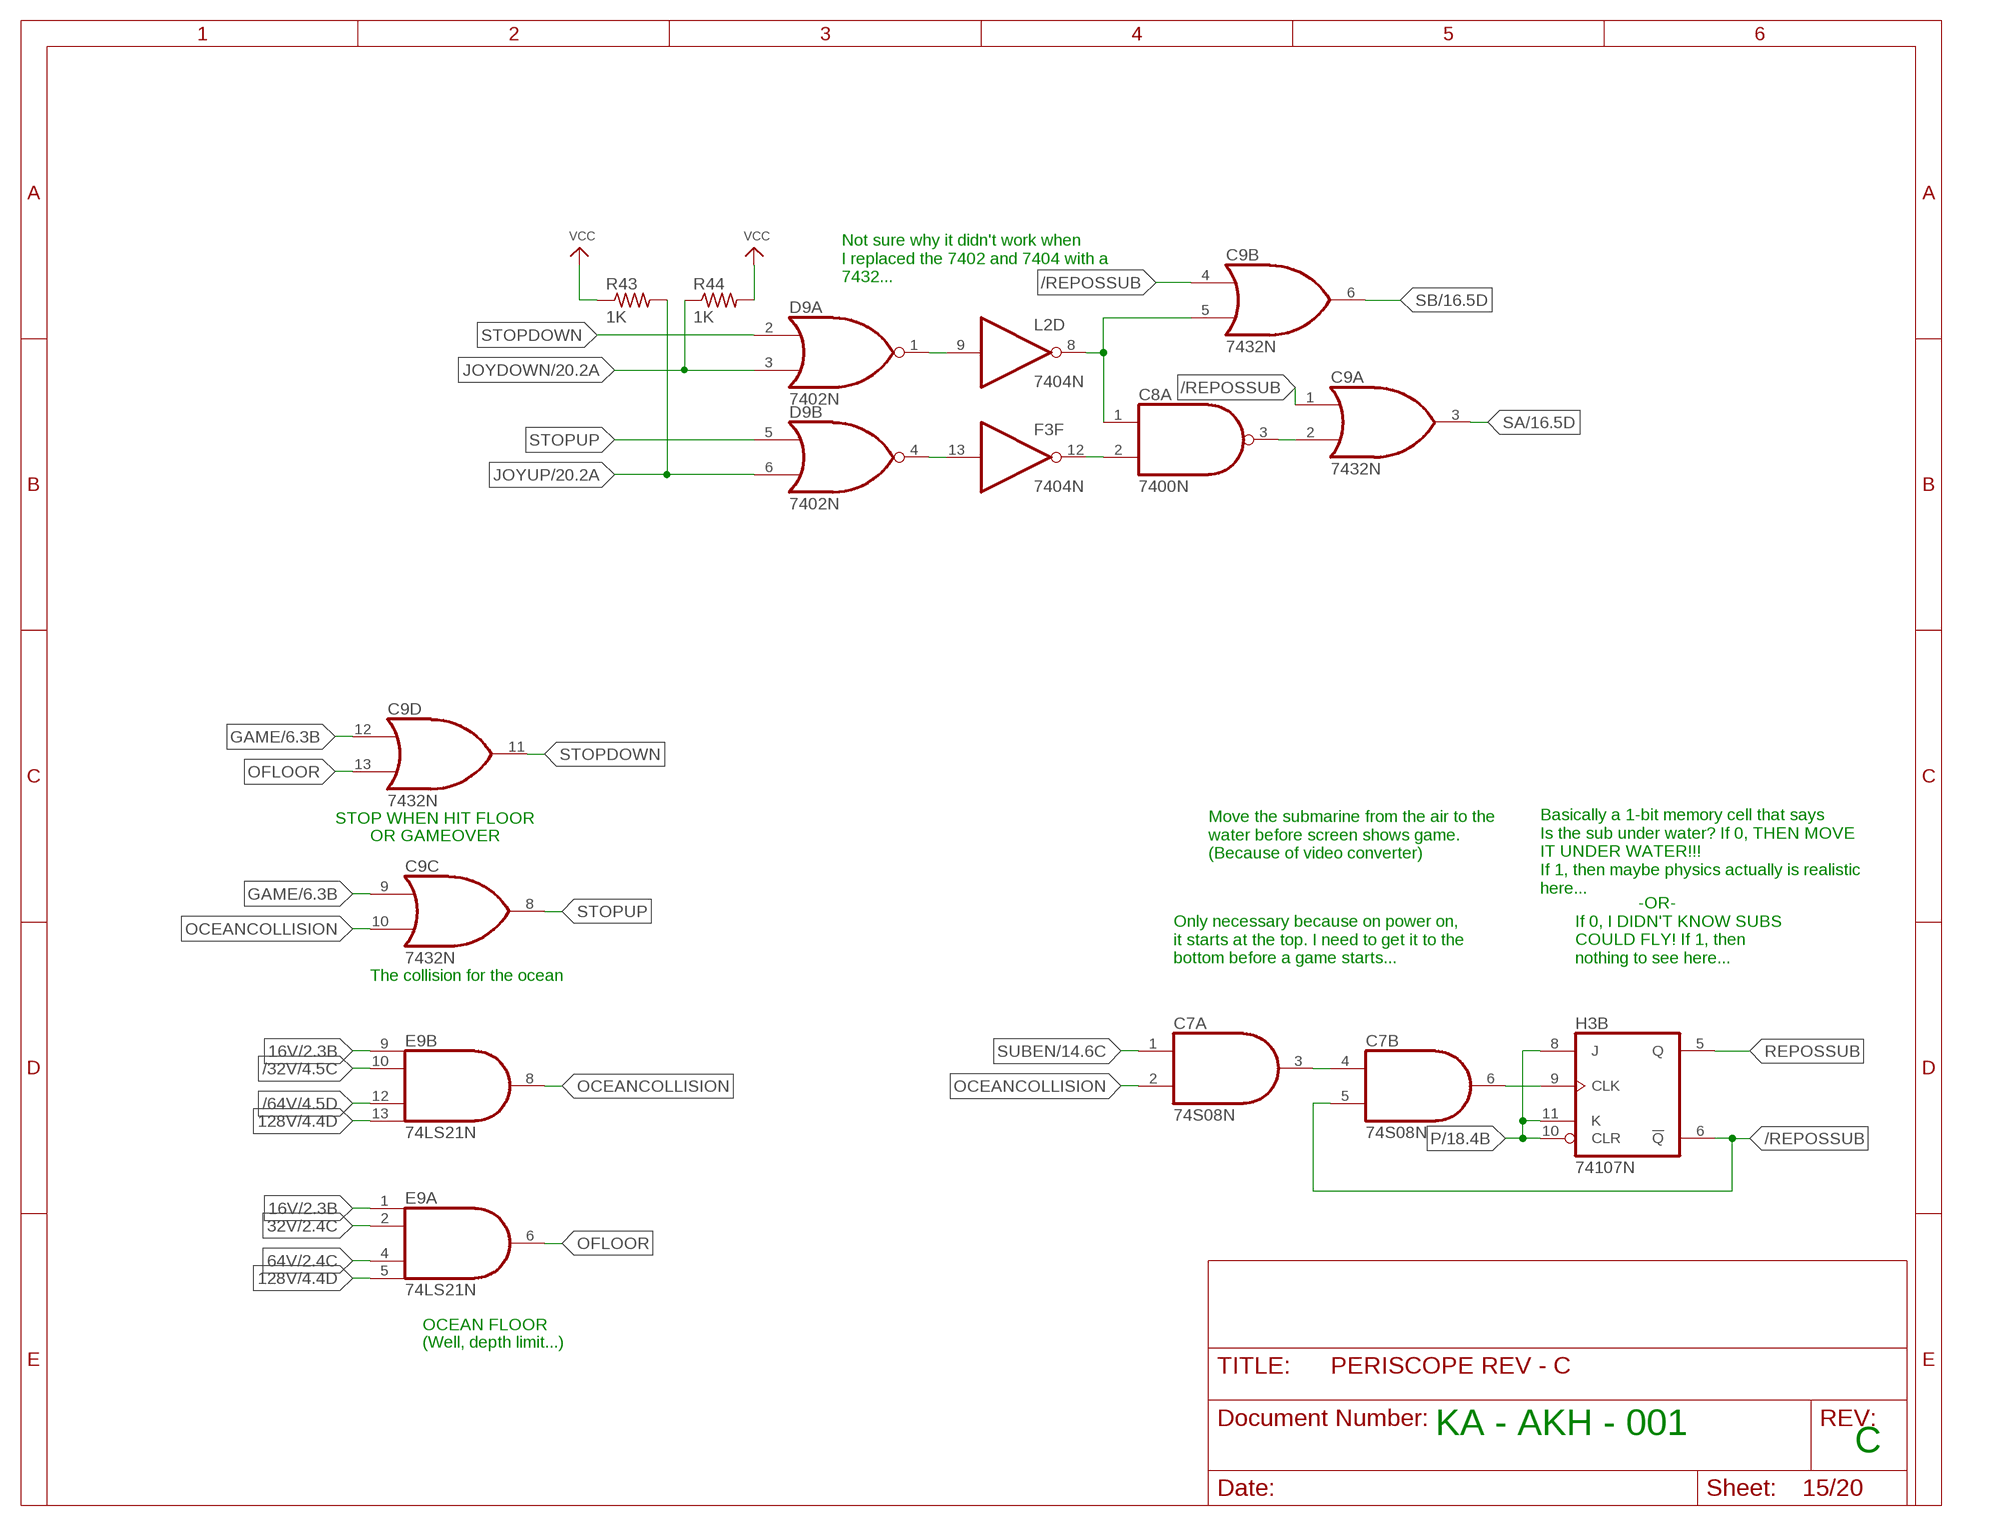
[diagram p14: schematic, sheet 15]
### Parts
C9  7432N  [DIL14]
D9  7402N  [DIL14]
E9  74LS21N  [DIL14]
R43  1K  R-US_0207/10  [0207/10]
R44  1K  R-US_0207/10  [0207/10]

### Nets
16V: E9.1(A:I0) E9.9(B:I0) ; also sheet 2,3,4,9,10
32V: E9.2(A:I1) ; also sheet 2,4,8,10
64V: E9.4(A:I2) ; also sheet 2,4,10
128V: E9.5(A:I3) E9.13(B:I3) ; also sheet 2,4,5,6
/32V: E9.10(B:I1) ; also sheet 4,5
/64V: E9.12(B:I2) ; also sheet 4,5,8
/REPOSSUB: C7.5(B:I1) C9.1(A:I0) C9.4(B:I0) H3.6(B:!Q)
BB: C8.1(A:I0) C9.5(B:I1) L2.8(D:O)
GAME: C9.9(C:I0) C9.12(D:I0) ; also sheet 6,7
JOYDOWN: D9.3(A:I1) R44.1 ; also sheet 20
JOYUP: D9.6(B:I1) R43.2 ; also sheet 20
N$83: C8.2(A:I1) F3.12(F:O)
N$85: C7.3(A:O) C7.4(B:I0)
N$86: C7.6(B:O) H3.9(B:CLK)
N$87: C8.3(A:O) C9.2(A:I1)
N$88: D9.1(A:O) L2.9(D:I)
N$89: D9.4(B:O) F3.13(F:I)
OCEANCOLLISION: C7.2(A:I1) C9.10(C:I1) E9.8(B:O)
OFLOOR: C9.13(D:I1) E9.6(A:O)
P: H3.8(B:J) H3.10(B:CLR) H3.11(B:K) ; also sheet 1,2,6,7,8,9,10,11,14,18,19,20
REPOSSUB: H3.5(B:Q)
SA: C9.3(A:O) ; also sheet 14,16,19
SB: C9.6(B:O) ; also sheet 14,16,19
STOPDOWN: C9.11(D:O) D9.2(A:I0)
STOPUP: C9.8(C:O) D9.5(B:I0)
SUBEN: C7.1(A:I0) ; also sheet 14
VCC: R43.1 R44.2 ; also sheet 6,7,8,12,13,16,17,18,20

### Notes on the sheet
- Not sure why it didn't work when
  I replaced the 7402 and 7404 with a
  7432...
- STOP WHEN HIT FLOOR
- OR GAMEOVER
- Move the submarine from the air to the
  water before screen shows game. 
  (Because of video converter)
- Basically a 1-bit memory cell that says
  Is the sub under water? If 0, THEN MOVE
  IT UNDER WATER!!!
  If 1, then maybe physics actually is realistic
  here...
- Only necessary because on power on,
  it starts at the top. I need to get it to the
  bottom before a game starts...
- -OR-
  If 0, I DIDN'T KNOW SUBS
  COULD FLY! If 1, then 
  nothing to see here...
- The collision for the ocean
- OCEAN FLOOR
- (Well, depth limit...)
- KA - AKH - 001
- C

## Sheet 16 of 20: Submarine Level Graphic

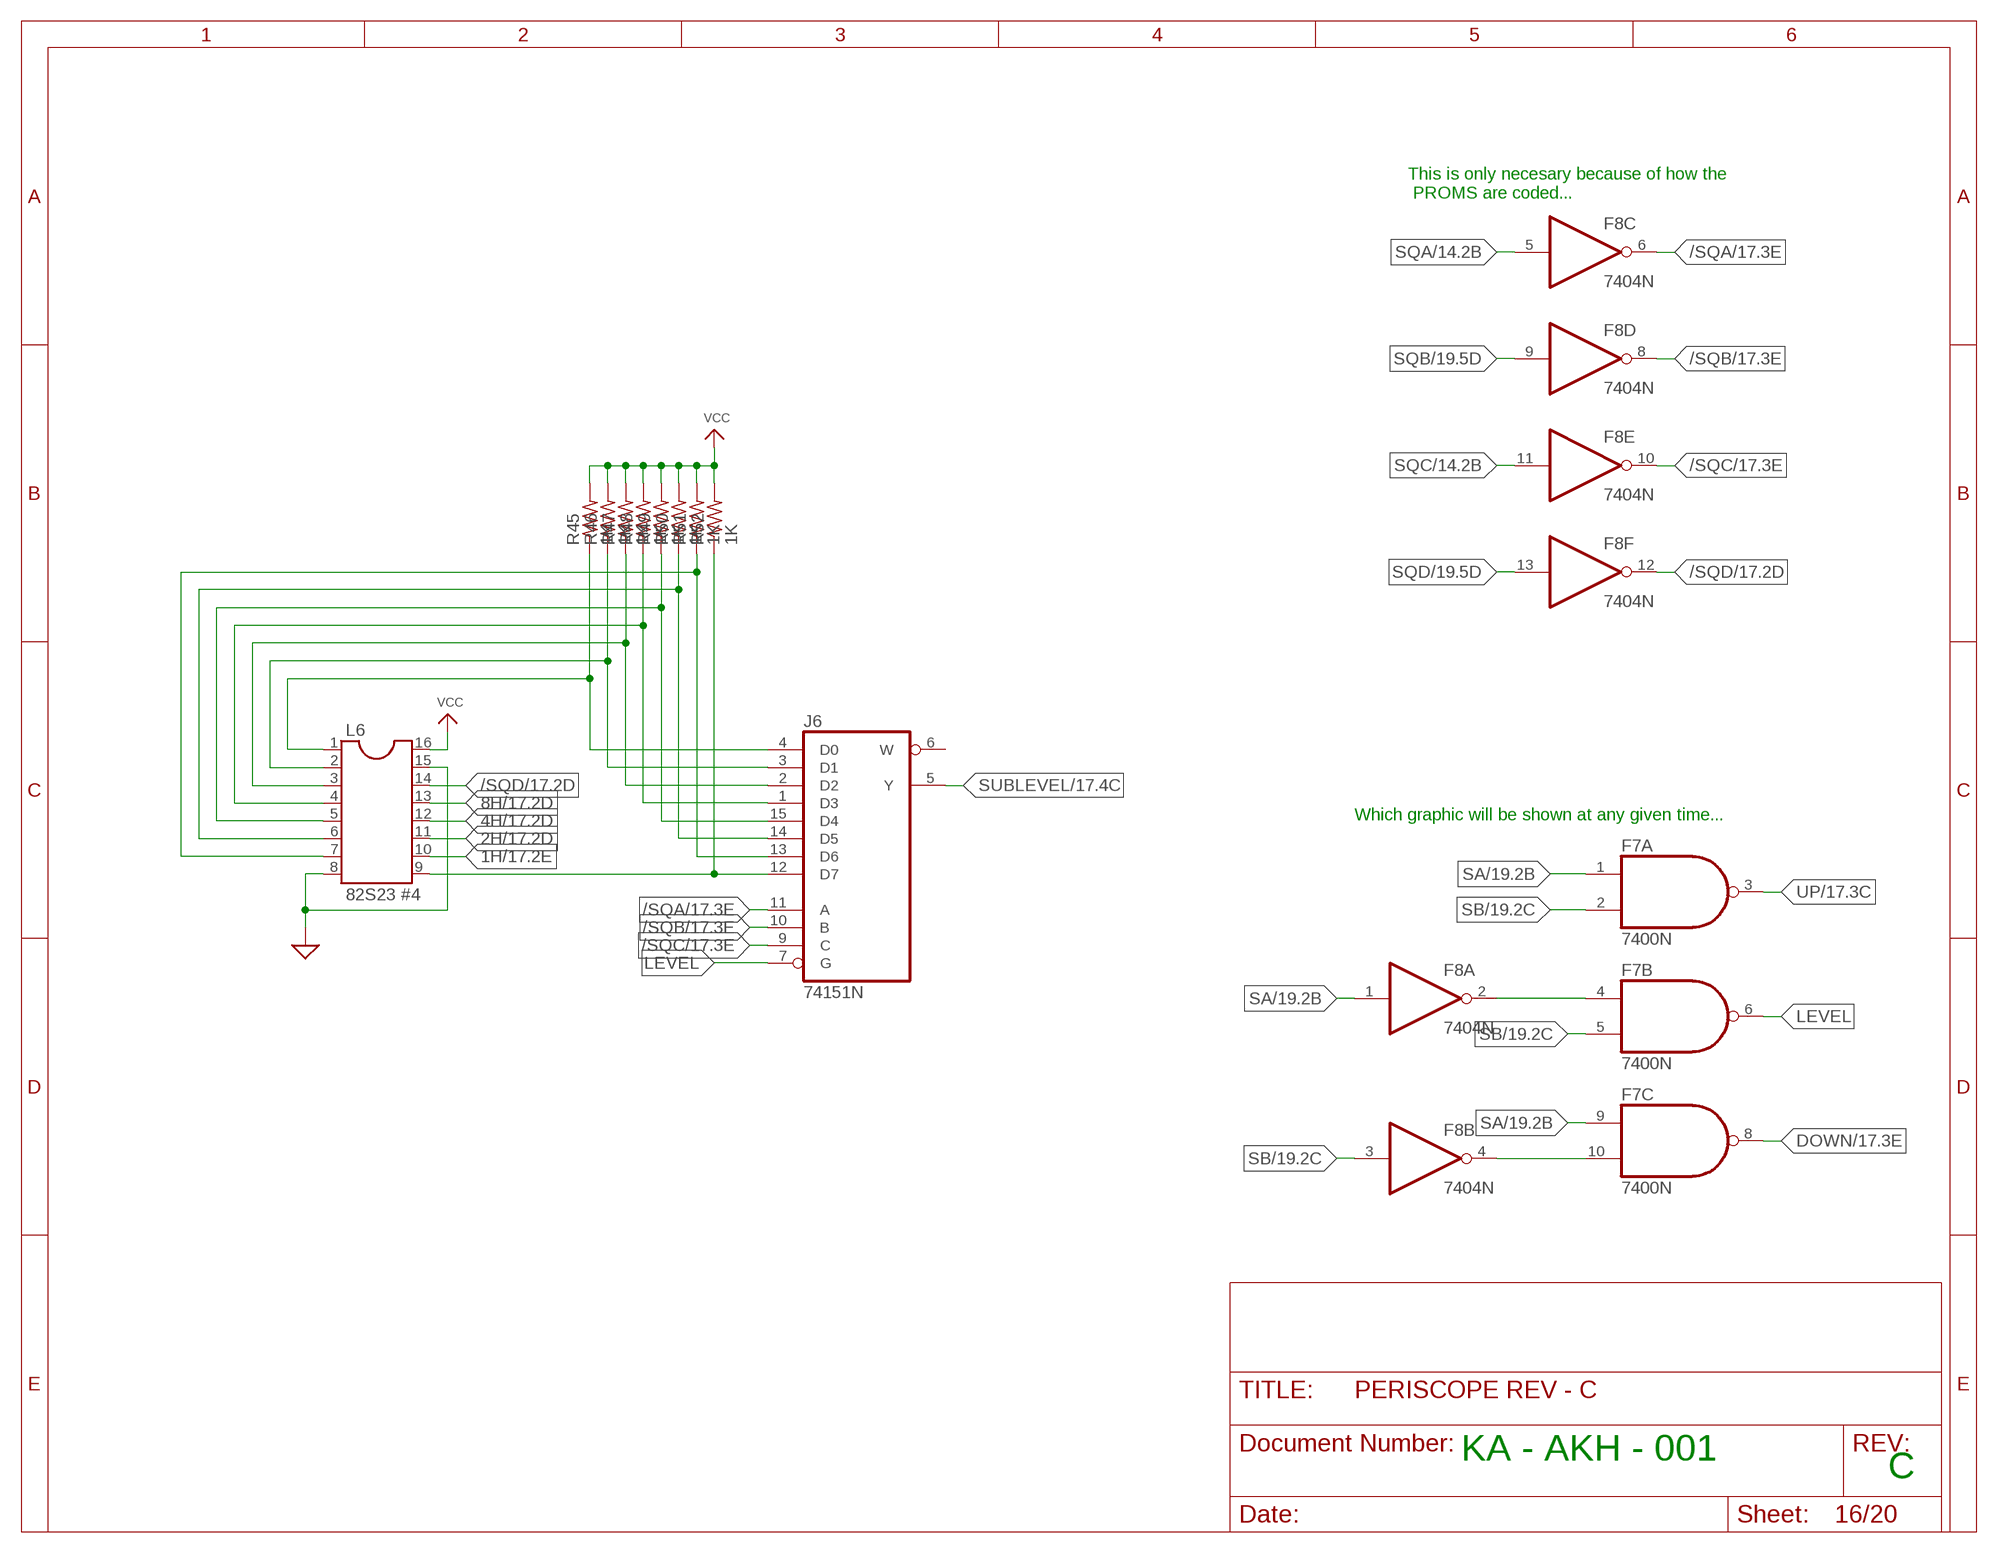
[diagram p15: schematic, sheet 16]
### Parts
F7  7400N  [DIL14]
F8  7404N  [DIL14]
J6  74151N  [DIL16]
L6  82S23 #4  DIL16S  [SOCKET-16]
R45  1K  R-US_0207/10  [0207/10]
R46  1K  R-US_0207/10  [0207/10]
R47  1K  R-US_0207/10  [0207/10]
R48  1K  R-US_0207/10  [0207/10]
R49  1K  R-US_0207/10  [0207/10]
R50  1K  R-US_0207/10  [0207/10]
R51  1K  R-US_0207/10  [0207/10]
R52  1K  R-US_0207/10  [0207/10]

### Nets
1H: L6.10 ; also sheet 1,4,17
2H: L6.11 ; also sheet 1,5,17
4H: L6.12 ; also sheet 1,9,17
8H: L6.13 ; also sheet 1,9,17,19
/SQA: F8.6(C:O) J6.11(A) ; also sheet 17
/SQB: F8.8(D:O) J6.10(B) ; also sheet 17
/SQC: F8.10(E:O) J6.9(C) ; also sheet 17
/SQD: F8.12(F:O) L6.14 ; also sheet 17
DOWN: F7.8(C:O) ; also sheet 17
GND: L6.8 L6.15 ; supply symbol labelled SUP ; also sheet 5,6,7,8,10,12,13,14,17,18,20
LEVEL: F7.6(B:O) J6.7(G)
N$132: J6.12(D7) L6.9 R52.1
N$180: J6.4(D0) L6.1 R45.1
N$181: J6.3(D1) L6.2 R46.1
N$182: J6.2(D2) L6.3 R47.1
N$183: J6.1(D3) L6.4 R48.1
N$184: J6.15(D4) L6.5 R49.1
N$185: J6.14(D5) L6.6 R50.1
N$186: J6.13(D6) L6.7 R51.1
N$194: F7.10(C:I1) F8.4(B:O)
N$195: F7.4(B:I0) F8.2(A:O)
SA: F7.1(A:I0) F7.9(C:I0) F8.1(A:I) ; also sheet 14,15,19
SB: F7.2(A:I1) F7.5(B:I1) F8.3(B:I) ; also sheet 14,15,19
SQA: F8.5(C:I) ; also sheet 14
SQB: F8.9(D:I) ; also sheet 14,19
SQC: F8.11(E:I) ; also sheet 14
SQD: F8.13(F:I) ; also sheet 14,19
SUBLEVEL: J6.5(Y) ; also sheet 17
UP: F7.3(A:O) ; also sheet 17
VCC: L6.16 R45.2 R46.2 R47.2 R48.2 R49.2 R50.2 R51.2 R52.2 ; also sheet 6,7,8,12,13,15,17,18,20
Unconnected: J6.6(W)

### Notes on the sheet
- This is only necesary because of how the
   PROMS are coded...
- Which graphic will be shown at any given time...
- KA - AKH - 001
- C

## Sheet 17 of 20: Submarine Up / Down Graphics

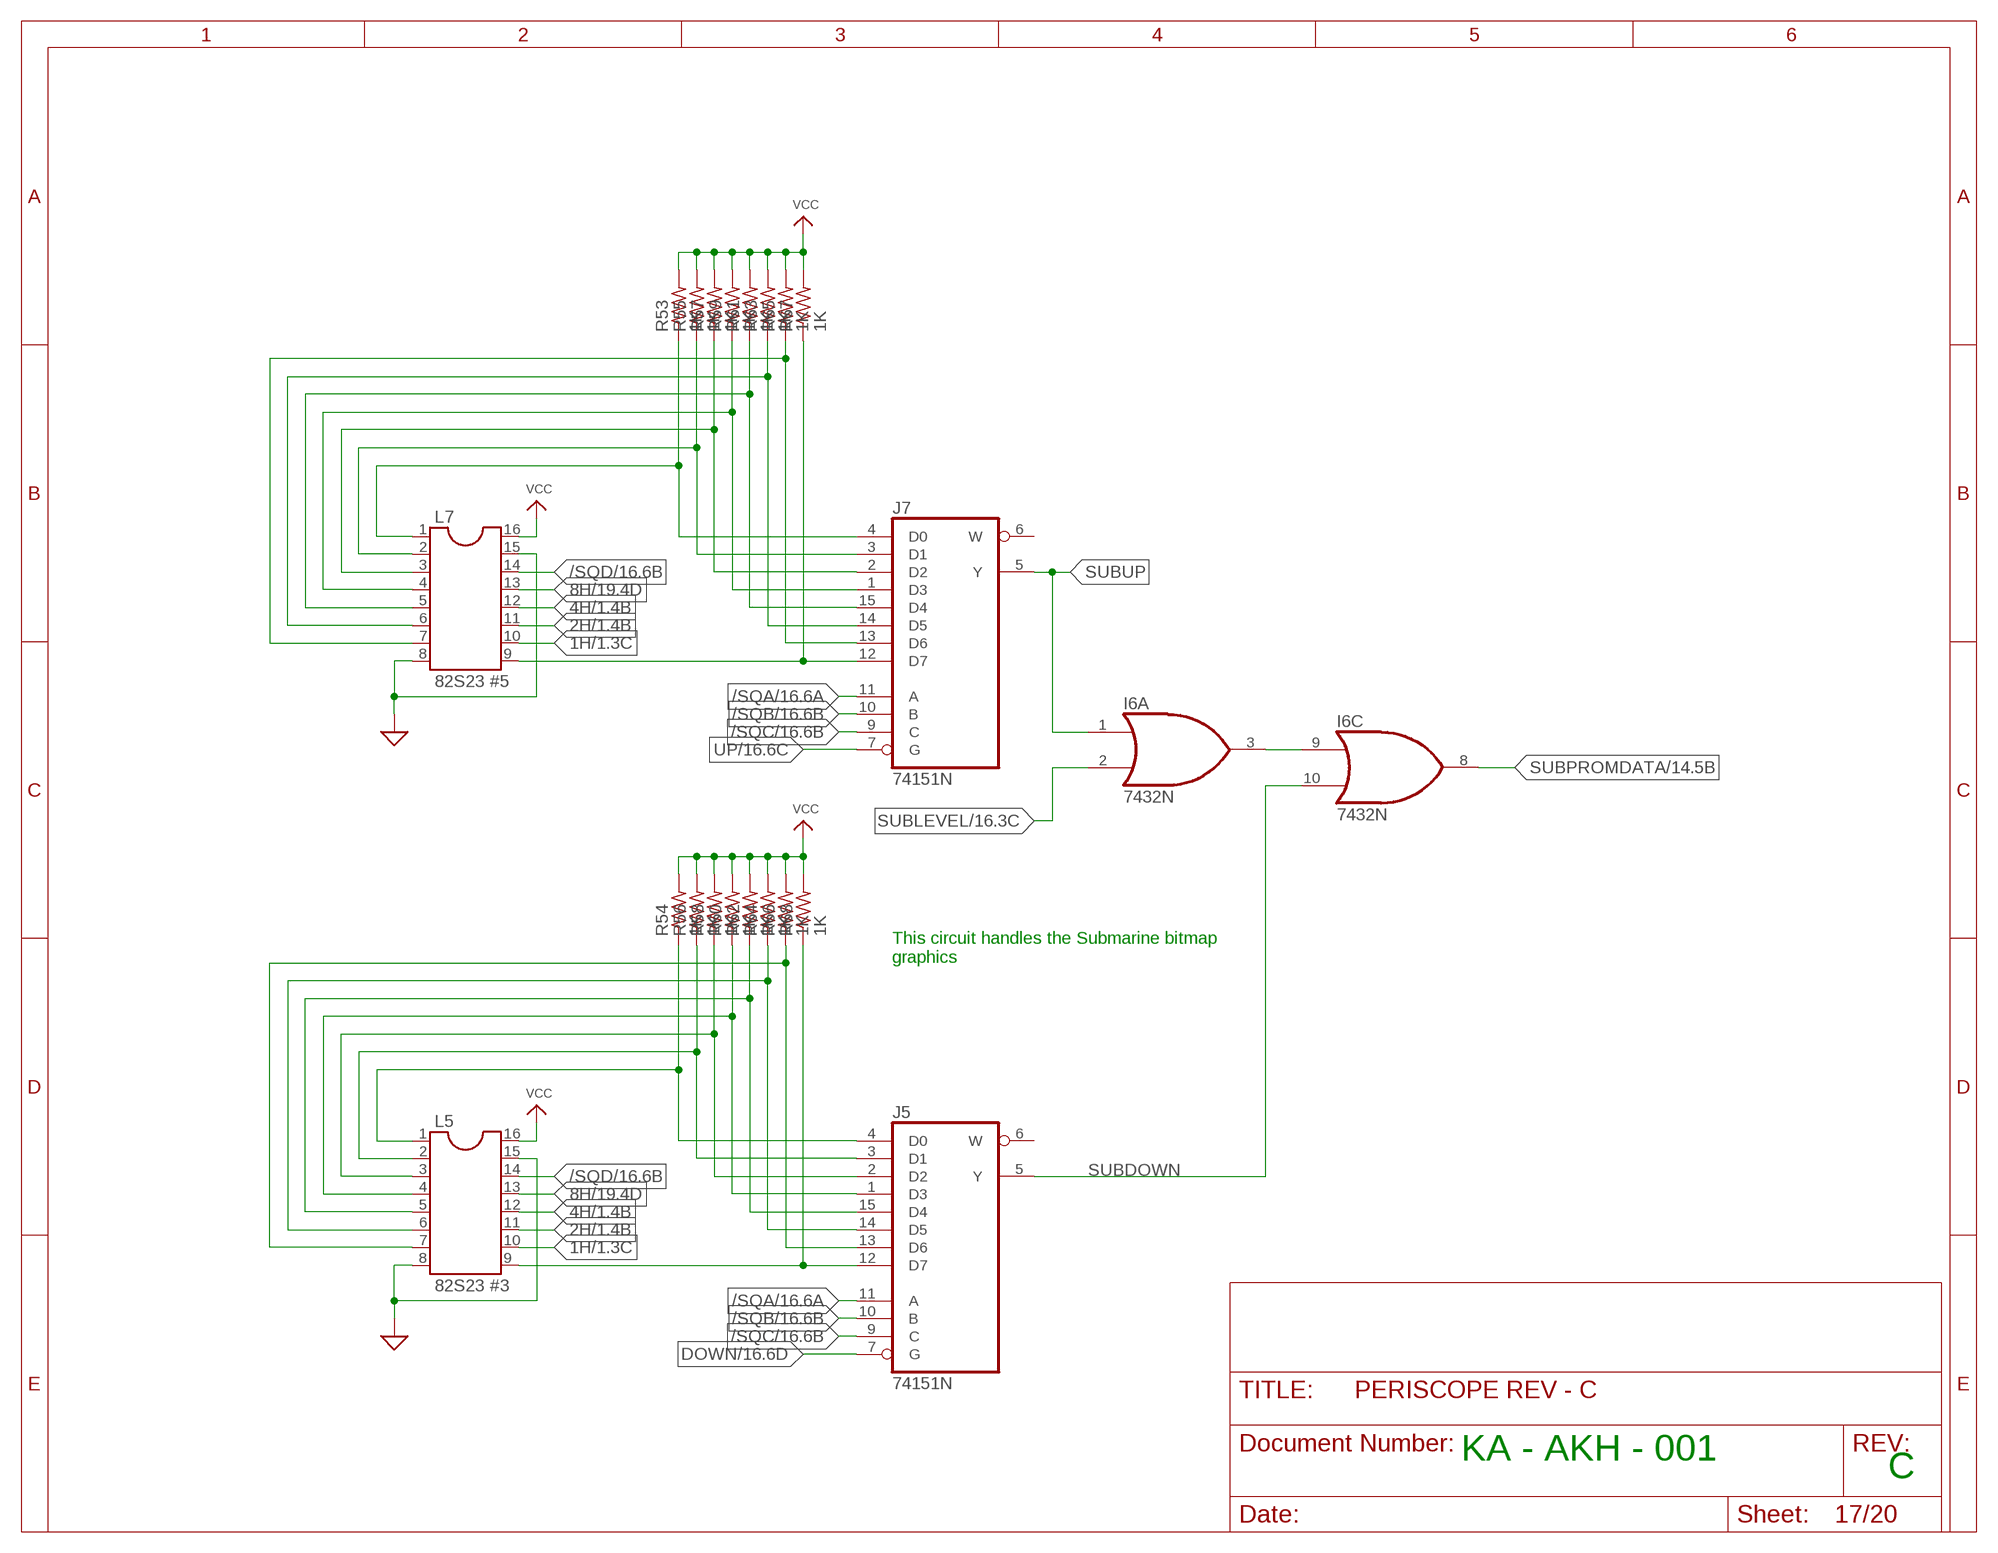
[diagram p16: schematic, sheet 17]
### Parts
I6  7432N  [DIL14]
J5  74151N  [DIL16]
J7  74151N  [DIL16]
L5  82S23 #3  DIL16S  [SOCKET-16]
L7  82S23 #5  DIL16S  [SOCKET-16]
R53  1K  R-US_0207/10  [0207/10]
R54  1K  R-US_0207/10  [0207/10]
R55  1K  R-US_0207/10  [0207/10]
R56  1K  R-US_0207/10  [0207/10]
R57  1K  R-US_0207/10  [0207/10]
R58  1K  R-US_0207/10  [0207/10]
R59  1K  R-US_0207/10  [0207/10]
R60  1K  R-US_0207/10  [0207/10]
R61  1K  R-US_0207/10  [0207/10]
R62  1K  R-US_0207/10  [0207/10]
R63  1K  R-US_0207/10  [0207/10]
R64  1K  R-US_0207/10  [0207/10]
R65  1K  R-US_0207/10  [0207/10]
R66  1K  R-US_0207/10  [0207/10]
R67  1K  R-US_0207/10  [0207/10]
R68  1K  R-US_0207/10  [0207/10]

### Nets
1H: L5.10 L7.10 ; also sheet 1,4,16
2H: L5.11 L7.11 ; also sheet 1,5,16
4H: L5.12 L7.12 ; also sheet 1,9,16
8H: L5.13 L7.13 ; also sheet 1,9,16,19
/SQA: J5.11(A) J7.11(A) ; also sheet 16
/SQB: J5.10(B) J7.10(B) ; also sheet 16
/SQC: J5.9(C) J7.9(C) ; also sheet 16
/SQD: L5.14 L7.14 ; also sheet 16
DOWN: J5.7(G) ; also sheet 16
GND: L5.8 L5.15 L7.8 L7.15 ; supply symbol labelled SUP ; also sheet 5,6,7,8,10,12,13,14,16,18,20
N$93: I6.3(A:O) I6.9(C:I0)
N$94: J7.12(D7) L7.9 R67.1
N$167: J5.12(D7) L5.9 R68.1
N$168: J7.4(D0) L7.1 R53.1
N$169: J7.3(D1) L7.2 R55.1
N$171: J7.2(D2) L7.3 R57.1
N$172: J7.1(D3) L7.4 R59.1
N$175: J7.15(D4) L7.5 R61.1
N$176: J7.14(D5) L7.6 R63.1
N$178: J7.13(D6) L7.7 R65.1
N$179: J5.4(D0) L5.1 R54.1
N$187: J5.3(D1) L5.2 R56.1
N$188: J5.2(D2) L5.3 R58.1
N$189: J5.1(D3) L5.4 R60.1
N$190: J5.15(D4) L5.5 R62.1
N$191: J5.14(D5) L5.6 R64.1
N$192: J5.13(D6) L5.7 R66.1
SUBDOWN: I6.10(C:I1) J5.5(Y)
SUBLEVEL: I6.2(A:I1) ; also sheet 16
SUBPROMDATA: I6.8(C:O) ; also sheet 14
SUBUP: I6.1(A:I0) J7.5(Y)
UP: J7.7(G) ; also sheet 16
VCC: L5.16 L7.16 R53.2 R54.2 R55.2 R56.2 R57.2 R58.2 R59.2 R60.2 R61.2 R62.2 R63.2 R64.2 R65.2 R66.2 R67.2 R68.2 ; also sheet 6,7,8,12,13,15,16,18,20
Unconnected: J5.6(W) J7.6(W)

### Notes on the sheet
- This circuit handles the Submarine bitmap
  graphics
- KA - AKH - 001
- C

## Sheet 18 of 20: TORPEDO MOTION

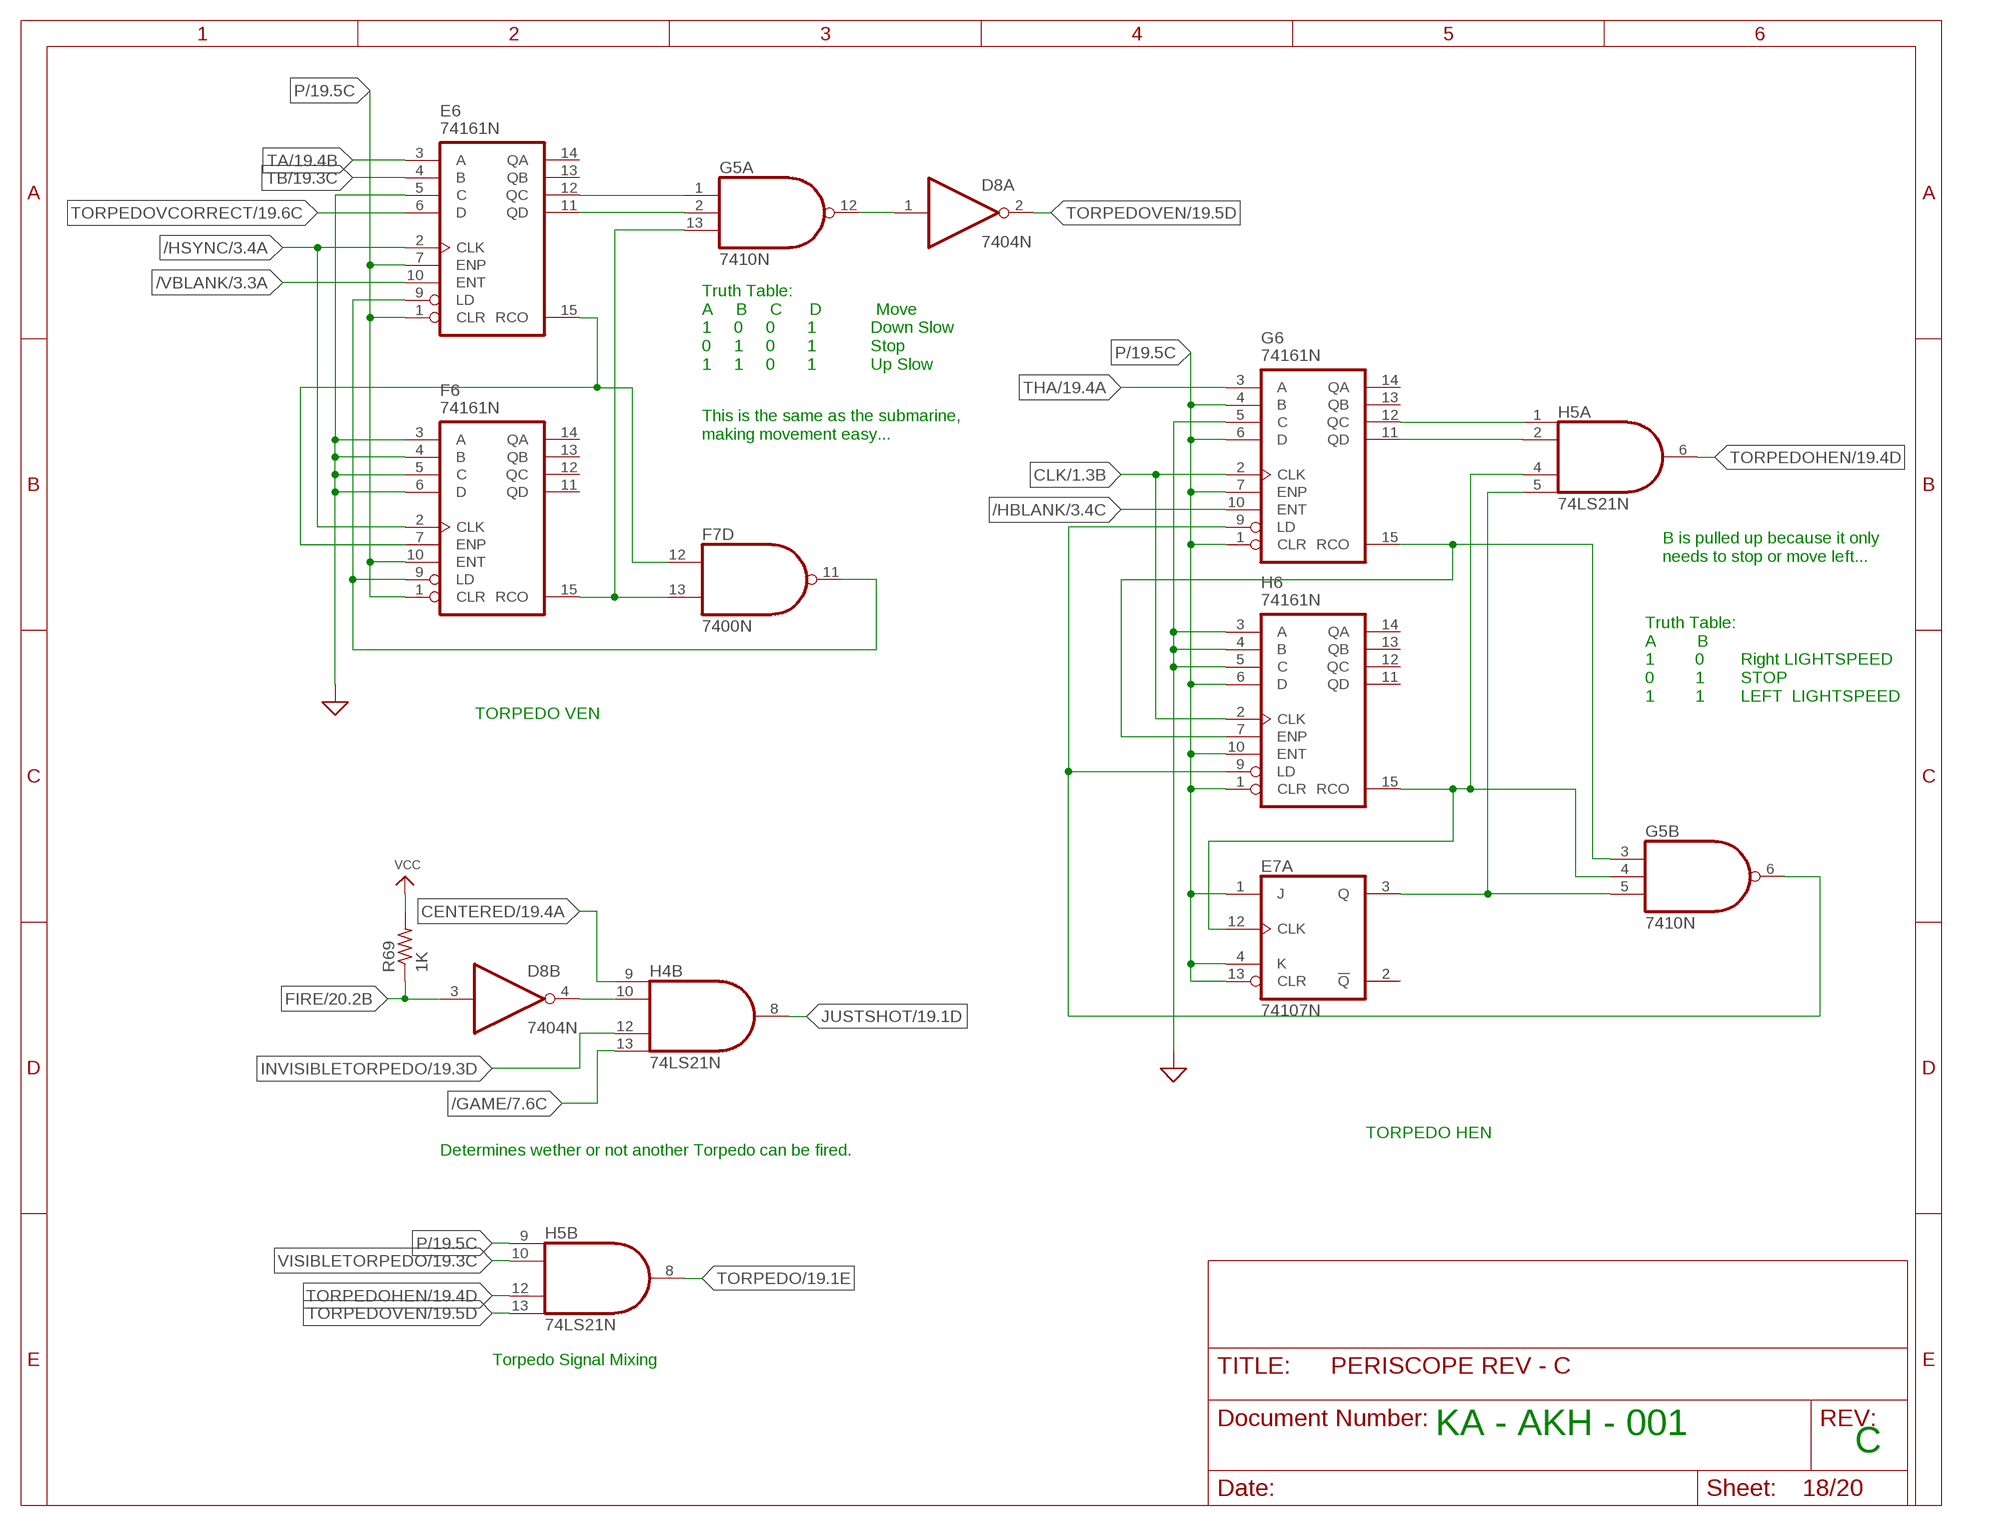
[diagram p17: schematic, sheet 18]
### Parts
E6  74161N  [DIL16]
E7  74107N  [DIL14]
F6  74161N  [DIL16]
G5  7410N  [DIL14]
G6  74161N  [DIL16]
H4  74LS21N  [DIL14]
H5  74LS21N  [DIL14]
H6  74161N  [DIL16]
R69  1K  R-US_0207/10  [0207/10]

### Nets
/GAME: H4.13(B:I3) ; also sheet 7
/HBLANK: G6.10(ENT) ; also sheet 3
/HSYNC: E6.2(CLK) F6.2(CLK) ; also sheet 3,14
/VBLANK: E6.10(ENT) ; also sheet 3,14
CENTERED: H4.9(B:I0) ; also sheet 19
CLK: G6.2(CLK) H6.2(CLK) ; also sheet 1,12
FIRE: D8.3(B:I) R69.1 ; also sheet 20
GND: E6.5(C) F6.3(A) F6.4(B) F6.5(C) F6.6(D) G6.5(C) H6.3(A) H6.4(B) H6.5(C) ; supply symbol labelled SUP ; also sheet 5,6,7,8,10,12,13,14,16,17,20
INVISIBLETORPEDO: H4.12(B:I2) ; also sheet 19
JUSTSHOT: H4.8(B:O) ; also sheet 19
N$197: E6.9(LD) F6.9(LD) F7.11(D:O)
N$198: F6.15(RCO) F7.13(D:I1) G5.13(A:I2)
N$199: E6.15(RCO) F6.7(ENP) F7.12(D:I0)
N$200: E6.12(QC) G5.1(A:I0)
N$201: E6.11(QD) G5.2(A:I1)
N$202: D8.1(A:I) G5.12(A:O)
N$206: G5.6(B:O) G6.9(LD) H6.9(LD)
N$207: G5.3(B:I0) G6.15(RCO) H6.7(ENP)
N$208: E7.12(A:CLK) G5.4(B:I1) H5.4(A:I2) H6.15(RCO)
N$210: G6.12(QC) H5.1(A:I0)
N$212: G6.11(QD) H5.2(A:I1)
N$214: E7.3(A:Q) G5.5(B:I2) H5.5(A:I3)
N$227: D8.4(B:O) H4.10(B:I1)
P: E6.1(CLR) E6.7(ENP) E7.1(A:J) E7.4(A:K) E7.13(A:CLR) F6.1(CLR) F6.10(ENT) G6.1(CLR) G6.4(B) G6.6(D) G6.7(ENP) H5.9(B:I0) H6.1(CLR) H6.6(D) H6.10(ENT) ; also sheet 1,2,6,7,8,9,10,11,14,15,19,20
TA: E6.3(A) ; also sheet 19
TB: E6.4(B) ; also sheet 19
THA: G6.3(A) ; also sheet 19
TORPEDO: H5.8(B:O) ; also sheet 5,11,19
TORPEDOHEN: H5.6(A:O) H5.12(B:I2) ; also sheet 19
TORPEDOVCORRECT: E6.6(D) ; also sheet 19
TORPEDOVEN: D8.2(A:O) H5.13(B:I3) ; also sheet 19
VCC: R69.2 ; also sheet 6,7,8,12,13,15,16,17,20
VISIBLETORPEDO: H5.10(B:I1) ; also sheet 5,19
Unconnected: E6.13(QB) E6.14(QA) E7.2(A:!Q) F6.11(QD) F6.12(QC) F6.13(QB) F6.14(QA) G6.13(QB) G6.14(QA) H6.11(QD) H6.12(QC) H6.13(QB) H6.14(QA)

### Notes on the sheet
- Truth Table:
  A     B     C      D            Move
  1     0     0       1            Down Slow
  0     1     0       1            Stop
  1     1     0       1            Up Slow
- This is the same as the submarine,
  making movement easy...
- B is pulled up because it only
  needs to stop or move left...
- Truth Table:
  A         B    
  1         0        Right LIGHTSPEED
  0         1        STOP
  1         1        LEFT  LIGHTSPEED
- TORPEDO VEN
- TORPEDO HEN
- Determines wether or not another Torpedo can be fired.
- Torpedo Signal Mixing
- KA - AKH - 001
- C

## Sheet 19 of 20: Torpedo Control

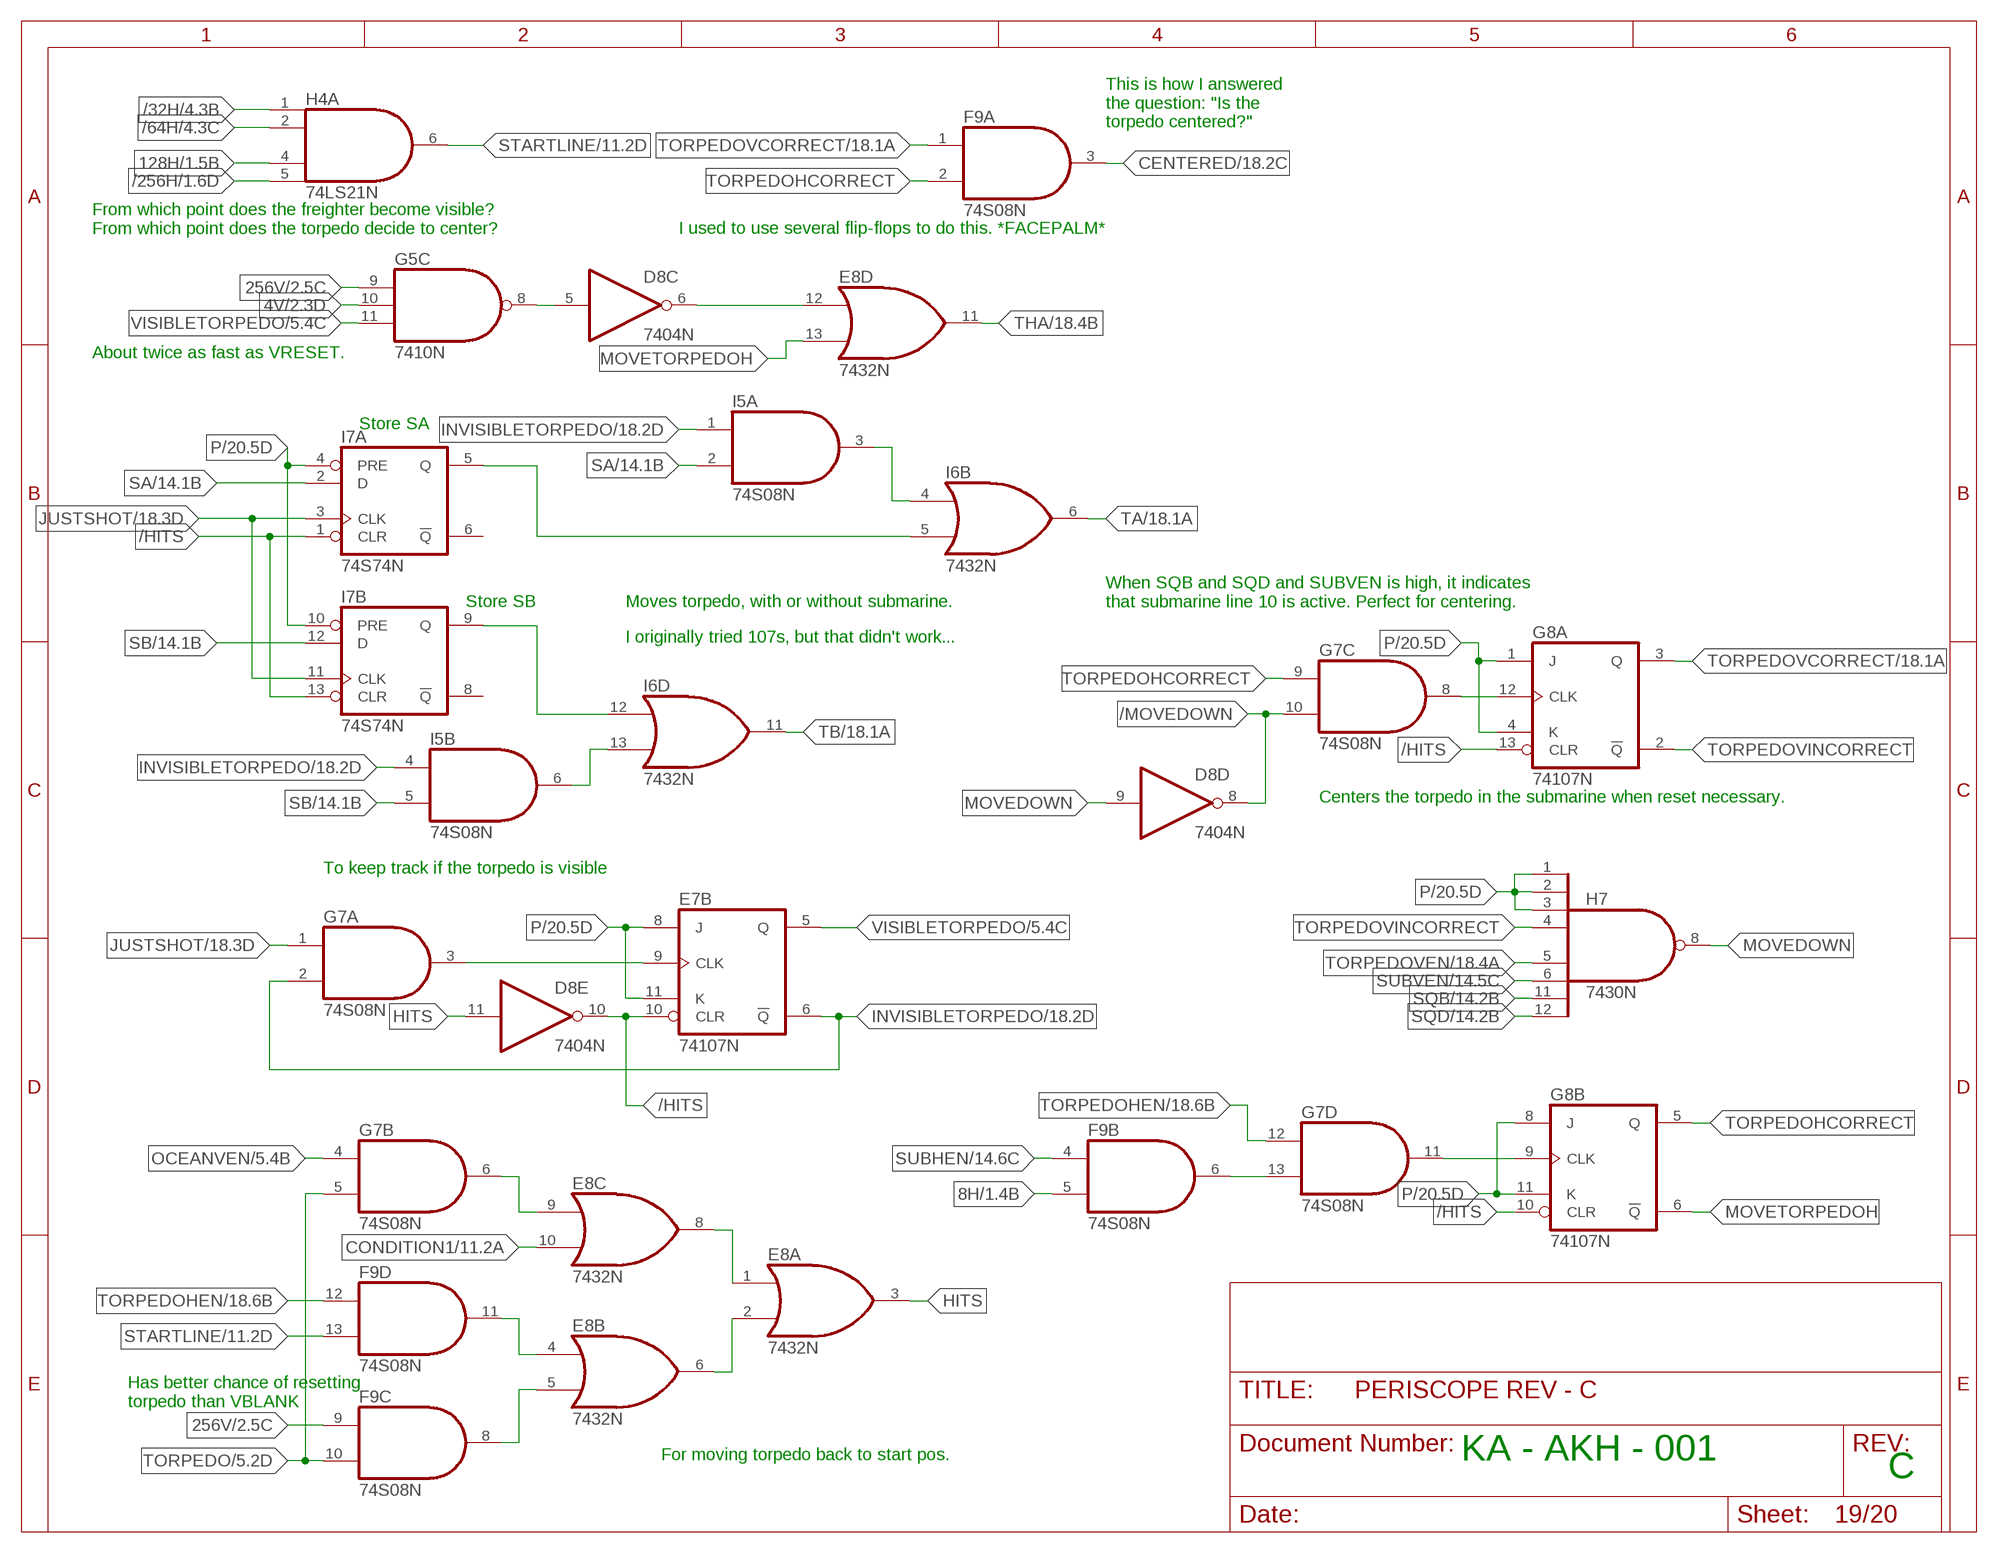
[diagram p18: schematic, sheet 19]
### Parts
E8  7432N  [DIL14]
F9  74S08N  [DIL14]
G7  74S08N  [DIL14]
G8  74107N  [DIL14]
H7  7430N  [DIL14]
I7  74S74N  [DIL14]

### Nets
4V: G5.10(C:I1) ; also sheet 2,3,4,9
8H: F9.5(B:I1) ; also sheet 1,9,16,17
128H: H4.4(A:I2) ; also sheet 1,4,8
256V: F9.9(C:I0) G5.9(C:I0) ; also sheet 2,7
/32H: H4.1(A:I0) ; also sheet 4,8
/64H: H4.2(A:I1) ; also sheet 4,8
/256H: H4.5(A:I3) ; also sheet 1,8
/HITS: D8.10(E:O) E7.10(B:CLR) G8.10(B:CLR) G8.13(A:CLR) I7.1(A:CLR) I7.13(B:CLR)
/MOVEDOWN: D8.8(D:O) G7.10(C:I1)
CENTERED: F9.3(A:O) ; also sheet 18
CONDITION1: E8.10(C:I1) ; also sheet 11
HITS: D8.11(E:I) E8.3(A:O)
INVISIBLETORPEDO: E7.6(B:!Q) G7.2(A:I1) I5.1(A:I0) I5.4(B:I0) ; also sheet 18
JUSTSHOT: G7.1(A:I0) I7.3(A:CLK) I7.11(B:CLK) ; also sheet 18
MOVEDOWN: D8.9(D:I) H7.8(O)
MOVETORPEDOH: E8.13(D:I1) G8.6(B:!Q)
N$215: E8.2(A:I1) E8.6(B:O)
N$216: E8.4(B:I0) F9.11(D:O)
N$217: E8.5(B:I1) F9.8(C:O)
N$219: E8.9(C:I0) G7.6(B:O)
N$220: E8.1(A:I0) E8.8(C:O)
N$223: E7.9(B:CLK) G7.3(A:O)
N$225: G7.11(D:O) G8.9(B:CLK)
N$226: F9.6(B:O) G7.13(D:I1)
N$228: D8.5(C:I) G5.8(C:O)
N$229: D8.6(C:O) E8.12(D:I0)
N$231: I6.5(B:I1) I7.5(A:Q)
N$232: I6.12(D:I0) I7.9(B:Q)
N$233: I5.3(A:O) I6.4(B:I0)
N$234: I5.6(B:O) I6.13(D:I1)
N$235: G7.8(C:O) G8.12(A:CLK)
OCEANVEN: G7.4(B:I0) ; also sheet 5,11
P: E7.8(B:J) E7.11(B:K) G8.1(A:J) G8.4(A:K) G8.8(B:J) G8.11(B:K) H7.1(I0) H7.2(I1) H7.3(I2) I7.4(A:PRE) I7.10(B:PRE) ; also sheet 1,2,6,7,8,9,10,11,14,15,18,20
SA: I5.2(A:I1) I7.2(A:D) ; also sheet 14,15,16
SB: I5.5(B:I1) I7.12(B:D) ; also sheet 14,15,16
SQB: H7.11(I6) ; also sheet 14,16
SQD: H7.12(I7) ; also sheet 14,16
STARTLINE: F9.13(D:I1) H4.6(A:O) ; also sheet 11
SUBHEN: F9.4(B:I0) ; also sheet 14
SUBVEN: H7.6(I5) ; also sheet 14
TA: I6.6(B:O) ; also sheet 18
TB: I6.11(D:O) ; also sheet 18
THA: E8.11(D:O) ; also sheet 18
TORPEDO: F9.10(C:I1) G7.5(B:I1) ; also sheet 5,11,18
TORPEDOHCORRECT: F9.2(A:I1) G7.9(C:I0) G8.5(B:Q)
TORPEDOHEN: F9.12(D:I0) G7.12(D:I0) ; also sheet 18
TORPEDOVCORRECT: F9.1(A:I0) G8.3(A:Q) ; also sheet 18
TORPEDOVEN: H7.5(I4) ; also sheet 18
TORPEDOVINCORRECT: G8.2(A:!Q) H7.4(I3)
VISIBLETORPEDO: E7.5(B:Q) G5.11(C:I2) ; also sheet 5,18
Unconnected: I7.6(A:!Q) I7.8(B:!Q)

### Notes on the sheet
- This is how I answered
  the question: "Is the 
  torpedo centered?"
- From which point does the freighter become visible?
  From which point does the torpedo decide to center?
- I used to use several flip-flops to do this. *FACEPALM*
- About twice as fast as VRESET.
- Store SA
- Store SB | Moves torpedo, with or without submarine.
- When SQB and SQD and SUBVEN is high, it indicates
  that submarine line 10 is active. Perfect for centering.
- I originally tried 107s, but that didn't work...
- Centers the torpedo in the submarine when reset necessary.
- To keep track if the torpedo is visible
- Has better chance of resetting 
  torpedo than VBLANK
- For moving torpedo back to start pos. | KA - AKH - 001
- C

## Sheet 20 of 20: Card Edge Connector

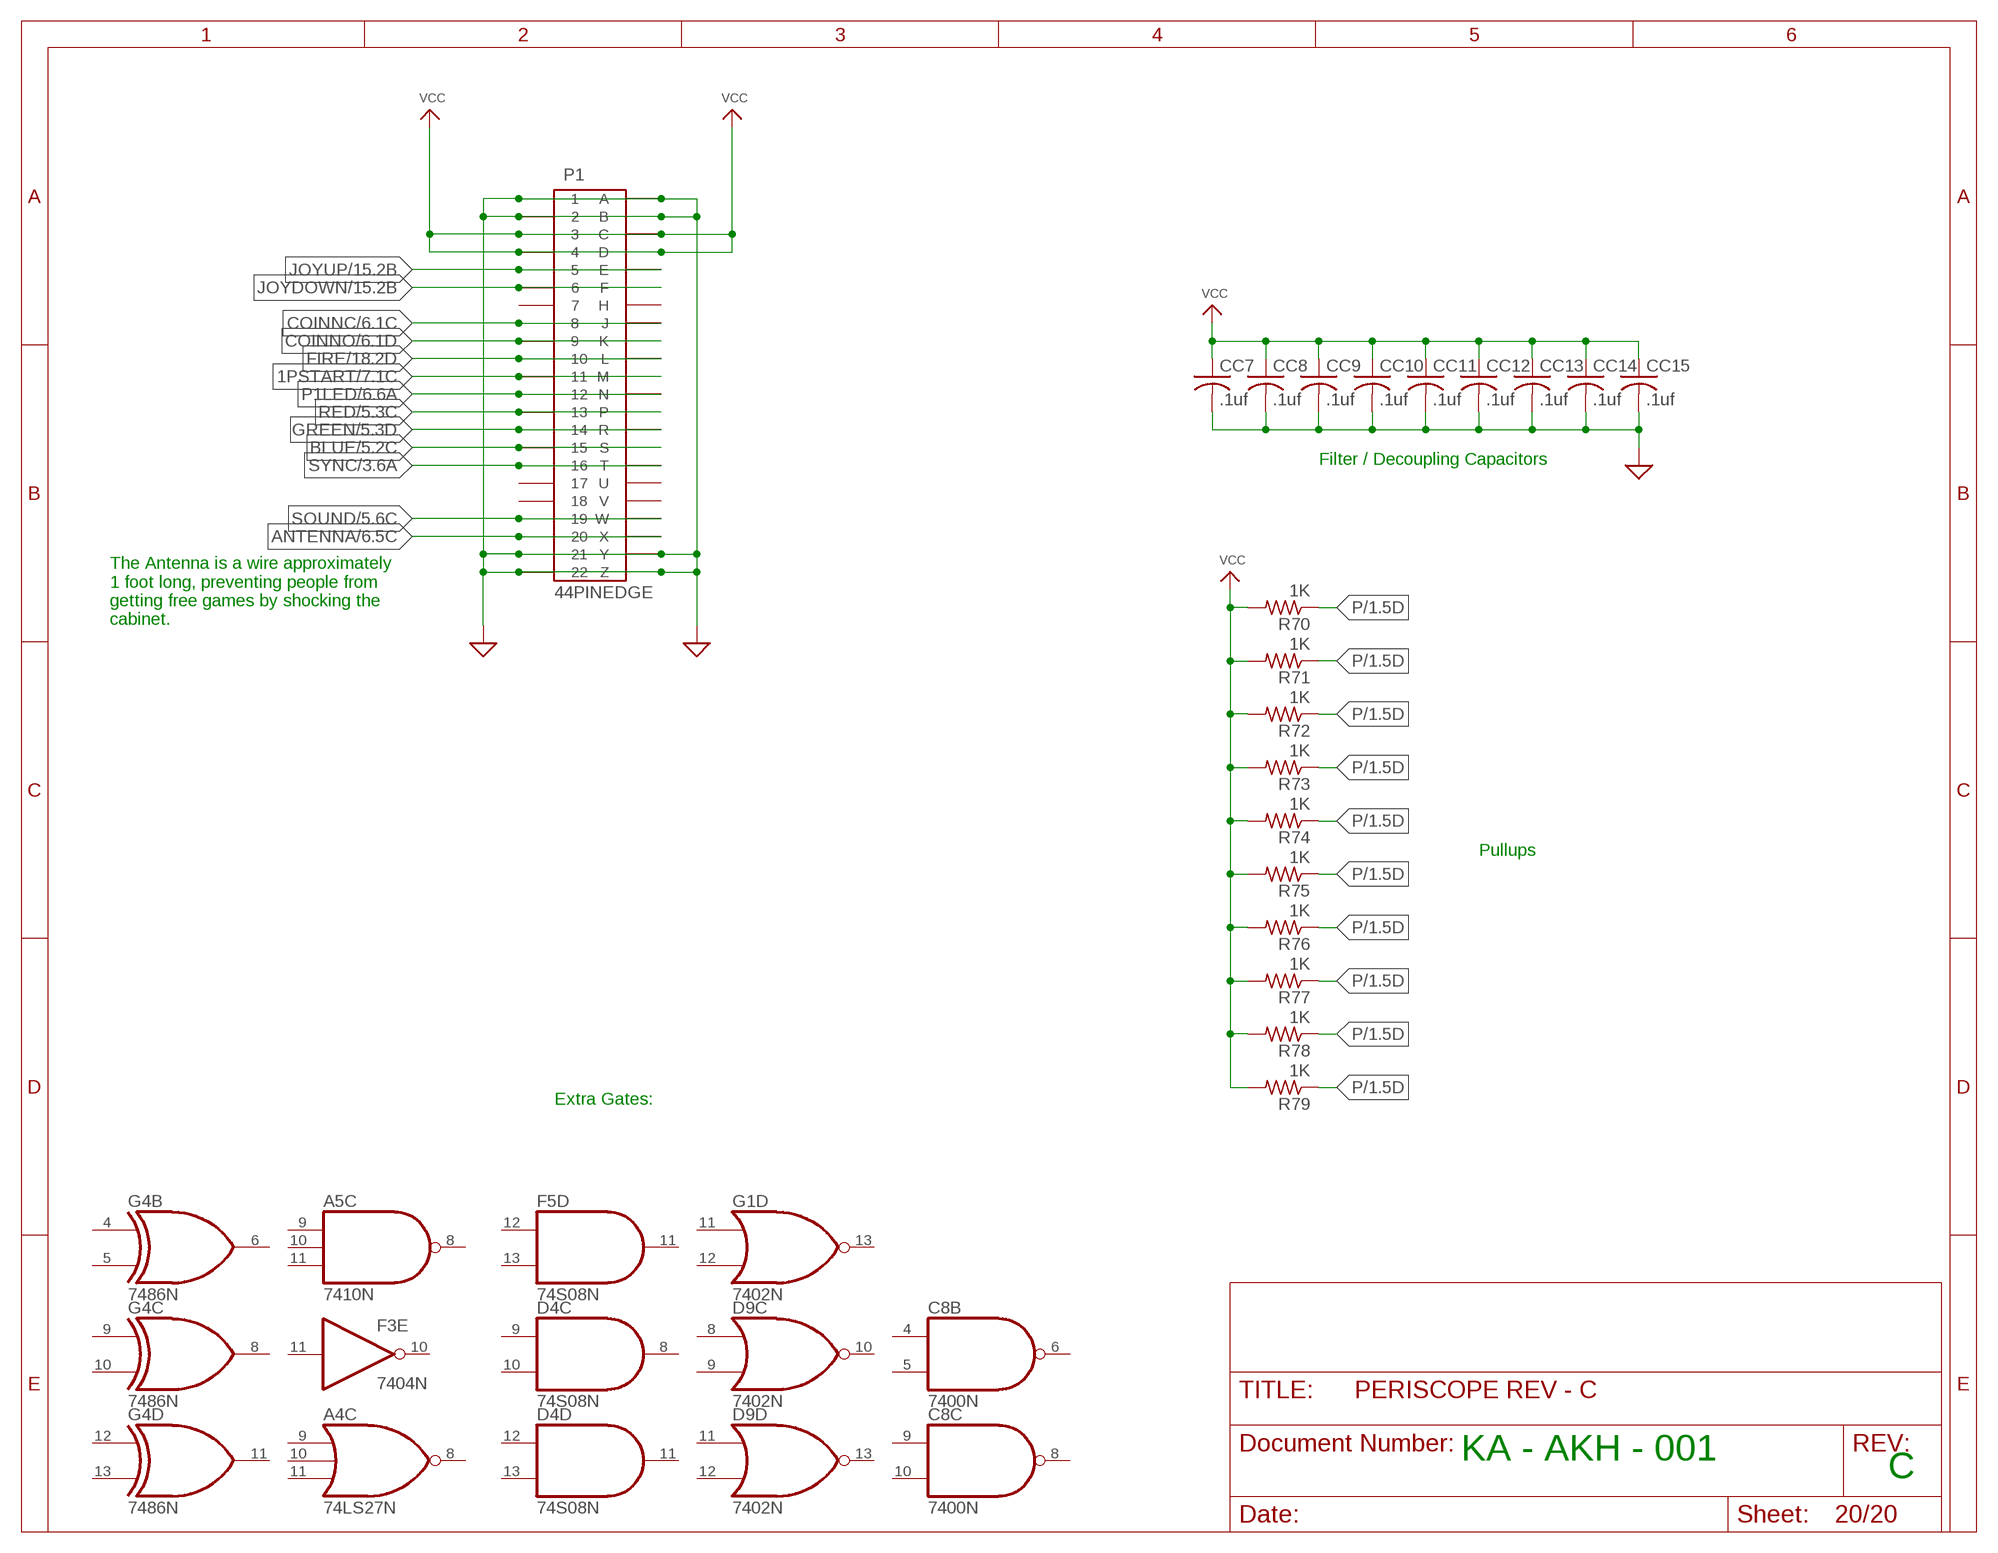
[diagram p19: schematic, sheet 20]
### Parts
CC7  .1uf  C-US050-025X075  [C050-025X075]
CC8  .1uf  C-US050-025X075  [C050-025X075]
CC9  .1uf  C-US050-025X075  [C050-025X075]
CC10  .1uf  C-US050-025X075  [C050-025X075]
CC11  .1uf  C-US050-025X075  [C050-025X075]
CC12  .1uf  C-US050-025X075  [C050-025X075]
CC13  .1uf  C-US050-025X075  [C050-025X075]
CC14  .1uf  C-US050-025X075  [C050-025X075]
CC15  .1uf  C-US050-025X075  [C050-025X075]
P1  44PINEDGE  [44PINEDGE]
R70  1K  R-US_0207/10  [0207/10]
R71  1K  R-US_0207/10  [0207/10]
R72  1K  R-US_0207/10  [0207/10]
R73  1K  R-US_0207/10  [0207/10]
R74  1K  R-US_0207/10  [0207/10]
R75  1K  R-US_0207/10  [0207/10]
R76  1K  R-US_0207/10  [0207/10]
R77  1K  R-US_0207/10  [0207/10]
R78  1K  R-US_0207/10  [0207/10]
R79  1K  R-US_0207/10  [0207/10]

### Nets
1PSTART: P1.11 P1.M ; also sheet 7
ANTENNA: P1.20 P1.X ; also sheet 6
BLUE: P1.15 P1.S ; also sheet 5
COINNC: P1.8 P1.J ; also sheet 6
COINNO: P1.9 P1.K ; also sheet 6,7
FIRE: P1.10 P1.L ; also sheet 18
GND: CC7.2 CC8.2 CC9.2 CC10.2 CC11.2 CC12.2 CC13.2 CC14.2 CC15.2 P1.1 P1.2 P1.21 P1.22 P1.A P1.B P1.Y P1.Z ; supply symbol labelled SUP ; also sheet 5,6,7,8,10,12,13,14,16,17,18
GREEN: P1.14 P1.R ; also sheet 5
JOYDOWN: P1.6 P1.F ; also sheet 15
JOYUP: P1.5 P1.E ; also sheet 15
P: R70.1 R71.1 R72.1 R73.1 R74.1 R75.1 R76.1 R77.1 R78.1 R79.1 ; also sheet 1,2,6,7,8,9,10,11,14,15,18,19
P1LED: P1.12 P1.N ; also sheet 6
RED: P1.13 P1.P ; also sheet 5
SOUND: P1.19 P1.W ; also sheet 5
SYNC: P1.16 P1.T ; also sheet 3
VCC: CC7.1 CC8.1 CC9.1 CC10.1 CC11.1 CC12.1 CC13.1 CC14.1 CC15.1 P1.3 P1.4 P1.C P1.D R70.2 R71.2 R72.2 R73.2 R74.2 R75.2 R76.2 R77.2 R78.2 R79.2 ; also sheet 6,7,8,12,13,15,16,17,18
Unconnected: A4.8(C:O) A4.9(C:I0) A4.10(C:I1) A4.11(C:I2) A5.8(C:O) A5.9(C:I0) A5.10(C:I1) A5.11(C:I2) C8.4(B:I0) C8.5(B:I1) C8.6(B:O) C8.8(C:O) C8.9(C:I0) C8.10(C:I1) D4.8(C:O) D4.9(C:I0) D4.10(C:I1) D4.11(D:O) D4.12(D:I0) D4.13(D:I1) D9.8(C:I0) D9.9(C:I1) D9.10(C:O) D9.11(D:I0) D9.12(D:I1) D9.13(D:O) F3.10(E:O) F3.11(E:I) F5.11(D:O) F5.12(D:I0) F5.13(D:I1) G1.11(D:I0) G1.12(D:I1) G1.13(D:O) G4.4(B:I0) G4.5(B:I1) G4.6(B:O) G4.8(C:O) G4.9(C:I0) G4.10(C:I1) G4.11(D:O) G4.12(D:I0) G4.13(D:I1) P1.7 P1.17 P1.18 P1.H P1.U P1.V

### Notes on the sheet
- Filter / Decoupling Capacitors
- The Antenna is a wire approximately
  1 foot long, preventing people from
  getting free games by shocking the
  cabinet.
- Pullups
- Extra Gates:
- KA - AKH - 001
- C

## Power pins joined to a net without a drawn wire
GND: A1.7(P:GND) A2.7(P:GND) A3.10(GND) A4.7(P:GND) A5.7(P:GND) A6.8(GND) A7.7(P:GND) A8.7(P:GND) A9.10(GND) B1.7(P:GND) B2.8(GND) B3.10(GND) B4.7(P:GND) B5.7(P:GND) B6.8(GND) B7.7(P:GND) B8.7(P:GND) B9.10(GND) C1.7(P:GND) C4.7(P:GND) C5.7(GND) C6.8(GND) C7.7(P:GND) C8.7(P:GND) C9.7(P:GND) D1.7(P:GND) D4.7(P:GND) D5.7(P:GND) D6.8(GND) D7.7(GND) D8.7(P:GND) D9.7(P:GND) E1.7(P:GND) E3.7(P:GND) E4.7(P:GND) E5.7(P:GND) E6.8(GND) E7.7(P:GND) E8.7(P:GND) E9.7(P:GND) F1.7(P:GND) F2.7(P:GND) F3.7(P:GND) F4.7(GND) F5.7(P:GND) F6.8(GND) F7.7(P:GND) F8.7(P:GND) F9.7(P:GND) G1.7(P:GND) G2.7(P:GND) G3.7(P:GND) G4.7(P:GND) G5.7(P:GND) G6.8(GND) G7.7(P:GND) G8.7(P:GND) H1.10(GND) H2.10(GND) H3.7(P:GND) H4.7(P:GND) H5.7(P:GND) H6.8(GND) H7.7(GND) I1.7(GND) I2.7(P:GND) I3.10(GND) I4.10(GND) I5.7(P:GND) I6.7(P:GND) I7.7(P:GND) J1.10(GND) J2.10(GND) J3.8(GND) J4.8(GND) J5.8(GND) J6.8(GND) J7.8(GND) J8.8(GND) J9.8(GND) K1.7(P:GND) K2.7(P:GND) L2.7(P:GND)
VCC: A1.14(P:VCC) A2.14(P:VCC) A3.5(VCC) A4.14(P:VCC) A5.14(P:VCC) A6.16(VCC) A7.14(P:VCC) A8.14(P:VCC) A9.5(VCC) B1.14(P:VCC) B2.16(VCC) B3.5(VCC) B4.14(P:VCC) B5.14(P:VCC) B6.16(VCC) B7.14(P:VCC) B8.14(P:VCC) B9.5(VCC) C1.14(P:VCC) C4.14(P:VCC) C5.14(VCC) C6.16(VCC) C7.14(P:VCC) C8.14(P:VCC) C9.14(P:VCC) D1.14(P:VCC) D4.14(P:VCC) D5.14(P:VCC) D6.16(VCC) D7.14(VCC) D8.14(P:VCC) D9.14(P:VCC) E1.14(P:VCC) E3.14(P:VCC) E4.14(P:VCC) E5.14(P:VCC) E6.16(VCC) E7.14(P:VCC) E8.14(P:VCC) E9.14(P:VCC) F1.14(P:VCC) F2.14(P:VCC) F3.14(P:VCC) F4.14(VCC) F5.14(P:VCC) F6.16(VCC) F7.14(P:VCC) F8.14(P:VCC) F9.14(P:VCC) G1.14(P:VCC) G2.14(P:VCC) G3.14(P:VCC) G4.14(P:VCC) G5.14(P:VCC) G6.16(VCC) G7.14(P:VCC) G8.14(P:VCC) H1.5(VCC) H2.5(VCC) H3.14(P:VCC) H4.14(P:VCC) H5.14(P:VCC) H6.16(VCC) H7.14(VCC) I1.14(VCC) I2.14(P:VCC) I3.5(VCC) I4.5(VCC) I5.14(P:VCC) I6.14(P:VCC) I7.14(P:VCC) J1.5(VCC) J2.5(VCC) J3.16(VCC) J4.16(VCC) J5.16(VCC) J6.16(VCC) J7.16(VCC) J8.16(VCC) J9.16(VCC) K1.14(P:VCC) K2.14(P:VCC) L2.14(P:VCC)

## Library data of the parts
A1 A8 B7 C7 D4 F5 F9 G7 I5 = 74xx-us:74*08: Quad 2-input AND gate
A2 A7 B1 E9 H4 H5 = 74xx-us:74*21: Dual 4-input AND gate
A3 A9 B3 B9 H1 H2 I3 I4 J1 J2 = 74xx-us:74*93: Decade, divide by twelve and binary COUNTER
A4 = 74xx-us:74*27: Triple 3-input NOR gate
A5 B5 C4 G2 G5 = 74xx-us:74*10: Triple 3-input NAND gate
A6 B6 C6 D6 E6 F6 G6 H6 = oldchips:74*161: Synchronous 4-bit COUNTER with direct clear
B2 = 74xx-us:74*157: Quadruple 2-line to 1-line data SELECTOR/MULTIPLEXER
B4 C9 D5 E4 E5 E8 I6 = 74xx-us:74*32: Quad 2-input OR gate
B8 E7 G8 H3 K2 = 74xx-us:74*107: Dual J-K FLIP FLOP, clear
C1 E1 E3 I2 I7 = 74xx-us:74*74: Dual D type positive edge triggered FLIP FLOP, preset and clear
C3 L3-L9 = ic-package:DIL16: Dual In Line / Socket
C5 D7 F4 H7 I1 = 74xx-us:74*30: 8-input NAND gate
C8 F1 F7 K1 = 74xx-us:74*00: Quad 2-input NAND gate
CC1 CC2 CC7-CC15 = rcl:C-US: CAPACITOR, American symbol; SPICEPREFIX: C
CC3 CC4 CC6 = adafruit:C-US: CAPACITOR, American symbol
CC5 = rcl:CPOL-US: POLARIZED CAPACITOR, American symbol; SPICEPREFIX: C
D1 D8 F2 F3 F8 G3 L2 = 74xx-us:74*04: Hex INVERTER
D3 = SparkFun-IC-Special-Function:555: General purpose bipolar Timer Datasheet SparkFun Products SparkFun SparkPunk Sequencer Kit (KIT-12707) Storefront Component: 555 Timer (COM-09273) Two parts valid for production: VFP: IC-11930 (M7555 PTH) VFP: IC-09173 (555 PTH) - Preferred; PROD_ID: IC-09173; PROD_ID_ALT: IC-09173
D9 G1 = 74xx-us:74*02: Quad 2-input NOR gate
DD1-DD3 = adafruit:1N4004: DIODE
G4 = 74xx-us:74*86: Quad 2-input EXCLUSIV-OR (XOR) gate
J3-J9 = 74xx-us:74*151: Data SELECTOR/MULTIPLEXER
P1 = edge-156:44PINEDGE: 44 PIN EDGE CONNECTOR FOR PCB
Q1 = special:XTAL/S: CRYSTAL
Q2 = adafruit:2N2907*: PNP Transistor Big Oval pads
R1 R2 = rcl:R-US_: RESISTOR, American symbol; SPICEPREFIX: R
R3-R69 = adafruit:R-US_: RESISTOR, American symbol
R70-R79 = resistor:R-US_: RESISTOR, American symbol
S1 = SparkFun-Switches:SWITCH-SPDT: Single Pole, Double Throw (SPDT) Switch Single-pole, double-throw (SPDT) switch. Variant Overview SMD-AYZ0202 Surface Mount DPDT Switch (COM-00597) Used on e.g. LilyPad Arduino USB - ATmega32U4 Board PTH-11.6X4.0MM SPDT Mini Power Switch (COM-00102) Used on e.g. SparkFun Simon Says - Through-Hole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; PROD_ID: SWCH-08261; SF_SKU: COM-00102
T1 T2 = adafruit:2N2222: NPN TRANSISTOR Big oval pads
VR1 = SparkFun-Resistors:TRIMPOT: Trimming Potentiometer (Trimpot) Three-terminal potentiometers, with an adjustable wiper and two adjustable resistors. A pot can be used to create a configurable voltage divider, or as a variable resistor. "Trimpots" are a subset of potentiometers, usually intended for "set-and-forget"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; PROD_ID: RES-09730; SF_SKU: COM-09806
VR2 = SparkFun-Resistors:TRIMPOT: Trimming Potentiometer (Trimpot) Three-terminal potentiometers, with an adjustable wiper and two adjustable resistors. A pot can be used to create a configurable voltage divider, or as a variable resistor. "Trimpots" are a subset of potentiometers, usually intended for "set-and-forget"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; PROD_ID: RES-09730; SF_SKU: COM-09806; VALUE: 10k

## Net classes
0 default: width 0.508 mm, clearance 0.254 mm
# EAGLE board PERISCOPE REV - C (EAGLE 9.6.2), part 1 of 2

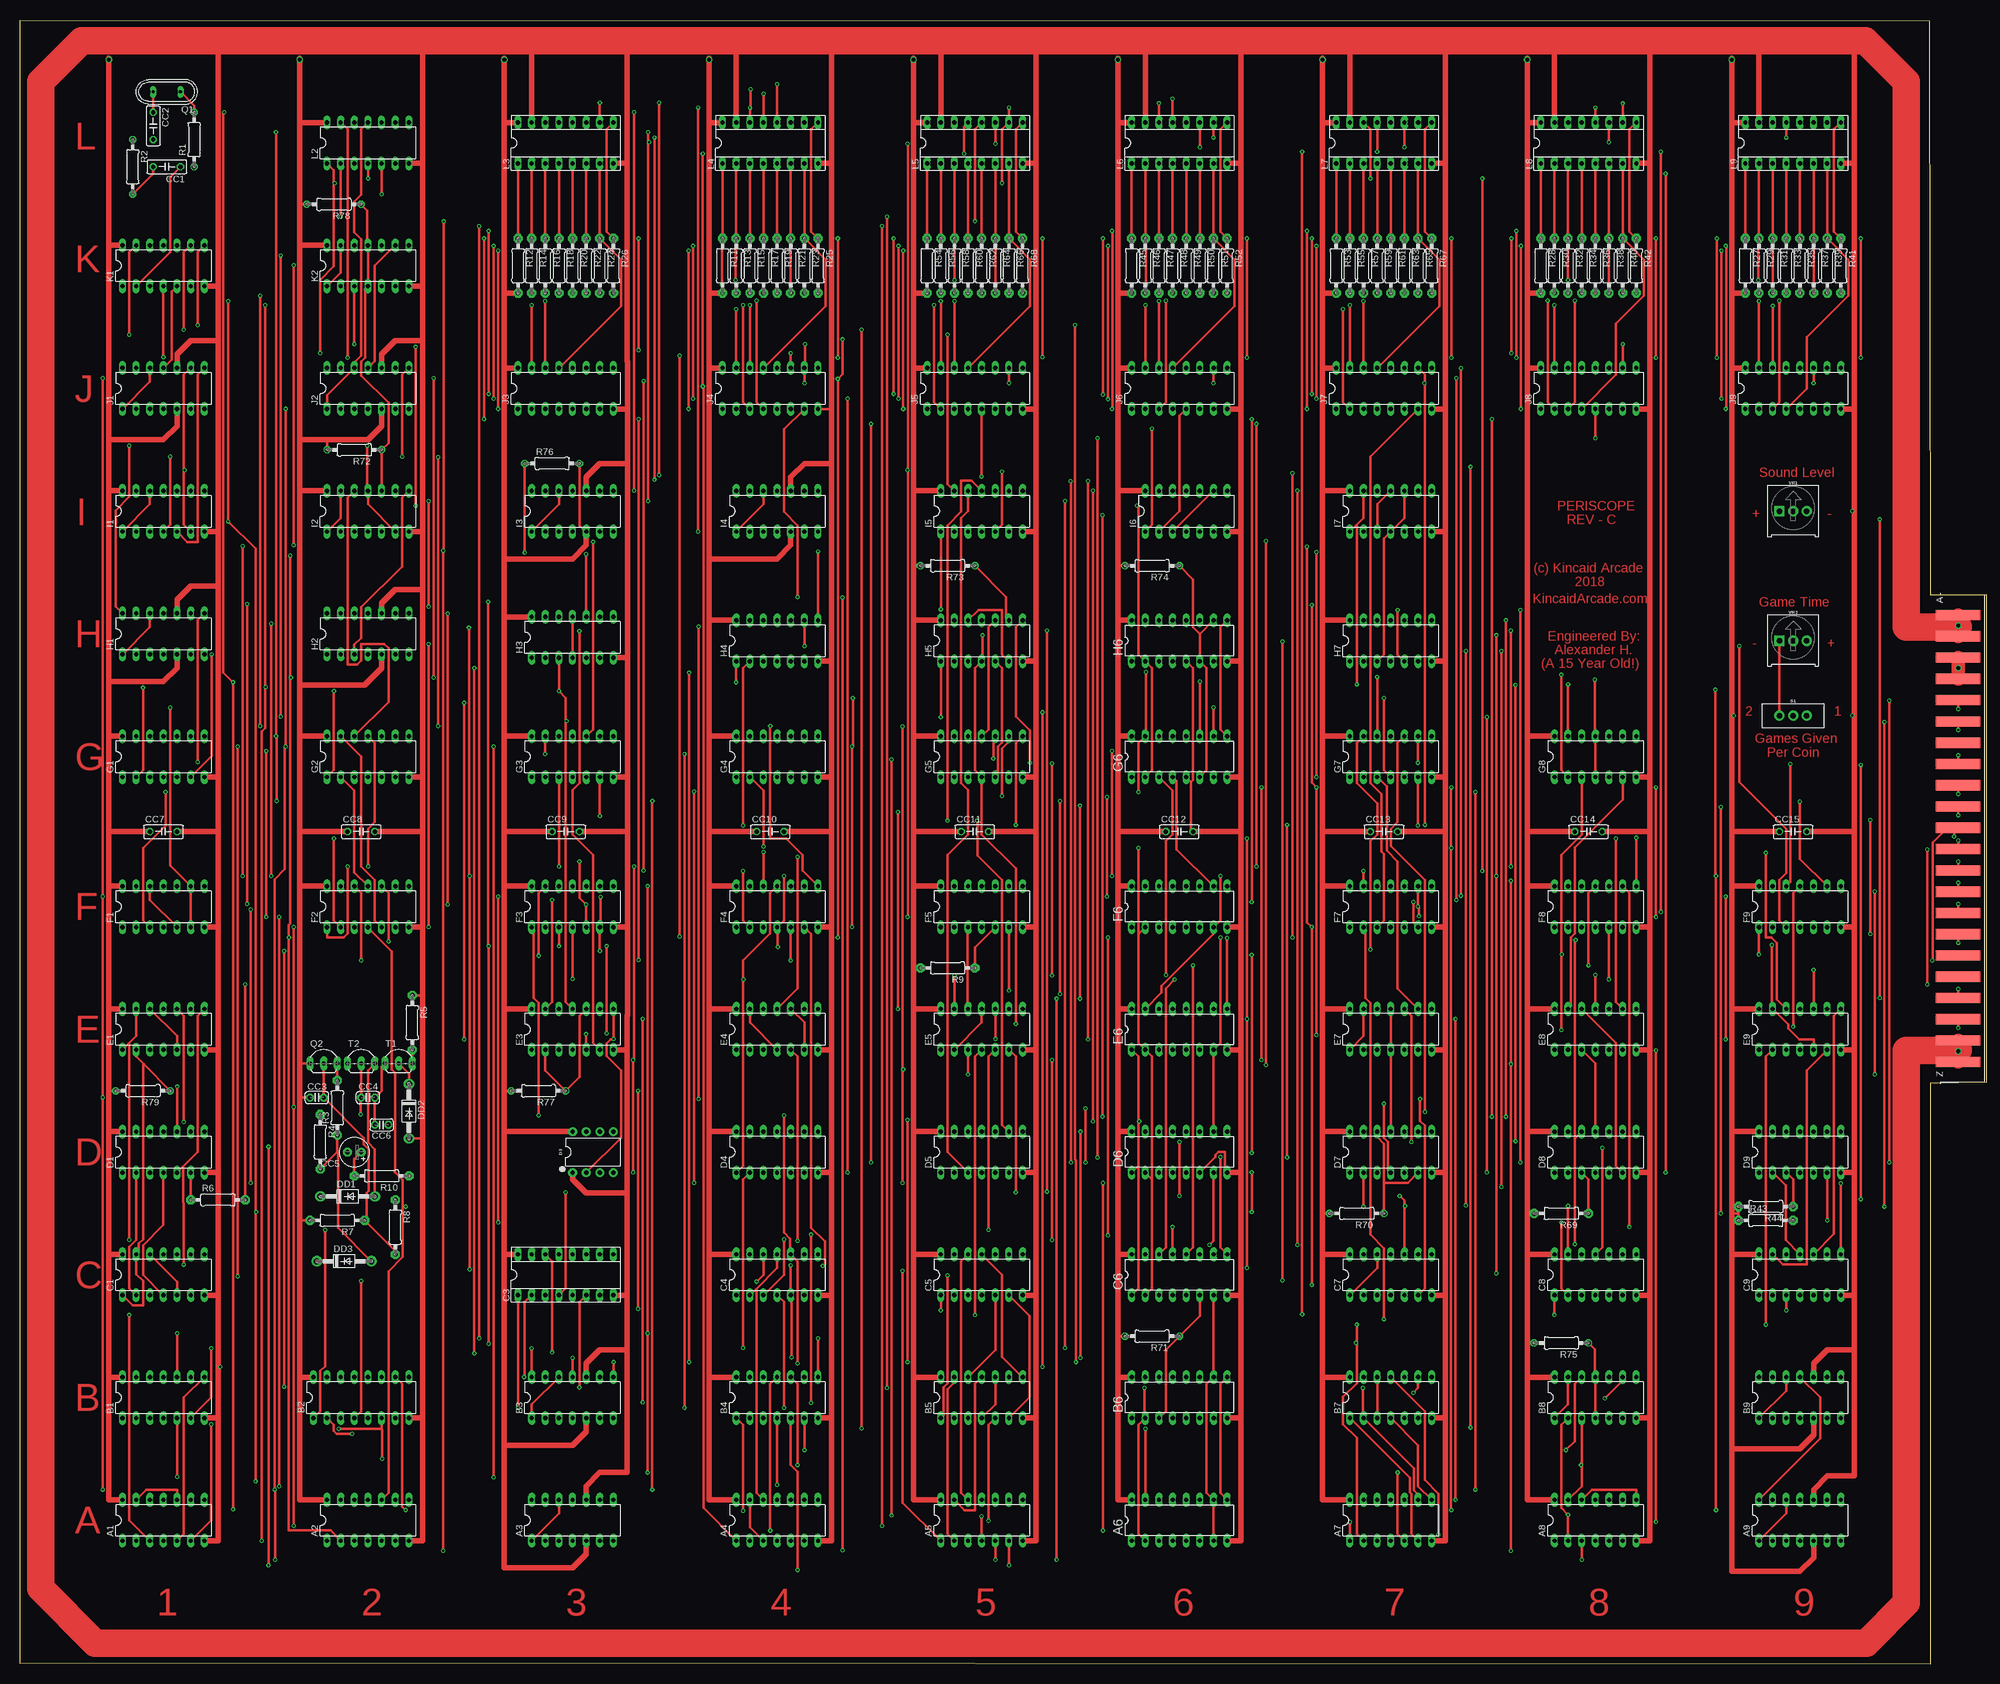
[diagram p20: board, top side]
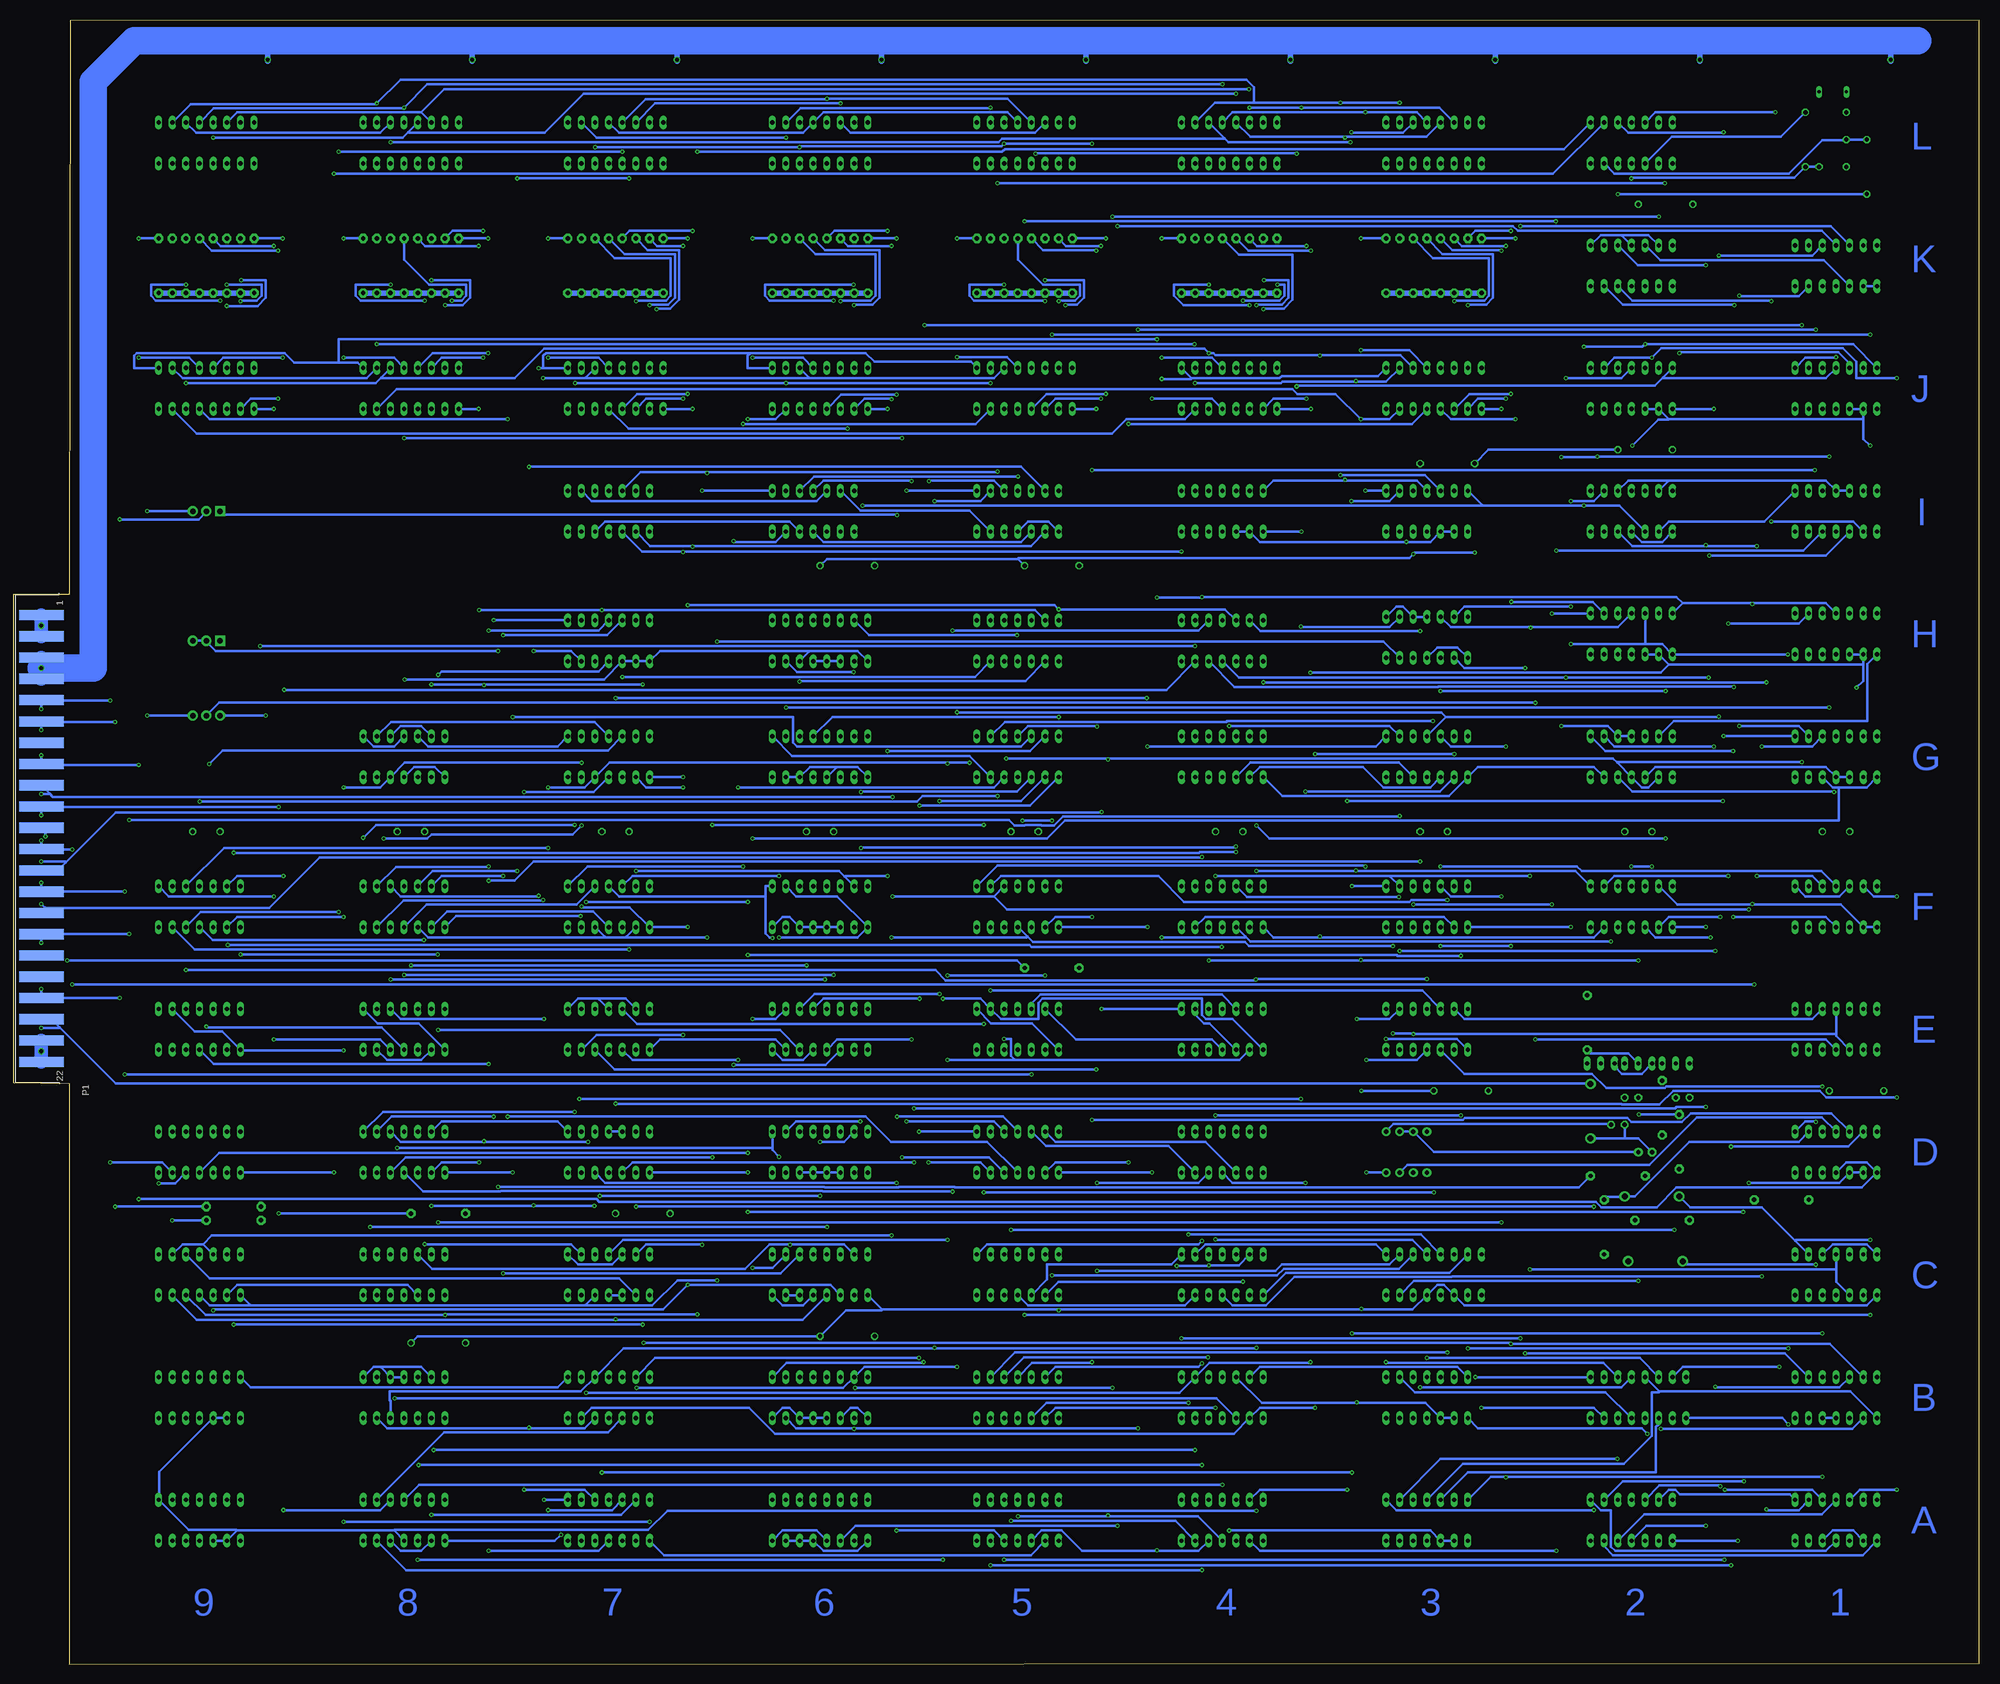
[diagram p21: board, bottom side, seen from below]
Size 366.14 x 306.2 mm. Coordinates in mm from the lower left corner, seen from the top.
Outline: 355.73,199.26 366.14,199.26 366.14,108.33 355.73,108.2 355.73,0 0,0.13 0,306.2 355.6,306.07 355.73,199.26
Copper layers (1*16): Top 0.035mm / dielectric 1.5mm / Bottom 0.035mm
Design rules "default": minimum track width 6mil, minimum drill 0.35mm, track to track 6mil, track to pad 6mil, pad to pad 6mil, via to via 6mil, smd to smd 6mil, copper to edge 40mil, drill to drill 6mil, minimum pad ring 10mil, minimum via ring 8mil, stop-mask expansion 4mil, vias tented up to drill 0mil, thermal gap 10mil
Net classes: 0 default: width 0.508 mm, clearance 0.254 mm

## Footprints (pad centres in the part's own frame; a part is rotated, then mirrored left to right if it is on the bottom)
DIL14 = drill 0.813 long: 1 -7.62,-3.81; 2 -5.08,-3.81; 3 -2.54,-3.81; 4 0,-3.81; 5 2.54,-3.81; 6 5.08,-3.81; 7 7.62,-3.81; 8 7.62,3.81; 9 5.08,3.81; 10 2.54,3.81; 11 0,3.81; 12 -2.54,3.81; 13 -5.08,3.81; 14 -7.62,3.81
DIL16 = drill 0.813 long: 1 -8.89,-3.81; 2 -6.35,-3.81; 3 -3.81,-3.81; 4 -1.27,-3.81; 5 1.27,-3.81; 6 3.81,-3.81; 7 6.35,-3.81; 8 8.89,-3.81; 9 8.89,3.81; 10 6.35,3.81; 11 3.81,3.81; 12 1.27,3.81; 13 -1.27,3.81; 14 -3.81,3.81; 15 -6.35,3.81; 16 -8.89,3.81
SOCKET-16 = drill 0.813 long: 1 -8.89,-3.81; 2 -6.35,-3.81; 3 -3.81,-3.81; 4 -1.27,-3.81; 5 1.27,-3.81; 6 3.81,-3.81; 7 6.35,-3.81; 8 8.89,-3.81; 9 8.89,3.81; 10 6.35,3.81; 11 3.81,3.81; 12 1.27,3.81; 13 -1.27,3.81; 14 -3.81,3.81; 15 -6.35,3.81; 16 -8.89,3.81
C050-025X075 = drill 0.813 octagon: 1 -2.54,0; 2 2.54,0
C025-024X044 = drill 0.813 pad 1.422 octagon: 1 -1.27,0; 2 1.27,0
E2,5-6 = drill 0.813 pad 1.6: + -1.27,0 | drill 0.813 pad 1.6 octagon: - 1.27,0
DIP08 = drill 0.813 pad 1.626: 1 -3.81,-3.81; 2 -1.27,-3.81; 3 1.27,-3.81; 4 3.81,-3.81; 5 3.81,3.81; 6 1.27,3.81; 7 -1.27,3.81; 8 -3.81,3.81
DO41-10 = drill 1.118 pad 1.93: A 5.08,0; C -5.08,0
44PINEDGE = smd 1.905 x 8.255: 1 -41.605,4.826; 2 -37.643,4.826; 3 -33.68,4.826; 4 -29.718,4.826; 5 -25.756,4.826; 6 -21.793,4.826; 7 -17.831,4.826; 8 -13.868,4.826; 9 -9.906,4.826; 10 -5.944,4.826; 11 -1.981,4.826; 12 1.981,4.826; 13 5.944,4.826; 14 9.906,4.826; 15 13.868,4.826; 16 17.831,4.826; 17 21.793,4.826; 18 25.756,4.826; 19 29.718,4.826; 20 33.68,4.826; 21 37.643,4.826; 22 41.605,4.826 | smd 1.905 x 8.255 bottom: A -41.605,4.826; B -37.643,4.826; C -33.68,4.826; D -29.718,4.826; E -25.756,4.826; F -21.793,4.826; H -17.831,4.826; J -13.868,4.826; K -9.906,4.826; L -5.944,4.826; M -1.981,4.826; N 1.981,4.826; P 5.944,4.826; R 9.906,4.826; S 13.868,4.826; T 17.831,4.826; U 21.793,4.826; V 25.756,4.826; W 29.718,4.826; X 33.68,4.826; Y 37.643,4.826; Z 41.605,4.826
QS = drill 0.61 long: 1 -2.54,0; 2 2.54,0
TO92-EBC-OVAL = drill 0.813 long: B 0,-1.27; C 2.54,-1.27; E -2.54,-1.27
0207/10 = drill 0.813 octagon: 1 -5.08,0; 2 5.08,0
0207/10' = drill 0.813 pad 1.676 octagon: 1 -5.08,0; 2 5.08,0
SWITCH_SPDT_PTH_11.6X4.0MM = drill 1.016 pad 1.88: 1 0,2.54; 2 0,0; 3 0,-2.54
TRIMPOT-PTH-3386U = drill 1.016 pad 1.88 square: 1 -2.54,-0.015 | drill 1.016 pad 1.88: 2 0,-0.015; 3 2.54,-0.015

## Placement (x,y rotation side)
A1  74S08N  [DIL14]  26.67,26.8 0 top
A2  74LS21N  [DIL14]  64.77,26.8 0 top
A3  74LS93N  [DIL14]  102.87,26.8 0 top
A4  74LS27N  [DIL14]  140.97,26.8 0 top
A5  7410N  [DIL14]  179.07,26.8 0 top
A6  74161N  [DIL16]  215.9,26.8 0 top
A7  74LS21N  [DIL14]  255.27,26.8 0 top
A8  74S08N  [DIL14]  293.37,26.8 0 top
A9  74LS93N  [DIL14]  331.47,26.8 0 top
B1  74LS21N  [DIL14]  26.67,49.66 0 top
B2  74157N  [DIL16]  63.5,49.66 0 top
B3  74LS93N  [DIL14]  102.87,49.66 0 top
B4  7432N  [DIL14]  140.97,49.66 0 top
B5  7410N  [DIL14]  179.07,49.66 0 top
B6  74161N  [DIL16]  215.9,49.66 0 top
B7  74S08N  [DIL14]  255.27,49.66 0 top
B8  74107N  [DIL14]  293.37,49.66 0 top
B9  74LS93N  [DIL14]  331.47,49.66 0 top
C1  74S74N  [DIL14]  26.67,72.52 0 top
C3  7448  [SOCKET-16]  101.6,72.52 0 top
C4  7410N  [DIL14]  140.97,72.52 0 top
C5  7430N  [DIL14]  179.07,72.52 0 top
C6  74161N  [DIL16]  215.9,72.52 0 top
C7  74S08N  [DIL14]  255.27,72.52 0 top
C8  7400N  [DIL14]  293.37,72.52 0 top
C9  7432N  [DIL14]  331.47,72.52 0 top
CC1  .1uf  [C050-025X075]  27.3,278.89 180 top
CC2  100pf  [C050-025X075]  24.77,286.51 270 top
CC3  .1uf  [C025-024X044]  55.24,105.54 0 top
CC4  .1uf  [C025-024X044]  64.77,105.54 0 top
CC5  100uf  [E2,5-6]  62.23,95.38 180 top
CC6  .01uf  [C025-024X044]  67.31,100.46 180 top
CC7  .1uf  [C050-025X075]  26.67,155.07 0 top
CC8  .1uf  [C050-025X075]  63.5,155.07 0 top
CC9  .1uf  [C050-025X075]  101.6,155.07 0 top
CC10  .1uf  [C050-025X075]  139.7,155.07 0 top
CC11  .1uf  [C050-025X075]  177.8,155.07 0 top
CC12  .1uf  [C050-025X075]  215.9,155.07 0 top
CC13  .1uf  [C050-025X075]  254,155.07 0 top
CC14  .1uf  [C050-025X075]  292.1,155.07 0 top
CC15  .1uf  [C050-025X075]  330.2,155.07 0 top
D1  7404N  [DIL14]  26.67,95.38 0 top
D3  555  [DIP08]  106.68,95.38 0 top
D4  74S08N  [DIL14]  140.97,95.38 0 top
D5  7432N  [DIL14]  179.07,95.38 0 top
D6  74161N  [DIL16]  215.9,95.38 0 top
D7  7430N  [DIL14]  255.27,95.38 0 top
D8  7404N  [DIL14]  293.37,95.38 0 top
D9  7402N  [DIL14]  331.47,95.38 0 top
DD1  1N4004  [DO41-10]  60.96,87.12 0 top
DD2  1N914  [DO41-10]  72.39,103 270 top
DD3  1N914  [DO41-10]  60.33,75.06 0 top
E1  74S74N  [DIL14]  26.67,118.24 0 top
E3  74S74N  [DIL14]  102.87,118.24 0 top
E4  7432N  [DIL14]  140.97,118.24 0 top
E5  7432N  [DIL14]  179.07,118.24 0 top
E6  74161N  [DIL16]  215.9,118.24 0 top
E7  74107N  [DIL14]  255.27,118.24 0 top
E8  7432N  [DIL14]  293.37,118.24 0 top
E9  74LS21N  [DIL14]  331.47,118.24 0 top
F1  7400N  [DIL14]  26.67,141.1 0 top
F2  7404N  [DIL14]  64.77,141.1 0 top
F3  7404N  [DIL14]  102.87,141.1 0 top
F4  7430N  [DIL14]  140.97,141.1 0 top
F5  74S08N  [DIL14]  179.07,141.1 0 top
F6  74161N  [DIL16]  215.9,141.1 0 top
F7  7400N  [DIL14]  255.27,141.1 0 top
F8  7404N  [DIL14]  293.37,141.1 0 top
F9  74S08N  [DIL14]  331.47,141.1 0 top
G1  7402N  [DIL14]  26.67,169.04 0 top
G2  7410N  [DIL14]  64.77,169.04 0 top
G3  7404N  [DIL14]  102.87,169.04 0 top
G4  7486N  [DIL14]  140.97,169.04 0 top
G5  7410N  [DIL14]  179.07,169.04 0 top
G6  74161N  [DIL16]  215.9,169.04 0 top
G7  74S08N  [DIL14]  255.27,169.04 0 top
G8  74107N  [DIL14]  293.37,169.04 0 top
H1  74LS93N  [DIL14]  26.67,191.9 0 top
H2  74LS93N  [DIL14]  64.77,191.9 0 top
H3  74107N  [DIL14]  102.87,191.26 0 top
H4  74LS21N  [DIL14]  140.97,190.63 0 top
H5  74LS21N  [DIL14]  179.07,190.63 0 top
H6  74161N  [DIL16]  215.9,190.63 0 top
H7  7430N  [DIL14]  255.27,190.63 0 top
I1  7430N  [DIL14]  26.67,214.76 0 top
I2  74LS74N  [DIL14]  64.77,214.76 0 top
I3  74LS93N  [DIL14]  102.87,214.76 0 top
I4  74LS93N  [DIL14]  140.97,214.76 0 top
I5  74S08N  [DIL14]  179.07,214.76 0 top
I6  7432N  [DIL14]  217.17,214.76 0 top
I7  74S74N  [DIL14]  255.27,214.76 0 top
J1  74LS93N  [DIL14]  26.67,237.62 0 top
J2  74LS93N  [DIL14]  64.77,237.62 0 top
J3  74151N  [DIL16]  101.6,237.62 0 top
J4  74151N  [DIL16]  139.7,237.62 0 top
J5  74151N  [DIL16]  177.8,237.62 0 top
J6  74151N  [DIL16]  215.9,237.62 0 top
J7  74151N  [DIL16]  254,237.62 0 top
J8  74151N  [DIL16]  292.1,237.62 0 top
J9  74151N  [DIL16]  330.2,237.62 0 top
K1  7400N  [DIL14]  26.67,260.48 0 top
K2  74LS107N  [DIL14]  64.77,260.48 0 top
L2  7404N  [DIL14]  64.77,283.34 0 top
L3  82S23 #1  [SOCKET-16]  101.6,283.34 0 top
L4  82S23 #2  [SOCKET-16]  139.7,283.34 0 top
L5  82S23 #3  [SOCKET-16]  177.8,283.34 0 top
L6  82S23 #4  [SOCKET-16]  215.9,283.34 0 top
L7  82S23 #5  [SOCKET-16]  254,283.34 0 top
L8  82S23 #6  [SOCKET-16]  292.1,283.34 0 top
L9  82S23 #7  [SOCKET-16]  330.2,283.34 0 top
P1  44PINEDGE  [44PINEDGE]  365.76,153.8 270 bottom
Q1  14.13813  [QS]  27.3,292.86 180 top
Q2  2N2907  [TO92-EBC-OVAL]  56.52,113.16 0 top
R1  330  [0207/10]  32.38,283.97 90 top
R2  330  [0207/10]  20.95,278.89 270 top
R3  220  [0207/10']  59.05,103.63 90 top
R4  100  [0207/10']  55.88,97.28 270 top
R5  100  [0207/10']  73.03,119.51 270 top
R6  220  [0207/10']  36.83,86.49 0 top
R7  100  [0207/10']  59.05,82.68 180 top
R8  330  [0207/10']  69.85,81.41 270 top
R9  1K  [0207/10']  172.72,129.67 180 top
R10  220k  [0207/10']  67.31,90.93 180 top
R11  1K  [0207/10']  130.81,260.48 270 top
R12  1K  [0207/10']  92.71,260.48 270 top
R13  1K  [0207/10']  133.35,260.48 270 top
R14  1K  [0207/10']  95.25,260.48 270 top
R15  1K  [0207/10']  135.89,260.48 270 top
R16  1K  [0207/10']  97.79,260.48 270 top
R17  1K  [0207/10']  138.43,260.48 270 top
R18  1K  [0207/10']  100.33,260.48 270 top
R19  1K  [0207/10']  140.97,260.48 270 top
R20  1K  [0207/10']  102.87,260.48 270 top
R21  1K  [0207/10']  143.51,260.48 270 top
R22  1K  [0207/10']  105.41,260.48 270 top
R23  1K  [0207/10']  146.05,260.48 270 top
R24  1K  [0207/10']  107.95,260.48 270 top
R25  1K  [0207/10']  148.59,260.48 270 top
R26  1K  [0207/10']  110.49,260.48 270 top
R27  1K  [0207/10']  321.31,260.48 270 top
R28  1K  [0207/10']  283.21,260.48 270 top
R29  1K  [0207/10']  323.85,260.48 270 top
R30  1K  [0207/10']  285.75,260.48 270 top
R31  1K  [0207/10']  326.39,260.48 270 top
R32  1K  [0207/10']  288.29,260.48 270 top
R33  1K  [0207/10']  328.93,260.48 270 top
R34  1K  [0207/10']  290.83,260.48 270 top
R35  1K  [0207/10']  331.47,260.48 270 top
R36  1K  [0207/10']  293.37,260.48 270 top
R37  1K  [0207/10']  334.01,260.48 270 top
R38  1K  [0207/10']  295.91,260.48 270 top
R39  1K  [0207/10']  336.55,260.48 270 top
R40  1K  [0207/10']  298.45,260.48 270 top
R41  1K  [0207/10']  339.09,260.48 270 top
R42  1K  [0207/10']  300.99,260.48 270 top
R43  1K  [0207/10']  325.12,82.68 0 top
R44  1K  [0207/10']  325.12,85.22 180 top
R45  1K  [0207/10']  207.01,260.48 270 top
R46  1K  [0207/10']  209.55,260.48 270 top
R47  1K  [0207/10']  212.09,260.48 270 top
R48  1K  [0207/10']  214.63,260.48 270 top
R49  1K  [0207/10']  217.17,260.48 270 top
R50  1K  [0207/10']  219.71,260.48 270 top
R51  1K  [0207/10']  222.25,260.48 270 top
R52  1K  [0207/10']  224.79,260.48 270 top
R53  1K  [0207/10']  245.11,260.48 270 top
R54  1K  [0207/10']  168.91,260.48 270 top
R55  1K  [0207/10']  247.65,260.48 270 top
R56  1K  [0207/10']  171.45,260.48 270 top
R57  1K  [0207/10']  250.19,260.48 270 top
R58  1K  [0207/10']  173.99,260.48 270 top
R59  1K  [0207/10']  252.73,260.48 270 top
R60  1K  [0207/10']  176.53,260.48 270 top
R61  1K  [0207/10']  255.27,260.48 270 top
R62  1K  [0207/10']  179.07,260.48 270 top
R63  1K  [0207/10']  257.81,260.48 270 top
R64  1K  [0207/10']  181.61,260.48 270 top
R65  1K  [0207/10']  260.35,260.48 270 top
R66  1K  [0207/10']  184.15,260.48 270 top
R67  1K  [0207/10']  262.89,260.48 270 top
R68  1K  [0207/10']  186.69,260.48 270 top
R69  1K  [0207/10']  287.02,83.95 180 top
R70  1K  [0207/10]  248.92,83.95 180 top
R71  1K  [0207/10]  210.82,61.09 180 top
R72  1K  [0207/10]  62.23,226.19 180 top
R73  1K  [0207/10]  172.72,204.6 180 top
R74  1K  [0207/10]  210.82,204.6 180 top
R75  1K  [0207/10]  287.02,59.82 180 top
R76  1K  [0207/10]  99.06,223.65 0 top
R77  1K  [0207/10]  96.52,106.81 180 top
R78  1K  [0207/10]  58.42,271.91 180 top
R79  1K  [0207/10]  22.86,106.81 180 top
S1  [SWITCH_SPDT_PTH_11.6X4.0MM]  330.2,176.66 270 top
T1  2N2222  [TO92-EBC-OVAL]  70.48,113.16 0 top
T2  2N2222  [TO92-EBC-OVAL]  63.5,113.16 0 top
VR1  10k  [TRIMPOT-PTH-3386U]  330.2,214.76 0 top
VR2  1 MEG  [TRIMPOT-PTH-3386U]  330.2,190.63 0 top

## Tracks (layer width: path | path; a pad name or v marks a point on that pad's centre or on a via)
1H  (via drill 0.35)
  Top 0.508: v184.15,289.94 L5.10 182.88,285.88 v182.88,275.84 | L6.10 v222.25,284.35 | J1.1 24.13,238.89 J1.12 | L2.1 58.42,278.26 58.42,275.84 | 58.42,275.84 58.42,260.35 55.88,257.81 v55.88,244.22 | v58.55,275.84 58.42,275.84
  Bottom 0.508: v184.15,289.94 184.28,289.81 219.58,289.81 L6.10 | L7.10 257.56,284.35 v222.25,284.35 | v55.88,244.22 55.75,244.35 26.29,244.35 24.13,242.19 J1.12 | v58.55,275.84 v182.88,275.84
1PSTART  (via drill 0.35)
  Top 0.508: F5.5 177.8,133.48 R9.1 | v356.11,131.06 356.24,131.19 356.24,153.03 358.9,155.7 360.93,155.7 P1.M 360.17,155.57 v360.17,154.18
  Bottom 0.508: R9.1 179.2,131.06 v356.11,131.06 | v360.17,154.18 360.17,154.94 360.93,155.7 P1.M
1V
  Top 0.508: H1.1 24.13,193.17 H1.12 | G2.13 63.5,169.04 63.5,148.59 66.04,146.05 66.04,138.56 F2.5
  Bottom 0.508: H1.1 20.83,186.31 20.83,175.64 56.9,175.64 G2.13
2H  (via drill 0.35)
  Top 0.508: I1.6 30.48,212.22 30.48,222.38 | 30.48,222.38 30.48,240.16 J1.9 | v165.23,139.19 165.35,139.32 165.35,222.38 | 165.35,222.38 165.35,283.08 v165.23,283.21 | L5.11 v181.61,283.21 | v219.71,282.58 L6.11 | v257.81,282.58 L7.11 | v30.61,222.38 30.48,222.38 | v165.23,222.38 165.35,222.38
  Bottom 0.508: F5.2 172.09,139.19 v165.23,139.19 | v165.23,283.21 v181.61,283.21 182.12,282.7 219.58,282.7 v219.71,282.58 v257.81,282.58 | v165.23,222.38 v30.61,222.38
2V  (via drill 0.35)
  Top 0.508: v46.74,146.81 v46.74,193.8
  Bottom 0.508: H1.9 33.66,193.8 v46.74,193.8 | v46.74,146.81 67.94,146.81 F2.9
4H  (via drill 0.35)
  Top 0.508: I1.5 31.11,209.04 33.02,209.04 33.02,240.16 J1.8 | v26.67,243.46 K1.4 | v78.74,21.08 v78.74,207.39 78.87,207.52 v78.87,268.73 | L5.12 177.8,285.88 v177.8,268.73
  Bottom 0.508: L5.12 180.97,289.05 215.26,289.05 L6.12 219.07,285.24 253.37,285.24 L7.12 | v26.67,243.46 26.8,243.33 32.38,243.33 J1.8 | A4.2 133.99,21.08 v78.74,21.08 | v78.74,207.39 32.77,207.39 I1.5 | v78.87,268.73 v177.8,268.73
4V  (via drill 0.35)
  Top 0.508: A5.4 v179.07,27.56 | F2.11 62.23,147.45 62.23,162.69 G2.2 | G5.10 181.23,172.47 v181.23,168.66 | H1.8 33.02,194.44 v33.02,168.02 | v162.31,168.53 v162.31,27.69
  Bottom 0.508: A4.4 145.54,27.56 162.31,27.56 | v179.07,27.56 162.31,27.56 | G2.2 61.59,163.32 62.87,163.32 G2.4 67.44,167.89 | 162.31,168.66 68.2,168.66 67.44,167.89 | 162.31,168.66 v181.23,168.66 | v33.02,168.02 67.31,168.02 67.44,167.89 | v162.31,27.69 162.31,27.56 | v162.31,168.53 162.31,168.66
8H  (via drill 0.35)
  Top 0.508: L6.13 v214.63,291.59 | v305.56,281.69 v305.56,140.08 | L7.13 v252.73,281.69 | J1.11 28.19,242.95 28.19,255.65 K1.5 | A4.1 127.25,29.08 127.25,237.87 v127.13,238 v127.13,281.31 | L5.13 175.77,286.38 v175.77,281.31
  Bottom 0.508: L5.13 180.97,291.59 v214.63,291.59 214.76,291.47 248.41,291.47 L7.13 | F9.5 331.22,140.08 v305.56,140.08 | v252.73,281.69 v305.56,281.69 | v127.13,238 127,238.12 60.45,238.12 58.93,239.65 | J2.14 58.93,239.65 | J1.11 28.57,239.52 58.8,239.52 58.93,239.65 | v175.77,281.31 175.64,281.43 127.25,281.43 v127.13,281.31
8V  (via drill 0.35)
  Top 0.508: J4.7 142.24,230 142.24,214.63 144.78,212.09 v144.78,198.75 | v153.16,198.63 v153.16,21.21 | v42.29,197.48 v42.29,141.6
  Bottom 0.508: F1.1 F1.2 25.78,141.48 42.29,141.48 | F2.13 56.26,141.48 42.29,141.48 | A4.5 145.41,21.08 153.16,21.08 | 153.16,21.08 167.13,21.08 170.94,24.89 174.62,24.89 A5.3 | H1.11 28.57,197.61 42.29,197.61 | 55.24,197.61 42.29,197.61 | H2.14 55.24,197.61 | 55.24,197.61 56.39,198.75 v144.78,198.75 144.91,198.63 v153.16,198.63 | J9.7 331.98,229.23 161.54,229.23 158.88,231.9 147.96,231.9 J4.7 | v153.16,21.21 153.16,21.08 | v42.29,141.6 42.29,141.48 | v42.29,197.48 42.29,197.61
16H  (via drill 0.35)
  Top 0.508: v201.68,89.66 v201.68,24.89 | A1.13 23.5,32.51 29.21,32.51 A1.10 | v49.4,233.81 v49.4,170.94 49.28,170.81 49.28,148.08 47.37,146.18 v47.37,32.51 47.5,32.39 v47.5,19.43 | J2.1 57.15,236.35 J2.12 62.36,241.55 62.36,242.57 63.5,243.71 63.5,265.43 62.23,266.7 62.23,272.42 63.5,273.69 63.5,285.88 L2.11 | v181.61,19.43 A5.5
  Bottom 0.508: A5.5 183.51,24.89 v201.68,24.89 | v201.68,89.66 255.91,89.66 D7.5 | G2.9 67.94,170.94 v49.4,170.94 | J2.1 v49.4,233.81 | A1.10 31.11,32.51 v47.37,32.51 | v47.5,19.43 v181.61,19.43
16V  (via drill 0.35)
  Top 0.508: G1.6 35.69,169.16 v35.69,188.09 | v76.07,189.99 v76.07,137.29 | A5.2 172.72,24.26 172.72,51.18 173.99,52.45 B5.13 | v144.78,56.01 144.78,75.06 C4.10 143.38,76.45 143.38,79.25 142.24,80.39 v142.24,102.23 | v304.67,26.54 v304.67,114.3 | A7.1 v247.65,26.54 | F3.1 95.63,136.91 95.63,124.08 96.52,123.19 v96.52,102.23
  Bottom 0.508: v35.69,188.09 H2.1 59.05,189.99 62.23,189.99 | v76.07,137.29 F3.1 | 62.23,189.99 v76.07,189.99 | 62.23,189.99 H2.12 | E9.9 332.36,117.86 327.28,117.86 E9.1 323.72,114.3 v304.67,114.3 | A7.1 244.98,20.32 176.66,20.32 A5.2 | v144.78,56.01 145.41,55.37 172.09,55.37 B5.13 | v247.65,26.54 v304.67,26.54 | v142.24,102.23 v96.52,102.23
32H  (via drill 0.35)
  Top 0.508: v60.96,243.33 60.96,285.88 L2.13 | v15.37,32.51 v15.37,105.54 v15.37,143 v15.37,239.52 | D7.4 254.76,92.08 254.76,97.28 254,98.04 v254,104.39
  Bottom 0.508: J2.9 67.94,243.33 v60.96,243.33 59.18,245.11 25.4,245.11 22.86,242.57 22.86,239.52 v15.37,239.52 | A1.12 22.23,32.51 v15.37,32.51 | v15.37,143 19.68,143 F1.13 | v254,104.39 66.67,104.39 66.55,104.27 59.56,104.27 57.02,106.81 29.72,106.81 28.45,105.54 v15.37,105.54
32V  (via drill 0.35)
  Top 0.508: A7.2 248.92,24.26 248.92,42.16 246.38,44.7 246.38,49.78 248.92,52.32 248.92,59.82 | v248.92,63.25 248.92,59.82 | v325.12,63.25 325.12,113.16 E9.2 | v87.25,59.69 v87.25,133.73 87.12,133.86 v87.12,197.87 | F3.3 v100.33,133.73 | v248.79,59.82 248.92,59.82
  Bottom 0.508: v325.12,63.25 v248.92,63.25 | B1.13 27.81,59.69 v87.25,59.69 87.38,59.82 v248.79,59.82 | v100.33,133.73 v87.25,133.73 | H2.9 72.01,197.87 v87.12,197.87
64H  (via drill 0.35)
  Top 0.508: I1.4 27.94,212.22 v27.94,224.92 | v71.12,224.92 71.12,240.16 J2.8 | v50.93,137.29 v50.93,103.76 v50.93,25.78 | v198.37,103.51 v198.37,93.47 | G2.11 66.04,171.58 66.04,156.84 64.77,155.57 v64.77,148.59 | v60.96,148.59 60.96,136.14 60.2,135.38 57.15,135.38 F2.1 | v77.85,174.75 v77.85,224.79
  Bottom 0.508: v27.94,224.92 v71.12,224.92 71.25,224.79 v77.85,224.79 | G2.11 G2.10 69.22,174.75 v77.85,174.75 | A2.4 61.98,25.78 v50.93,25.78 | F2.1 v50.93,137.29 | D7.3 250.82,93.47 v198.37,93.47 | v198.37,103.51 56.64,103.51 56.39,103.76 v50.93,103.76 | v60.96,148.59 v64.77,148.59
64V  (via drill 0.35)
  Top 0.508: F3.5 v105.41,141.48 104.14,142.75 v104.14,149.48 | v79.63,195.71 v79.63,141.48 | v277.62,21.08 v277.62,111.76 v277.62,145.92
  Bottom 0.508: v79.63,141.48 v105.41,141.48 | H2.8 v79.63,195.71 | A7.4 257.18,21.08 v277.62,21.08 | v277.62,111.76 328.8,111.76 E9.4 | v104.14,149.48 269.24,149.48 272.8,145.92 v277.62,145.92
128H  (via drill 0.35)
  Top 0.508: J2.11 66.04,242.7 66.04,260.48 K2.9 | A2.2 57.78,24.89 50.04,24.89 v50.04,135.38 50.04,137.67 50.29,137.92 50.29,183.77 | 50.29,183.77 v50.29,206.5 | v50.42,183.77 50.29,183.77 | v76.96,183.77 v76.96,239.52
  Bottom 0.508: v50.04,135.38 60.33,135.38 F2.3 | I1.3 28.57,206.5 v50.29,206.5 | H4.4 137.92,183.77 v76.96,183.77 v50.42,183.77 | J2.11 66.67,239.52 v76.96,239.52
128V  (via drill 0.35)
  Top 0.508: E9.5 334.01,116.33 331.34,116.33 329.31,118.36 329.31,119.13 E9.13 326.26,122.17 v326.26,133.98 | v142.24,146.81 142.24,138.56 F4.4 141.1,137.16 v141.1,133.6 | v83.69,73.53 v83.69,146.81 83.57,146.94 v83.57,193.04
  Bottom 0.508: H2.11 67.31,193.17 83.57,193.17 | 83.57,193.17 98.42,193.17 H3.12 | C1.3 26.67,71.25 26.67,73.53 | C1.11 26.67,73.53 | 109.73,146.69 109.86,146.81 v142.24,146.81 | 109.73,146.69 F3.9 | v83.69,73.53 26.67,73.53 | v83.69,146.81 109.6,146.81 109.73,146.69 | v326.26,133.98 176.91,133.98 176.53,133.6 v141.1,133.6 | v83.57,193.04 83.57,193.17
256H  (via drill 0.35)
  Top 0.508: v38.73,253.87 v38.73,212.85 43.81,207.77 43.81,84.2 | 43.81,84.2 v43.81,34.04 | v229.36,84.2 v229.36,91.57 | v43.94,84.2 43.81,84.2
  Bottom 0.508: I1.2 23.5,212.85 v38.73,212.85 | v38.73,253.87 38.86,254 64.64,254 K2.5 | A2.9 66.42,34.04 v43.81,34.04 | v229.36,91.57 D7.1 | v43.94,84.2 v229.36,84.2
256V  (via drill 0.35)
  Top 0.508: G2.1 58.42,166.5 v58.42,181.23 | H3.3 v100.33,181.23 101.6,179.96 101.6,175.64 | E3.11 101.6,123.32 101.6,175.64 | v101.73,175.64 101.6,175.64 | F9.9 331.47,149.99 v331.47,160.66 | v182.88,161.67 182.88,170.56 184.15,171.83 G5.9
  Bottom 0.508: v100.33,181.23 v58.42,181.23 | G5.9 181.48,175.51 140.21,175.51 140.08,175.64 v101.73,175.64 | v331.47,160.66 197.87,160.66 196.85,161.67 v182.88,161.67
/1H  (via drill 0.35)
  Top 0.508: A6.2 208.28,24.26 208.28,44.58 B6.2 209.42,45.97 v209.42,51.44 | v59.69,269.62 L2.2 | v161.42,51.44 v161.42,269.62
  Bottom 0.508: v161.42,269.62 v59.69,269.62 | v209.42,51.44 v161.42,51.44
/1V  (via drill 0.35)
  Top 0.508: J9.11 v334.01,238.63 | J4.11 v143.51,244.22 | v122.81,135.51 v122.81,243.71
  Bottom 0.508: 297.69,239.65 298.7,238.63 v334.01,238.63 | 297.69,239.65 J8.11 | J3.11 107.82,243.84 122.81,243.84 | 122.81,243.84 142.24,243.84 142.62,244.22 v143.51,244.22 144.27,244.98 267.33,244.98 272.8,239.52 297.56,239.52 297.69,239.65 | F2.6 71.75,135.38 122.81,135.38 | 122.81,135.38 131.44,135.38 F4.1 | v122.81,243.71 122.81,243.84 | v122.81,135.51 122.81,135.38
/2V  (via drill 0.35)
  Top 0.508: v134.62,147.7 134.62,138.56 F4.2 | v146.05,238.63 J4.10 146.18,241.55 v146.18,245.87 | v298.45,245.87 J8.10 | v116.08,239.01 v116.08,147.83
  Bottom 0.508: F2.8 75.18,147.7 116.08,147.7 | v134.62,147.7 116.08,147.7 | J8.10 300.36,239.52 334.64,239.52 J9.10 | J3.10 110.49,238.89 116.08,238.89 | 116.08,238.89 129.79,238.89 130.05,238.63 v146.05,238.63 | v146.18,245.87 v298.45,245.87 | v116.08,147.83 116.08,147.7 | v116.08,239.01 116.08,238.89
/4V  (via drill 0.35)
  Top 0.508: v68.58,134.62 68.58,143.64 F2.10 | v152.27,135.38 v152.27,239.39 153.16,240.28 v153.16,246.76
  Bottom 0.508: J8.9 302.01,242.44 305.56,242.44 | 305.56,242.44 313.82,242.44 315.6,244.22 343.15,244.22 343.66,243.71 343.66,241.43 J9.9 | J3.9 112.01,239.9 129.92,239.9 130.3,239.52 146.69,239.52 | J4.9 146.69,239.52 | 136.65,135.51 135.76,134.62 v68.58,134.62 | 136.65,135.51 F4.3 | v152.27,239.39 146.81,239.39 146.69,239.52 | v152.27,135.38 136.78,135.38 136.65,135.51 | 305.56,242.44 305.56,246.76 v153.16,246.76
/8V  (via drill 0.35)
  Top 0.508: v143.51,131.06 F4.5 | v63.5,131.06 63.5,143.64 F2.12 | v115.19,131.19 v115.19,231.9
  Bottom 0.508: v63.5,131.06 115.19,131.06 | 115.19,131.06 v143.51,131.06 | J3.7 109.86,231.9 v115.19,231.9 119.89,236.6 127,236.6 127.89,237.49 294.77,237.49 J8.7 | v115.19,131.19 115.19,131.06
/16H  (via drill 0.35)
  Top 0.508: A4.3 135.89,25.53 A4.13 | v47.62,285.37 v47.62,172.85 47.75,172.72 v47.75,160.78 | v117.73,160.78 v117.73,32.51
  Bottom 0.508: v47.62,172.85 G1.8 | v47.62,285.37 47.75,285.24 65.41,285.24 L2.10 | A4.13 133.99,32.51 v117.73,32.51 | v47.75,160.78 v117.73,160.78
/16V  (via drill 0.35)
  Top 0.508: B5.4 181.61,48.39 B5.10 | v143.51,74.3 C4.5 143.64,68.58 v143.64,57.15 | F4.6 147.32,136.02 147.32,81.28 149.86,78.74 149.86,74.55 v149.48,74.17
  Bottom 0.508: F3.2 99.69,139.19 144.15,139.19 F4.6 | C4.13 137.92,74.3 v143.51,74.3 143.64,74.17 v149.48,74.17 | B5.10 177.93,57.15 v143.64,57.15
/32H  (via drill 0.35)
  Top 0.508: v39.62,28.83 v39.62,182.88 37.85,184.66 37.85,288.93 v37.97,289.05 | H4.1 v133.35,182.88
  Bottom 0.508: A1.9 33.66,28.7 39.5,28.7 v39.62,28.83 | v133.35,182.88 v39.62,182.88 | L2.12 60.33,289.05 v37.97,289.05
/32V  (via drill 0.35)
  Top 0.508: D4.1 134.62,92.84 134.62,127.51 | 134.62,127.51 134.62,131.06 139.7,136.14 139.7,143.64 F4.11 | v334.01,129.29 E9.10 | v134.75,127.51 134.62,127.51 | v102.87,127.64 F3.4
  Bottom 0.508: v334.01,129.29 194.44,129.29 192.53,127.38 134.87,127.38 v134.75,127.51 134.62,127.64 v102.87,127.64
/64H  (via drill 0.35)
  Top 0.508: v48.26,139.19 v48.26,33.15 | H4.2 134.62,185.55 v134.62,156.21 | v58.42,153.8 58.42,138.56 F2.2
  Bottom 0.508: A2.12 59.56,33.27 48.39,33.27 v48.26,33.15 | v48.26,139.19 57.78,139.19 F2.2 | v134.62,156.21 132.21,153.8 v58.42,153.8
/64V  (via drill 0.35)
  Top 0.508: v49.15,132.84 v49.15,51.69 | v107.95,132.84 F3.6 108.08,137.41 v108.08,142.88 | E9.12 327.15,123.83 327.15,134.37 326.14,135.38 325.12,135.38 v325.12,151.13 | F4.12 v138.43,151.26
  Bottom 0.508: B1.12 26.04,51.56 49.02,51.56 v49.15,51.69 | v107.95,132.84 v49.15,132.84 | F4.12 136.4,142.88 v108.08,142.88 | v325.12,151.13 145.29,151.13 145.16,151.26 v138.43,151.26
/128H  (via drill 0.35)
  Top 0.508: A2.10 68.58,31.88 68.58,73.15 71.25,75.82 71.25,85.22 | 71.25,85.22 71.25,90.17 69.85,91.57 69.85,110.11 69.22,110.74 69.22,132.72 64.77,137.16 F2.4 | v250.19,85.22 D7.2 | 71.25,85.22 v71.75,85.22
  Bottom 0.508: v71.75,85.22 v250.19,85.22
/128V  (via drill 0.35)
  Top 0.508: A7.5 256.54,24.26 v256.54,35.69 | v116.84,144.91 v116.84,61.59 v116.84,35.69 | v29.21,61.59 B1.10
  Bottom 0.508: v116.84,35.69 v256.54,35.69 | F3.8 v116.84,144.91 | v116.84,61.59 v29.21,61.59
/256H  (via drill 0.35)
  Top 0.508: v44.96,22.99 44.96,173.74 45.59,174.37 45.59,181.99 | v45.59,253.11 45.59,181.99 | v45.72,181.99 45.59,181.99
  Bottom 0.508: v44.96,22.99 A2.1 | v45.59,253.11 45.72,253.24 66.42,253.24 K2.6 | H4.5 138.68,181.99 100.84,181.99 100.71,182.12 45.85,182.12 v45.72,181.99
/256V  (via drill 0.35)
  Top 0.508: v84.58,185.55 v84.58,57.91
  Bottom 0.508: B1.9 36.2,57.91 v84.58,57.91 | v84.58,185.55 95.89,185.55 H3.2
/ACTIVEEXPLOSION  (via drill 0.35)
  Top 0.508: K1.13 20.32,263.02 v20.32,247.65 | v172.72,247.65 172.72,219.84 I5.13 | v270.13,223.01 v270.13,44.07
  Bottom 0.508: B7.5 259.71,43.94 270.13,43.94 | 270.13,43.94 296.55,43.94 B8.6 | v172.72,247.65 v20.32,247.65 | v270.13,223.01 178.44,223.01 I5.13 | v270.13,44.07 270.13,43.94
/FREIGHTERHEN  (via drill 0.35)
  Top 0.508: G3.10 106.68,174.12 v106.68,209.04
  Bottom 0.508: I4.3 I4.2 133.99,209.04 v106.68,209.04 102.23,209.04 I3.3 I3.2
/GAME  (via drill 0.35)
  Top 0.508: E3.6 106.68,115.7 106.68,150.75 102.87,154.56 102.87,162.81 104.14,164.08 v104.14,192.41
  Bottom 0.508: v104.14,192.41 133.86,192.41 H4.13
/HBLANK  (via drill 0.35)
  Top 0.508: F1.6 F1.9 27.94,148.72 v27.94,178.18 | v222.25,178.18 G6.10
  Bottom 0.508: v27.94,178.18 v222.25,178.18
/HITS  (via drill 0.35)
  Top 0.508: E7.10 259.08,120.78 v259.08,97.28 | 248.79,212.09 250.19,213.49 I7.13 | 248.79,212.09 I7.1 | v288.29,182.5 G8.13 | v248.92,182.5 248.92,211.96 248.79,212.09 | v278.51,182.37 v278.51,97.41
  Bottom 0.508: 278.51,97.28 294,97.28 D8.10 | 278.51,97.28 v259.08,97.28 | G8.13 290.19,174.75 294,174.75 G8.10 | v248.92,182.5 278.51,182.5 | 278.51,182.5 v288.29,182.5 | v278.51,97.41 278.51,97.28 | v278.51,182.37 278.51,182.5
/HRESET  (via drill 0.35)
  Top 0.508: v41.4,208.28 v41.4,146.81 | v50.93,208.41 v50.93,260.6
  Bottom 0.508: F1.10 31.11,146.81 v41.4,146.81 | 50.93,208.28 64.64,208.28 I2.5 | 50.93,208.28 v41.4,208.28 | K2.10 63.63,260.6 v50.93,260.6 | v50.93,208.41 50.93,208.28
/HSYNC  (via drill 0.35)
  Top 0.508: C6.2 210.82,69.98 210.82,90.3 210.69,90.42 | D6.2 210.69,90.42 | 210.69,90.42 210.82,90.55 210.82,113.16 E6.2 208.28,115.7 208.28,136.02 208.41,136.14 | 208.41,136.14 F6.2 | G3.3 v100.33,148.59 | v208.28,152.02 208.28,136.27 208.41,136.14 | v138.43,152.27 138.43,162.69 G4.2
  Bottom 0.508: F1.11 29.46,147.7 74.04,147.7 74.93,148.59 v100.33,148.59 | G4.2 133.99,167.13 114.81,167.13 111,163.32 102.23,163.32 G3.3 | v208.28,152.02 208.15,152.15 138.56,152.15 v138.43,152.27
/MOVEDOWN  (via drill 0.35)
  Top 0.508: G7.10 256.54,171.58 256.54,156.84 255.27,155.57 255.27,152.4 261.62,146.05 v261.62,102.87
  Bottom 0.508: v261.62,102.87 297.31,102.87 D8.8
/REPOSSUB  (via drill 0.35)
  Top 0.508: v235.08,71.5 v235.08,190.5
  Bottom 0.508: 259.59,66.93 259.71,66.8 321.94,66.8 322.07,66.93 | 259.59,66.93 C7.5 | C9.1 322.07,66.93 | C9.4 329.56,66.8 322.2,66.8 322.07,66.93 | H3.6 111,190.5 v235.08,190.5 | v235.08,71.5 242.44,71.5 247.14,66.8 259.46,66.8 259.59,66.93
/SQA  (via drill 0.35)
  Top 0.508: v267.46,239.52 v267.46,142.37
  Bottom 0.508: J5.11 183.51,239.52 217.81,239.52 217.93,239.65 | J6.11 217.93,239.65 | F8.6 293.5,142.24 267.59,142.24 v267.46,142.37 | v267.46,239.52 259.71,239.52 259.59,239.65 | J7.11 259.59,239.65 | 217.93,239.65 218.06,239.52 259.46,239.52 259.59,239.65
/SQB  (via drill 0.35)
  Top 0.508: v184.15,238.63 J5.10 | J6.10 v222.25,238.63 | v300.99,153.92 F8.8 | 261.62,238.63 261.62,240.16 J7.10 | 261.62,238.63 v261.62,156.34 | v261.49,238.63 261.62,238.63
  Bottom 0.508: v184.15,238.63 v222.25,238.63 v261.49,238.63 | v300.99,153.92 298.58,156.34 v261.62,156.34
/SQC  (via drill 0.35)
  Top 0.508: v268.35,241.43 v268.35,143.13
  Bottom 0.508: J5.9 187.83,242.57 205.74,242.57 207.39,244.22 228.85,244.22 228.98,244.09 | 228.98,244.09 229.36,243.71 229.36,241.43 J6.9 | F8.10 294,143 268.48,143 v268.35,143.13 | J7.9 267.46,241.43 | 267.46,241.43 v268.35,241.43 | 267.46,241.43 267.46,243.71 266.95,244.22 229.11,244.22 228.98,244.09
/SQD  (via drill 0.35)
  Top 0.508: L6.14 v212.09,290.7 | v272.29,276.73 v272.29,147.7 | v251.46,276.73 251.46,285.88 L7.14
  Bottom 0.508: L5.14 175.9,285.24 210.19,285.24 L6.14 | L7.14 246.63,290.7 v212.09,290.7 | F8.12 288.04,147.7 v272.29,147.7 | v251.46,276.73 v272.29,276.73
/START  (via drill 0.35)
  Top 0.508: E3.8 v110.49,116.46 110.36,116.33 109.98,116.33 109.22,115.57 109.22,113.28 111.89,110.62 111.89,98.04 D3.2
  Bottom 0.508: E3.1 97.28,116.46 v110.49,116.46
/VBLANK  (via drill 0.35)
  Top 0.508: v228.47,73.79 v228.47,120.14 v228.47,153.8
  Bottom 0.508: G1.1 20.95,163.32 26.16,163.32 | 26.16,163.32 27.3,163.32 G1.5 | C6.10 224.79,73.79 v228.47,73.79 | v228.47,120.14 224.16,120.14 E6.10 | 26.16,163.32 26.16,157.1 170.31,157.1 173.61,153.8 v228.47,153.8
/VRESET  (via drill 0.35)
  Top 0.508: v76.07,216.66 v76.07,196.98
  Bottom 0.508: H3.13 95.89,196.98 v76.07,196.98 | v76.07,216.66 71.75,216.66 I2.9
/VSYNC
  Bottom 0.508: G2.6 71.75,167.13 93.34,167.13 G3.1 98.81,161.67 129.79,161.67 G4.1
A  (via drill 0.35)
  Top 0.508: v160.53,25.78 v160.53,267.84
  Bottom 0.508: K1.11 29.34,266.95 85.98,266.95 86.87,267.84 v160.53,267.84 | v160.53,25.78 209.3,25.78 A6.3
ACTIVEEXPLOSION  (via drill 0.35)
  Top 0.508: D4.2 134.62,90.3 v134.62,58.93 | v194.56,58.93 v194.56,216.66
  Bottom 0.508: v134.62,58.93 134.75,58.8 194.56,58.8 | 194.56,58.8 252.48,58.8 B7.10 260.48,50.8 296.04,50.8 296.04,49.15 295.91,49.02 B8.5 | I5.9 186.06,216.66 v194.56,216.66 | v194.56,58.93 194.56,58.8
ADDPOINT  (via drill 0.35)
  Top 0.508: B1.5 v29.21,34.92 | v88.14,34.8 v88.14,170.94
  Bottom 0.508: B1.5 B1.4 | A3.14 90.93,34.92 88.14,34.92 | v29.21,34.92 88.14,34.92 | G3.12 98.42,170.94 v88.14,170.94 | v88.14,34.8 88.14,34.92
ADDTENS  (via drill 0.35)
  Top 0.508: B1.6 35.56,49.66 v35.56,58.8 | B3.14 v95.25,58.8
  Bottom 0.508: v95.25,58.8 v35.56,58.8 | B4.13 133.99,55.37 97.16,55.37 B3.14
ANTENNA  (via drill 0.35)
  Top 0.508: T1.B 72.39,109.98 DD2.C | v360.93,118.49 P1.X
  Bottom 0.508: DD2.C 72.52,108.2 347.09,108.2 357.5,118.62 | 357.5,118.62 358.9,120.02 360.93,120.02 P1.X | v360.93,118.49 357.63,118.49 357.5,118.62
BB  (via drill 0.35)
  Top 0.508: v285.75,65.02 C8.1 | v238.76,65.15 v238.76,281.69
  Bottom 0.508: C9.5 330.33,65.02 v285.75,65.02 285.62,65.15 v238.76,65.15 | L2.8 77.34,282.19 181.48,282.19 181.99,281.69 v238.76,281.69
BLUE  (via drill 0.35)
  Top 0.508: E4.11 144.78,125.86 v144.78,150.37 | v360.93,141.6 P1.S
  Bottom 0.508: v144.78,150.37 144.91,150.24 309.12,150.24 318.52,140.84 360.05,140.84 | 360.05,140.84 360.93,139.95 P1.S | v360.93,141.6 360.3,140.97 360.17,140.97 360.05,140.84
CENTERED  (via drill 0.35)
  Top 0.508: v146.05,189.61 H4.9 | v320.17,189.61 320.17,164.34 328.93,155.57 328.93,147.32 327.66,146.05 327.66,138.56 F9.3
  Bottom 0.508: v320.17,189.61 v146.05,189.61
CLK  (via drill 0.35)
  Top 0.508: K2.3 v62.23,245.87 | G6.2 210.82,166.5 210.82,185.55 H6.2 208.28,188.09 208.28,215.52 v208.03,215.77 | v73.66,215.77 v73.66,245.36
  Bottom 0.508: J1.14 23.5,245.87 v62.23,245.87 62.74,245.36 v73.66,245.36 | I2.3 67.06,215.77 v73.66,215.77 92.46,215.77 92.58,215.9 | I3.14 92.58,215.9 | v208.03,215.77 92.71,215.77 92.58,215.9
COINNC  (via drill 0.35)
  Top 0.508: P1.J v360.93,169.29 | C1.4 22.86,72.52 22.86,77.98 26.67,81.79 D1.4 | v342.77,86.61 v342.77,167.51
  Bottom 0.508: v360.93,169.29 P1.J 360.81,167.51 v342.77,167.51 | D1.4 24.77,93.47 20.95,93.47 D1.1 21.84,88.77 56.39,88.77 60.07,85.09 70.36,85.09 71.37,86.11 257.05,86.11 257.56,86.61 v342.77,86.61
COINNO  (via drill 0.35)
  Top 0.508: C1.2 20.32,69.98 20.32,77.72 21.59,78.99 D1.2 | v202.44,161.54 v202.44,143 | v360.93,162.05 P1.K | v42.93,140.59 v42.93,89.66
  Bottom 0.508: D1.2 D1.3 26.04,89.66 v42.93,89.66 | 183.51,143 F5.10 | v202.44,143 183.51,143 | v202.44,161.54 358.77,161.54 359.41,162.18 | P1.K 359.41,162.18 | v360.93,162.05 359.54,162.05 359.41,162.18 | v42.93,140.59 181.1,140.59 183.51,143
CONDITION1  (via drill 0.35)
  Top 0.508: A7.8 260.35,33.15 260.35,40.77 B7.4 | v267.33,30.61 v267.33,120.14
  Bottom 0.508: E8.10 294,120.14 v267.33,120.14 | A7.8 v267.33,30.61
DFREIGHTER  (via drill 0.35)
  Top 0.508: B7.11 261.62,47.12 261.62,34.29 264.16,31.75 v264.16,24.13
  Bottom 0.508: v264.16,24.13 265.3,22.99 A8.1
DOWN  (via drill 0.35)
  Top 0.508: v230.25,231.01 v230.25,148.59
  Bottom 0.508: F7.8 259.21,148.59 v230.25,148.59 | v230.25,231.01 186.94,231.01 J5.7
ENDEXPLOSION  (via drill 0.35)
  Top 0.508: B4.1 134.62,44.58 v134.62,28.58
  Bottom 0.508: B9.2 B9.3 338.96,35.81 338.96,30.73 A9.8 333.5,25.02 324.61,25.02 324.49,24.89 | 295.27,24.89 A8.4 | 324.49,24.89 295.27,24.89 | 324.49,24.89 A9.2 A9.3 | v134.62,28.58 244.35,28.58 247.9,25.02 295.15,25.02 295.27,24.89
ENONES  (via drill 0.35)
  Top 0.508: A1.6 35.56,26.8 v35.56,44.7 | E5.5 180.34,113.16 v180.34,80.9 | v56.77,80.9 56.77,55.5 55.88,54.61 55.88,47.12 B2.1
  Bottom 0.508: v35.56,44.7 36.7,45.85 B2.1 | v56.77,80.9 v180.34,80.9
ENTENS  (via drill 0.35)
  Top 0.508: A1.3 20.32,26.8 v20.32,65.02 | v177.8,65.02 177.8,113.16 E5.4
  Bottom 0.508: v177.8,65.02 v20.32,65.02
FIRE  (via drill 0.35)
  Top 0.508: D8.3 292.1,90.3 R69.1 | v316.74,159.64 v316.74,83.95 | v360.93,158.11 P1.L
  Bottom 0.508: v316.74,83.95 R69.1 | v316.74,159.64 360.93,159.64 P1.L v360.93,158.11
FQA  (via drill 0.35)
  Top 0.508: v298.45,290.7 L8.10 | I3.1 100.33,216.03 I3.12 | v107.95,290.83 L3.10 | v119,290.83 v119,221.49
  Bottom 0.508: L9.10 333.12,290.58 298.58,290.58 v298.45,290.7 294,295.15 136.53,295.15 135.13,293.75 135.13,290.83 | 135.13,290.83 142.37,290.83 L4.10 | 135.13,290.83 v119,290.83 v107.95,290.83 | I3.12 103.25,221.49 v119,221.49
FQB  (via drill 0.35)
  Top 0.508: v116.97,285.37 116.97,283.46 | 116.97,283.46 v116.97,216.66 | v117.09,283.46 116.97,283.46 | v295.91,283.46 L8.11
  Bottom 0.508: L8.11 297.81,285.24 332.11,285.24 L9.11 | I3.9 109.86,216.66 v116.97,216.66 | v116.97,285.37 116.84,285.24 107.31,285.24 L3.11 | 140.59,284.23 139.83,283.46 v117.09,283.46 | 140.59,284.23 L4.11 | v295.91,283.46 182.63,283.46 181.99,284.1 140.72,284.1 140.59,284.23
FQC  (via drill 0.35)
  Top 0.508: v293.37,289.94 L8.12 | v114.3,289.05 v114.3,218.57 | L4.12 v140.97,294.26
  Bottom 0.508: L9.12 328.8,289.81 293.5,289.81 v293.37,289.94 289.05,294.26 v140.97,294.26 | v114.3,218.57 I3.8 | L3.12 104.78,289.05 v114.3,289.05 139.06,289.05 L4.12
FQD  (via drill 0.35)
  Top 0.508: L9.13 v328.93,284.35 | v118.11,284.35 v118.11,220.6 | L4.13 v138.43,292.48
  Bottom 0.508: 292.61,285.37 293.62,284.35 v328.93,284.35 | 292.61,285.37 L8.13 | I3.11 104.78,220.47 118.11,220.47 | 118.11,220.47 131.44,220.47 I4.14 | L3.13 103,284.48 118.11,284.48 | 118.11,284.48 135.76,284.48 L4.13 | v118.11,220.6 118.11,220.47 | v118.11,284.35 118.11,284.48 | v138.43,292.48 259.97,292.48 267.21,285.24 292.48,285.24 292.61,285.37
FQE  (via drill 0.35)
  Top 0.508: I4.1 138.43,216.03 I4.12 | L4.14 v135.89,289.94 136.02,290.07 v136.02,293.37 | v126.24,289.94 v126.24,210.95
  Bottom 0.508: 290.19,289.05 L8.14 | 290.19,289.05 324.49,289.05 L9.14 | L3.14 100.58,289.94 v126.24,289.94 v135.89,289.94 | v126.24,210.95 I4.1 | 290.19,289.05 285.88,293.37 v136.02,293.37
FREIGHTER  (via drill 0.35)
  Top 0.508: v290.83,19.43 A8.3 | v193.04,123.95 v193.04,19.43
  Bottom 0.508: E4.1 139.06,120.14 144.02,120.14 144.78,120.9 144.78,123.95 174.5,123.95 175.26,123.19 175.26,120.14 182.25,120.14 E5.9 186.06,123.95 v193.04,123.95 | v193.04,19.43 v290.83,19.43
FREIGHTEREN
  Top 0.508: B7.12 B7.3
  Bottom 0.508: A8.9 285.88,43.18 255.4,43.18 B7.3
FREIGHTEREXPLOSION  (via drill 0.35)
  Top 0.508: v199.77,218.57 v199.77,101.09
  Bottom 0.508: D5.10 183.51,101.09 v199.77,101.09 | I5.8 v199.77,218.57
FREIGHTERHEN  (via drill 0.35)
  Top 0.508: A7.9 260.35,31.62 259.59,32.39 259.59,36.45 B7.2 250.06,45.97 v250.06,51.44 | v48.51,176.53 v48.51,262.38 | v190.37,177.29 v190.37,55.37
  Bottom 0.508: v250.06,51.44 211.58,51.44 B6.15 207.65,55.37 v190.37,55.37 | K1.10 31.11,262.38 v48.51,262.38 | v48.51,176.53 48.64,176.4 99.31,176.4 | G3.11 99.31,176.4 | v190.37,177.29 100.2,177.29 99.31,176.4
FREIGHTERPROMDATA  (via drill 0.35)
  Top 0.508: v197.49,99.19 v197.49,57.02
  Bottom 0.508: B7.13 246.63,57.02 v197.49,57.02 | D5.8 v197.49,99.19
FREIGHTERVEN
  Top 0.508: B7.1 258.83,34.67 258.83,32 259.08,31.75 259.08,24.26 A7.6
GAME  (via drill 0.35)
  Top 0.508: v105.41,117.35 E3.5 | v109.22,117.48 v109.22,133.73 | v202.56,135.38 v202.56,79.88
  Bottom 0.508: 330.83,78.23 C9.12 | 330.83,78.23 334.64,78.23 C9.9 | E1.3 26.67,116.97 26.67,117.35 | E1.11 26.67,117.35 | 26.67,117.35 v105.41,117.35 105.54,117.48 v109.22,117.48 | 177.29,135.51 176.28,134.49 136.78,134.49 136.02,133.73 v109.22,133.73 | 177.29,135.51 F5.4 | 330.83,78.23 329.18,79.88 v202.56,79.88 | v202.56,135.38 177.42,135.38 177.29,135.51
GND  (via drill 0.35, 0.75)
  Top 0.508: CC6.2 CC4.2 67.31,106.81 67.31,111.25 T1.E | v37.21,55.37 36.83,55.37 | 218.06,164.34 G6.5 | 218.06,164.34 218.06,155.32 CC12.2 | 151.13,233.81 J4.8 | 74.93,124.59 R5.1 | v341.25,176.66 341.63,176.66 | v341.25,214.76 341.63,214.76 | H6.5 218.44,185.55 218.44,164.72 218.06,164.34 | D6.6 222.63,94.49 222.63,94.87 223.14,95.38 224.41,95.38 224.41,91.82 D6.8 | 74.93,97.92 DD2.A
  Top 1.016: K1.7 36.83,256.67 | 36.83,256.67 36.83,302.39 | 36.83,256.67 36.83,246.51 | 36.83,246.51 36.83,210.95 | 36.83,210.95 36.83,200.79 | 36.83,200.79 36.83,165.23 | 36.83,165.23 36.83,155.07 | 36.83,155.07 36.83,137.29 | 36.83,137.29 36.83,114.43 | 36.83,114.43 36.83,91.57 | 36.83,91.57 36.83,68.71 | 36.83,68.71 36.83,55.37 36.83,45.85 | 36.83,45.85 36.83,22.99 A1.7 | B1.7 36.83,45.85 | C1.7 36.83,68.71 | E1.7 36.83,114.43 | F1.7 36.83,137.29 | G1.7 36.83,165.23 | H1.10 29.21,198.25 31.75,200.79 36.83,200.79 | I1.7 36.83,210.95 | J1.10 29.21,243.97 31.75,246.51 36.83,246.51 | L2.7 74.93,279.53 | 74.93,279.53 74.93,302.39 | 74.93,279.53 74.93,256.67 | 74.93,256.67 74.93,246.51 | 74.93,246.51 74.93,210.95 | 74.93,210.95 74.93,200.15 | 74.93,200.15 74.93,165.23 | 74.93,165.23 74.93,155.07 | 74.93,155.07 74.93,137.29 | 74.93,137.29 74.93,124.59 74.93,97.92 74.93,45.85 | 74.93,45.85 74.93,22.99 A2.7 | B2.8 74.93,45.85 | F2.7 74.93,137.29 | G2.7 74.93,165.23 | 74.93,200.15 69.85,200.15 67.31,197.61 H2.10 | J2.10 67.31,243.97 69.85,246.51 74.93,246.51 | K2.7 74.93,256.67 | L3.8 113.03,279.53 | 113.03,279.53 113.03,302.39 | 113.03,279.53 113.03,242.69 113.08,242.63 113.08,233.81 | 113.03,114.43 113.03,120.79 113.08,120.84 113.08,137.29 | 113.03,114.43 113.03,87.76 | 113.03,87.76 113.03,68.71 | 113.03,68.71 113.03,58.55 | 113.03,58.55 113.03,35.69 107.95,35.69 105.41,33.15 A3.10 | 113.08,233.81 113.08,223.65 | 113.08,223.65 113.08,187.45 | 113.08,187.45 113.08,165.23 | 113.08,165.23 113.08,155.07 | 113.08,155.07 113.08,137.29 | I2.7 74.93,210.95 | L4.8 151.13,279.53 | 151.13,279.53 151.13,302.39 | L4.15 133.35,302.39 | L5.15 171.45,302.39 | L3.15 95.25,302.39
  Top 1.016: L6.15 209.55,301.12 210.82,302.39 | L7.15 247.65,302.39 | L8.15 285.75,302.39 | L9.15 323.85,302.39 | L5.8 189.23,279.53 | 189.23,279.53 189.23,302.39 | 189.23,279.53 189.23,233.81 | 189.23,233.81 189.23,210.95 | 189.23,210.95 189.23,186.82 | 189.23,186.82 189.23,165.23 | 189.23,165.23 189.23,155.07 | 189.23,155.07 189.23,137.29 | 189.23,137.29 189.23,114.43 | 189.23,114.43 189.23,91.57 | 189.23,91.57 189.23,68.71 | 189.23,68.71 189.23,45.85 | 189.23,45.85 189.23,22.99 A5.7 | B5.7 189.23,45.85 | C5.7 189.23,68.71 | D5.7 189.23,91.57 | E5.7 189.23,114.43 | F5.7 189.23,137.29 | G5.7 189.23,165.23 | H5.7 189.23,186.82 | I5.7 189.23,210.95 | J5.8 189.23,233.81 | 151.13,279.53 151.13,233.81 151.13,223.65 | 151.13,223.65 151.13,186.82 | 151.13,186.82 151.13,165.23 | 151.13,165.23 151.13,155.07 | 151.13,155.07 151.13,137.29 | 151.13,137.29 151.13,114.43 | 151.13,114.43 151.13,91.57 | 151.13,91.57 151.13,68.71 | 151.13,68.71 151.13,45.85 | 151.13,45.85 151.13,22.99 A4.7 | B4.7 151.13,45.85 | C4.7 151.13,68.71 | D4.7 151.13,91.57 | E4.7 151.13,114.43 | F4.7 151.13,137.29 | G4.7 151.13,165.23 | H4.7 151.13,186.82 | I4.10 143.51,221.11 146.05,223.65 151.13,223.65 | L6.8 227.33,279.53 | 227.33,279.53 227.33,302.39 | 227.33,279.53 227.33,233.81 | 227.33,233.81 227.33,210.95 | 227.33,210.95 227.33,186.82 | 227.33,186.82 227.33,165.23 | 227.33,165.23 227.33,155.07 | 227.33,155.07 227.33,137.29 | 227.33,137.29 227.33,114.43 | 227.33,114.43 227.33,91.57 | 227.33,91.57 227.33,68.71 | 227.33,68.71 227.33,45.85 | 227.33,45.85 227.33,22.99 A6.8 | B6.8 227.33,45.85 | C6.8 227.33,68.71 | D6.8 227.33,91.57 | E6.8 227.33,114.43 | F6.8 227.33,137.29 | G6.8 227.33,165.23 | H6.8 227.33,186.82
  Top 1.016: I6.7 227.33,210.95 | J6.8 227.33,233.81 | L7.8 265.43,279.53 | 265.43,279.53 265.43,302.39 | 265.43,279.53 265.43,233.81 | 265.43,233.81 265.43,210.95 | 265.43,210.95 265.43,186.82 | 265.43,186.82 265.43,165.23 | 265.43,165.23 265.43,155.07 | 265.43,155.07 265.43,137.29 | 265.43,137.29 265.43,114.43 | 265.43,114.43 265.43,91.57 | 265.43,91.57 265.43,68.71 | 265.43,68.71 265.43,45.85 | 265.43,45.85 265.43,22.99 A7.7 | B7.7 265.43,45.85 | C7.7 265.43,68.71 | D7.7 265.43,91.57 | E7.7 265.43,114.43 | F7.7 265.43,137.29 | G7.7 265.43,165.23 | H7.7 265.43,186.82 | I7.7 265.43,210.95 | J7.8 265.43,233.81 | L8.8 303.53,279.53 | 303.53,279.53 303.53,302.39 | 303.53,279.53 303.53,233.81 | 303.53,233.81 303.53,165.23 | 303.53,165.23 303.53,155.07 | 303.53,155.07 303.53,137.29 | 303.53,137.29 303.53,114.43 | 303.53,114.43 303.53,91.57 | 303.53,91.57 303.53,68.71 | 303.53,68.71 303.53,45.85 | 303.53,45.85 303.53,22.99 A8.7 | B8.7 303.53,45.85 | C8.7 303.53,68.71 | E8.7 303.53,114.43 | F8.7 303.53,137.29 | G8.7 303.53,165.23 | J8.8 303.53,233.81 | L9.8 341.63,279.53 | 341.63,279.53 341.63,301.12 342.9,302.39 | 341.63,279.53 341.63,233.81 | 341.63,233.81 J9.8 | 341.63,233.81 341.63,214.76 341.63,176.66 341.63,155.07 | 341.63,155.07 341.63,137.29 | 341.63,137.29 341.63,114.43 | 341.63,114.43 341.63,91.57 | 341.63,91.57 341.63,68.71 | 341.63,68.71 341.63,58.55 | 341.63,58.55 341.63,35.05 336.55,35.05 334.01,32.51 A9.10 | C9.7 341.63,68.71 | B9.10 334.01,56.01 336.55,58.55 341.63,58.55 | D9.7 341.63,91.57 | E9.7 341.63,114.43 | F9.7 341.63,137.29 | 36.83,91.57 D1.7 | J3.8 113.08,233.81 | I3.10 105.41,221.11 107.95,223.65 113.08,223.65 | H3.7 113.08,187.45 | G3.7 113.08,165.23
  Top 1.016: F3.7 113.08,137.29 | E3.7 113.03,114.43 | 113.03,87.76 105.41,87.76 102.87,90.3 D3.1 | C3.8 113.03,68.71 | 113.03,58.55 107.95,58.55 105.41,56.01 B3.10 | D8.7 303.53,91.57 | CC7.2 36.83,155.07 | CC8.2 74.93,155.07 | CC9.2 113.08,155.07 | CC10.2 151.13,155.07 | CC11.2 189.23,155.07 | CC12.2 227.33,155.07 | CC13.2 265.43,155.07 | CC14.2 303.53,155.07 | CC15.2 341.63,155.07
  Top 2.54: P1.A v360.93,193.42 360.93,193.17 P1.B | P1.Y 360.93,114.43 v360.93,114.17 P1.Z
  Top 5.08: 360.93,114.43 360.81,114.3 351.28,114.3 351.28,11.43 343.79,3.94 13.97,3.94 3.81,14.1 3.81,294.77 11.43,302.39 36.83,302.39 74.93,302.39 95.25,302.39 113.03,302.39 133.35,302.39 151.13,302.39 171.45,302.39 189.23,302.39 210.82,302.39 227.33,302.39 247.65,302.39 265.43,302.39 285.75,302.39 303.53,302.39 323.85,302.39 342.9,302.39 343.66,302.39 351.28,294.77 351.28,193.17 360.93,193.17
  Bottom 0.508: T2.E 62.87,109.98 66.55,109.98 67.94,111.38 T1.E | CC5.- 63.5,97.92 66.04,97.92 | DD2.A 66.04,97.92 | 66.04,97.92 CC6.2 | F6.3 F6.4 F6.5 F6.6 221.62,139.19 222.88,139.19 F6.8 | D6.3 D6.4 D6.5 D6.6 | B6.4 B6.5 B6.6 221.62,47.75 222.88,47.75 B6.8 | H6.3 H6.4 H6.5 | A6.4 216.53,24.89 222.88,24.89 A6.8 | B2.15 55.24,55.37 v37.21,55.37 | C6.5 219.07,66.8 222.88,66.8 C6.8 | E6.5 219.07,112.52 222.88,112.52 E6.8 | v341.25,176.66 S1.1 | v341.25,214.76 VR1.3
  Bottom 2.54: P1.A v360.93,193.42 P1.B | P1.Y v360.93,114.17 P1.Z
GREEN  (via drill 0.35)
  Top 0.508: v176.53,109.86 E5.3 | v345.44,143.89 v345.44,109.86 | v360.93,145.54 P1.R
  Bottom 0.508: v345.44,109.86 v176.53,109.86 | v345.44,143.89 P1.R v360.93,145.54
HBLANK
  Top 0.508: F1.5 24.13,142.37 F1.12
  Bottom 0.508: F1.12 26.04,143 32.38,143 F1.8
HITS
  Top 0.508: E8.3 293.37,111.89 D8.11
HRESET  (via drill 0.35)
  Top 0.508: I2.6 64.77,216.03 I2.11 64.64,218.69 v64.64,226.95 | H1.14 17.78,196.98 17.78,214.88 20.32,217.42 v20.32,226.95
  Bottom 0.508: J2.3 J2.2 57.78,231.9 | v20.32,226.95 21.59,228.22 21.59,231.9 | 21.59,231.9 J1.2 J1.3 | 21.59,231.9 57.78,231.9 | v64.64,226.95 59.82,231.77 57.91,231.77 57.78,231.9
INVISIBLE  (via drill 0.35)
  Top 0.508: A8.13 290.83,33.15 290.83,37.08 | B8.3 290.83,37.08 | B4.10 144.78,52.2 v144.78,37.08 | v290.7,37.08 290.83,37.08
  Bottom 0.508: v290.7,37.08 v144.78,37.08
INVISIBLETORPEDO  (via drill 0.35)
  Top 0.508: I5.1 v171.45,196.47 | v241.43,117.22 v241.43,163.32 240.54,164.21 v240.54,197.23
  Bottom 0.508: H4.12 140.46,196.47 v171.45,196.47 172.21,197.23 v240.54,197.23 | I5.4 177.16,212.85 173.35,212.85 I5.1 | E7.6 257.56,117.22 v241.43,117.22 | v241.43,163.32 248.28,163.32 G7.2
JOYDOWN  (via drill 0.35)
  Top 0.508: D9.3 330.2,90.3 R44.1 | v347.22,175.51 v347.22,85.22 | v360.93,173.99 P1.F
  Bottom 0.508: v347.22,85.22 R44.1 | v347.22,175.51 360.93,175.51 P1.F v360.93,173.99
JOYUP  (via drill 0.35)
  Top 0.508: v336.55,82.68 D9.6 | v348.11,179.45 v348.11,93.47 | v360.93,177.93 P1.E
  Bottom 0.508: R43.2 v336.55,82.68 | D9.6 338.45,93.47 v348.11,93.47 | v348.11,179.45 360.93,179.45 P1.E v360.93,177.93
JUSTSHOT  (via drill 0.35)
  Top 0.508: v148.59,207.26 H4.8 | v241.43,207.14 v241.43,165.23 | I7.11 252.73,216.03 I7.3
  Bottom 0.508: 241.43,207.26 249.05,207.26 I7.3 | 241.43,207.26 v148.59,207.26 | v241.43,165.23 G7.1 | v241.43,207.14 241.43,207.26
LEVEL  (via drill 0.35)
  Top 0.508: F7.6 259.46,138.18 v259.46,141.99 | v229.36,231.9 v229.36,141.99
  Bottom 0.508: v229.36,141.99 v259.46,141.99 | v229.36,231.9 224.16,231.9 J6.7
MOVEDOWN  (via drill 0.35)
  Top 0.508: v276.73,194.44 v276.73,101.98
  Bottom 0.508: D8.9 295.66,101.98 v276.73,101.98 | H7.8 v276.73,194.44
MOVETORPEDOH
  Top 0.508: E8.13 288.8,122.56 288.8,135.38 289.56,136.14 289.56,152.15 298.45,161.04 G8.6
N$1
  Top 0.508: CC2.1 Q1.2
N$2
  Bottom 0.508: R2.1 CC2.2 24.89,283.85 29.21,283.85 35.43,277.62 67.94,277.62 L2.6
N$3  (via drill 0.35)
  Top 0.508: v64.77,276.73 L2.4 | K1.2 27.94,263.02 27.94,276.99 CC1.1
  Bottom 0.508: K1.2 K1.1 | CC1.1 R1.1 34.42,276.86 64.64,276.86 v64.77,276.73
N$4  (via drill 0.35)
  Top 0.508: R2.2 24.77,277.62 CC1.2 | v67.31,273.81 L2.5
  Bottom 0.508: R2.2 v67.31,273.81
N$5
  Top 0.508: Q1.1 32.38,290.32 R1.2
  Bottom 0.508: L2.3 57.28,284.48 36.96,284.48 R1.2
N$6
  Bottom 0.508: K1.3 28.96,261.49 59.44,261.49 K2.12
N$7  (via drill 0.35)
  Top 0.508: v201.55,213.99 v201.55,101.98
  Bottom 0.508: D5.11 181.86,101.98 v201.55,101.98 | v201.55,213.99 201.68,214.12 327.15,214.12 327.66,214.63 VR1.1
N$10
  Top 0.508: 137.03,69.85 140.97,73.79 C4.11 | 137.03,69.85 C4.2 | A4.12 137.16,31.88 137.16,69.72 137.03,69.85
N$11
  Bottom 0.508: I1.8 40.01,212.85 57.78,212.85 I2.2
N$14  (via drill 0.35)
  Top 0.508: v146.05,39.88 B4.6 | v287.91,39.88 289.56,41.53 289.56,52.2 B8.12
  Bottom 0.508: v287.91,39.88 v146.05,39.88
N$17
  Top 0.508: G2.12 68.58,179.2 68.58,189.23 67.82,189.99 63.5,189.99 63.5,186.94 62.74,186.18 60.96,186.18 60.96,217.3 I2.12
N$19  (via drill 0.35)
  Top 0.508: v45.85,170.05 v45.85,139.19
  Bottom 0.508: F1.4 28.57,139.19 v45.85,139.19 | v45.85,170.05 69.6,170.05 G2.8
N$20  (via drill 0.35)
  Top 0.508: F1.3 22.86,138.56 22.86,152.02 27.05,156.21 v27.05,162.43
  Bottom 0.508: v27.05,162.43 27.18,162.56 64.64,162.56 G2.5
N$22
  Bottom 0.508: G3.5 108.08,167.89 135.76,167.89 G4.3
N$24  (via drill 0.35)
  Top 0.508: v144.78,17.53 144.78,35.81 143.51,37.08 B4.5
  Bottom 0.508: A8.6 292.99,17.53 v144.78,17.53
N$26
  Top 0.508: A8.12 292.74,32.51 300.99,32.51 A8.8
N$27  (via drill 0.35)
  Top 0.508: R12.1 L3.1 | v86.36,265.56 v86.36,231.9
  Bottom 0.508: J3.4 98.42,231.9 v86.36,231.9 | R12.1 v86.36,265.56
N$28  (via drill 0.35)
  Top 0.508: F4.8 145.67,147.83 145.67,150.75 142.62,153.8 139.7,153.8 v139.7,174.75
  Bottom 0.508: v139.7,174.75 109.86,174.75 G3.9
N$31  (via drill 0.35)
  Top 0.508: R14.1 L3.2 | v87.25,266.95 v87.25,236.6
  Bottom 0.508: J3.3 95,236.6 v87.25,236.6 | v87.25,266.95 93.85,266.95 R14.1
N$33  (via drill 0.35)
  Top 0.508: B2.4 63.5,47.12 v63.5,71.37
  Bottom 0.508: v63.5,71.37 105.28,71.37 C3.7
N$35
  Top 0.508: A3.1 100.33,28.07 A3.12
  Bottom 0.508: B2.3 59.69,44.7 60.2,44.2 60.2,35.69 95.25,35.69 A3.12
N$36  (via drill 0.35)
  Top 0.508: v88.14,264.16 v88.14,235.71 | R16.1 L3.3
  Bottom 0.508: J3.2 93.34,235.71 v88.14,235.71 | v88.14,264.16 96.39,264.16 R16.1
N$37  (via drill 0.35)
  Top 0.508: v89.03,263.27 v89.03,233.81 | R18.1 L3.4
  Bottom 0.508: v89.03,233.81 J3.1 | v89.03,263.27 89.15,263.4 98.17,263.4 R18.1
N$40  (via drill 0.35)
  Top 0.508: v95.25,253.11 J3.15 | R20.1 L3.5
  Bottom 0.508: v95.25,253.11 95.12,253.24 91.82,253.24 90.55,254.51 90.55,262.64 99.95,262.64 R20.1
N$41  (via drill 0.35)
  Top 0.508: v97.79,253.87 J3.14 | R22.1 L3.6
  Bottom 0.508: v97.79,253.87 97.66,254 92.2,254 91.31,254.89 91.31,261.87 101.73,261.87 R22.1
N$42  (via drill 0.35)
